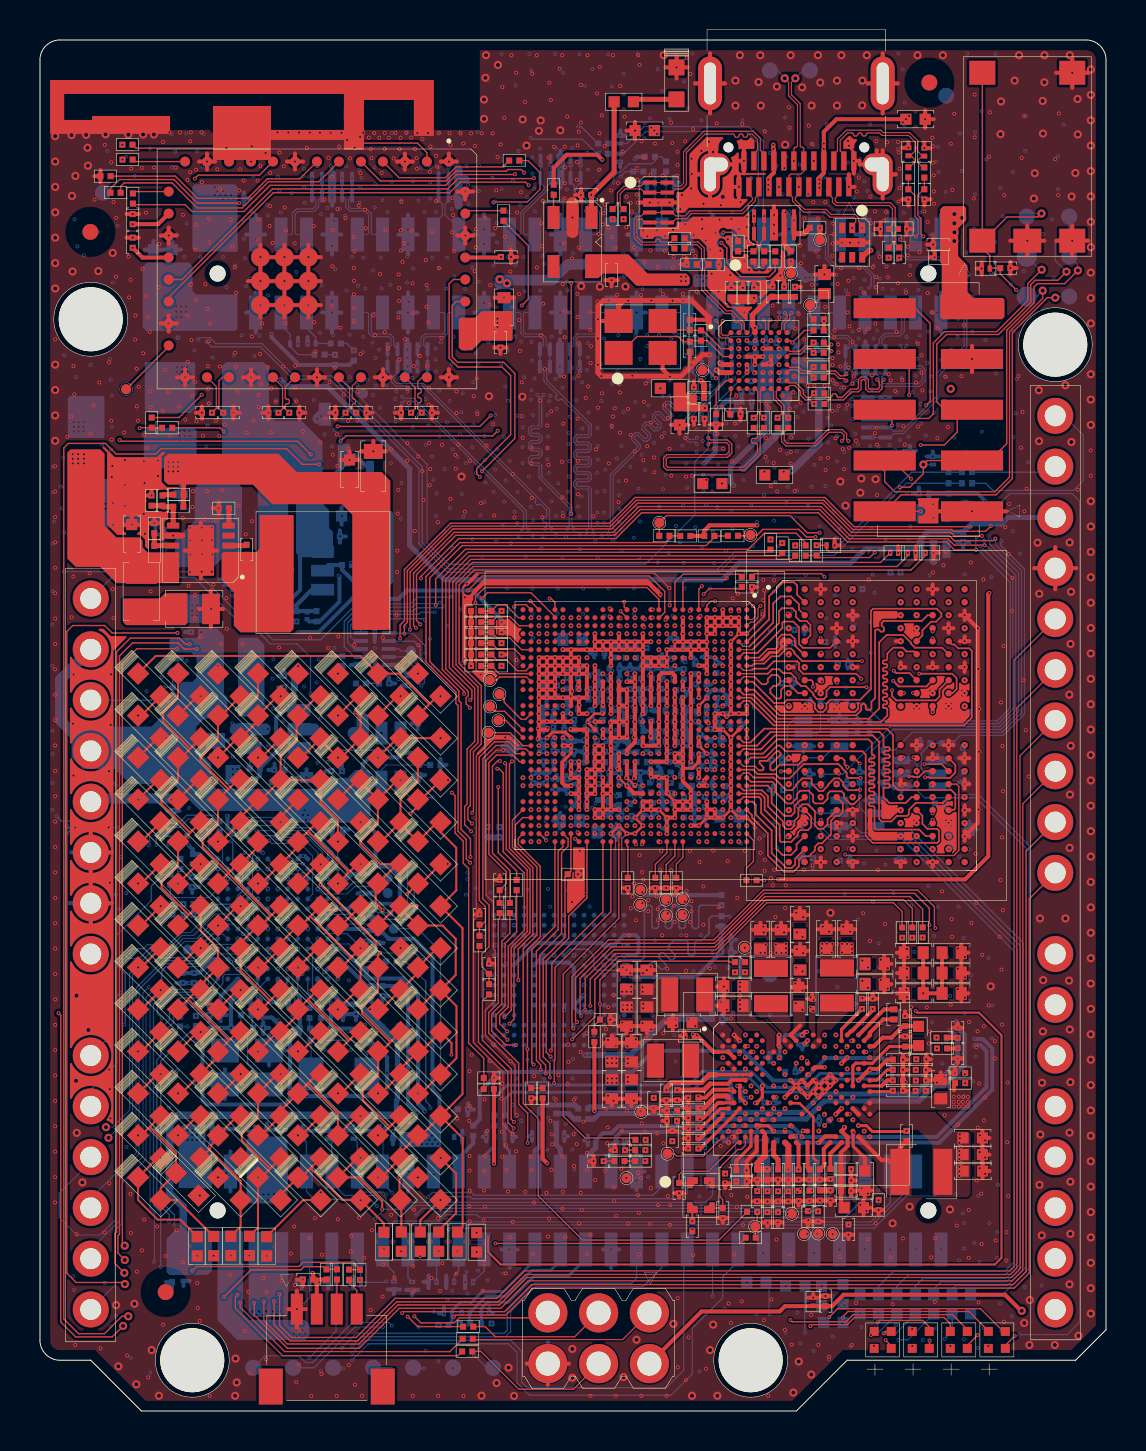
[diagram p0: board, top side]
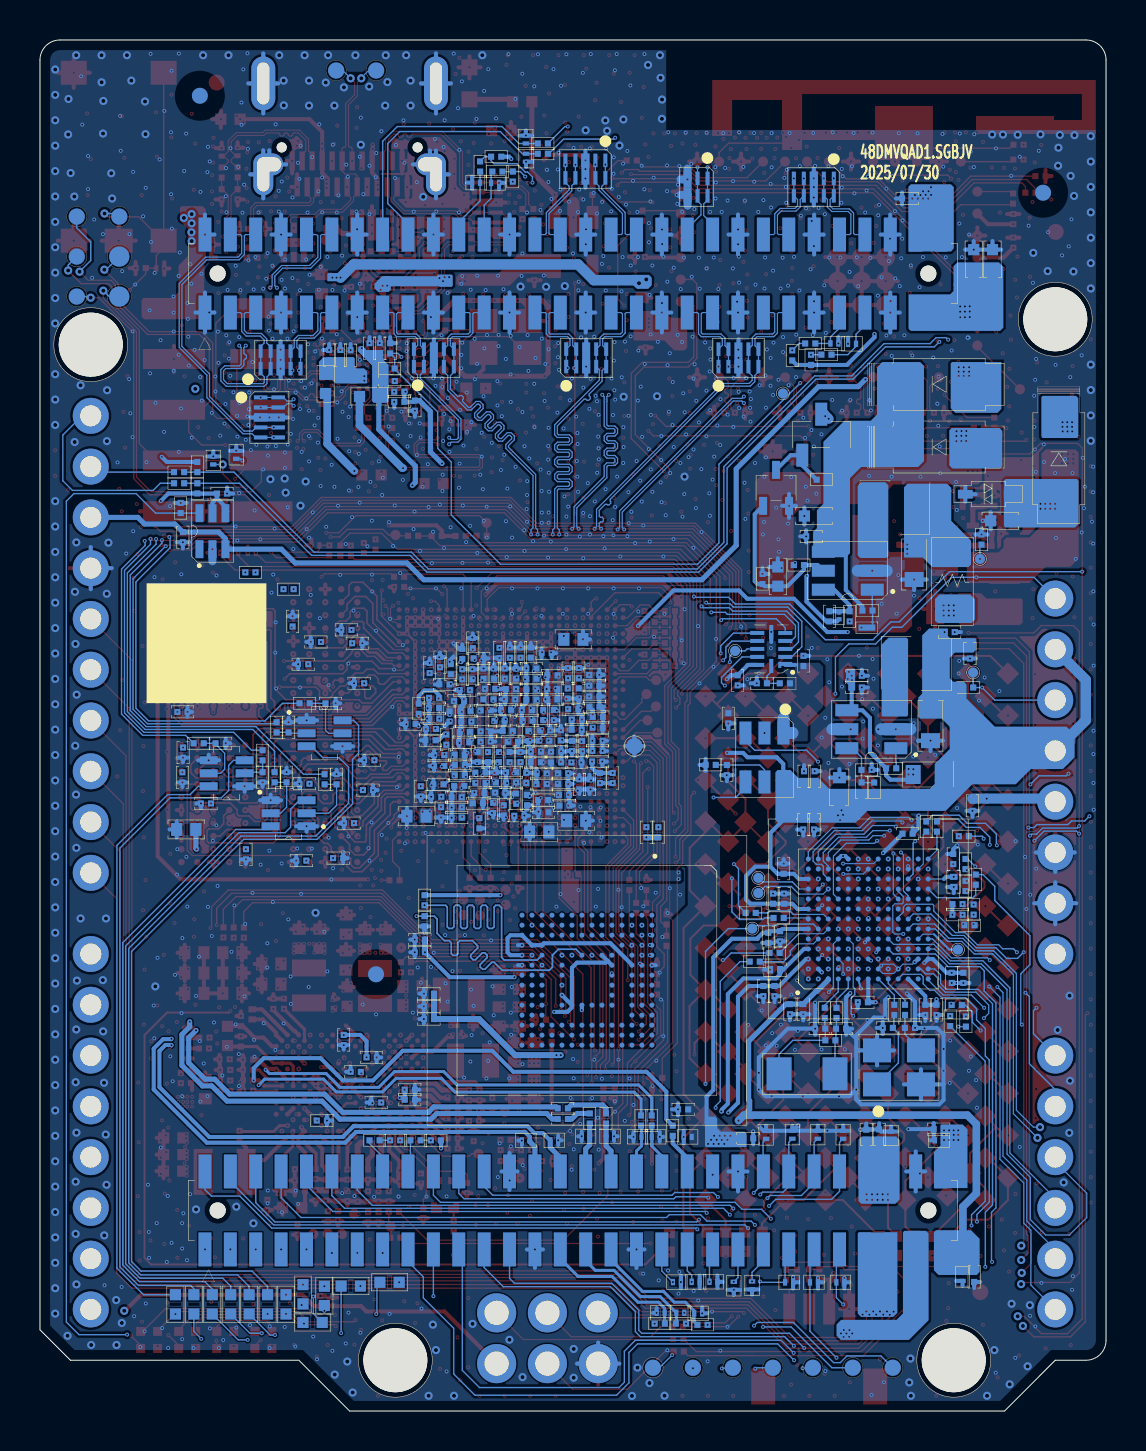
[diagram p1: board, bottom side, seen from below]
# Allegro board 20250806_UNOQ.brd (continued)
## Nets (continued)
AUX_CTRL_2: R3002.1 R3004.1 U3001.H1
BAT_ID: PMIC1.N17 R605.1 TP601.1(TP)
BAT_THERM: PMIC1.U19 R606.1 TP602.1(TP)
BOOT_CAP: C609.1 PMIC1.U25
BOOT_CONFIG0: R1303.2 R1304.1 SOC1.AH9
BOOT_CONFIG1: R1305.2 R1306.1 SOC1.AJ7
BOOT_CONFIG2: R1307.2 R1308.1 SOC1.AH8
BOOT_CONFIG3: R1309.2 R1310.1 SOC1.AH6
CBLPWR_N: PMIC1.T10 R705.1
CC_OUT: PMIC1.C7 R902.1
CCI_I2C_SCL0: R2606.1 R2607.1 SOC1.AD5
CCI_I2C_SCL0_CONN: D26051.2 JMEDIA1.51 R2607.2
CCI_I2C_SCL1: R2610.1 R2611.1 SOC1.AB2
CCI_I2C_SCL1_CONN: D26049.2 JMEDIA1.24 R2611.2
CCI_I2C_SDA0: R2605.1 R2608.1 SOC1.AD4
CCI_I2C_SDA0_CONN: D26050.2 JMEDIA1.53 R2608.2
CCI_I2C_SDA1: R2609.1 R2612.1 SOC1.AC4
CCI_I2C_SDA1_CONN: D26048.2 JMEDIA1.22 R2612.2
CDC_CP_FLY_N: C501.2 PMIC1.A27 PMIC1.B26
CDC_CP_FLY_P: C501.1 PMIC1.A25
CDC_CP_VNEG: C502.1 F501.1 PMIC1.C27
CDC_PA_VNEG: C503.1 F501.2 PMIC1.F26 PMIC1.K24
CSI0_A0_CLK_M: JMEDIA1.33 SOC1.N2 U2610.4 U2610.7
CSI0_A1_LN1_P: JMEDIA1.29 SOC1.P2 U2610.2 U2610.9(OUT#9)
CSI0_A2_LN2_M: JMEDIA1.39 SOC1.R2 U2609.1 U2609.10
CSI0_B0_LN0_P: JMEDIA1.23 SOC1.N3 U2606.5 U2606.6
CSI0_B1_LN1_M: JMEDIA1.27 SOC1.P3 U2610.1 U2610.10
CSI0_B2_LN3_P: JMEDIA1.47 SOC1.R3 U2609.5 U2609.6
CSI0_C0_LN0_M: JMEDIA1.21 SOC1.N4 U2606.4 U2606.7
CSI0_C1_LN2_P: JMEDIA1.41 SOC1.R1 U2609.2 U2609.9(OUT#9)
CSI0_C2_LN3_M: JMEDIA1.45 SOC1.R4 U2609.4 U2609.7
CSI0_NC_CLK_P: JMEDIA1.35 SOC1.N1 U2610.5 U2610.6
CSI1_A0_CLK_M: JMEDIA1.42 SOC1.T2 U2607.1 U2607.6(OUT#6)
CSI1_A1_LN1_P: JMEDIA1.46 SOC1.U2 U2605.5 U2605.6
CSI1_A2_LN2_M: JMEDIA1.36 SOC1.V2 U2608.1 U2608.10
CSI1_B0_LN0_P: JMEDIA1.52 SOC1.T3 U2605.2 U2605.9(OUT#9)
CSI1_B1_LN1_M: JMEDIA1.48 SOC1.U3 U2605.4 U2605.7
CSI1_B2_LN3_P: JMEDIA1.28 SOC1.V3 U2608.5 U2608.6
CSI1_C0_LN0_M: JMEDIA1.54 SOC1.T4 U2605.1 U2605.10
CSI1_C1_LN2_P: JMEDIA1.34 SOC1.V1 U2608.2 U2608.9(OUT#9)
CSI1_C2_LN3_M: JMEDIA1.30 SOC1.V4 U2608.4 U2608.7
CSI1_NC_CLK_P: JMEDIA1.40 SOC1.T1 U2607.2 U2607.5
DC_IN: C2618.1 C2619.1 C2631.1 D2802.1 D26201.2 JANALOG1.8 JMEDIA1.57 JMEDIA1.59
DDR_RESET_N: DRAM1.T11 SOC1.D26
DRAM_ZQ0: DRAM1.A5 R2201.2
DRAM_ZQ1: DRAM1.A8 R2202.2
DSI0_REXT_PLL: R1522.1 SOC1.L30
DSI1_CLK_M_TP: SOC1.M27 TP1501.1(TP)
DSI1_CLK_P_TP: SOC1.M28 TP1502.1(TP)
EAR_M: PMIC1.E27 R2671.1
EAR_M_R: C2632.1 D26064.2 JMISC1.30 R2671.2
EAR_P: PMIC1.D26 R2670.1
EAR_P_R: C2633.1 D26063.2 JMISC1.28 R2670.2
EBI0_CA_0: DRAM1.H2 SOC1.D9
EBI0_CA_1: DRAM1.J2 SOC1.B10
EBI0_CA_2: DRAM1.H9 SOC1.A8
EBI0_CA_3: DRAM1.H10 SOC1.B8
EBI0_CA_4: DRAM1.H11 SOC1.B9
EBI0_CA_5: DRAM1.J11 SOC1.E7
EBI0_CAL: R1401.2 SOC1.F14
EBI0_CKE_0: DRAM1.J4 SOC1.E8
EBI0_CKE_1: DRAM1.J5 SOC1.E9
EBI0_CLK_M: DRAM1.J9 SOC1.E10
EBI0_CLK_P: DRAM1.J8 SOC1.D10
EBI0_CS_0: DRAM1.H4 SOC1.D7
EBI0_CS_1: DRAM1.H3 SOC1.D8
EBI0_DMI_0: DRAM1.C3 SOC1.D5
EBI0_DMI_1: DRAM1.C10 SOC1.A11
EBI0_DQ0: DRAM1.B2 SOC1.A5
EBI0_DQ1: DRAM1.C2 SOC1.B5
EBI0_DQ2: DRAM1.E2 SOC1.B6
EBI0_DQ3: DRAM1.F2 SOC1.A7
EBI0_DQ4: DRAM1.F4 SOC1.D4
EBI0_DQ5: DRAM1.E4 SOC1.B7
EBI0_DQ6: DRAM1.C4 SOC1.E5
EBI0_DQ7: DRAM1.B4 SOC1.C4
EBI0_DQ8: DRAM1.B11 SOC1.E13
EBI0_DQ9: DRAM1.C11 SOC1.D13
EBI0_DQ10: DRAM1.E11 SOC1.B13
EBI0_DQ11: DRAM1.F11 SOC1.B11
EBI0_DQ12: DRAM1.F9 SOC1.B12
EBI0_DQ13: DRAM1.E9 SOC1.A10
EBI0_DQ14: DRAM1.C9 SOC1.E11
EBI0_DQ15: DRAM1.B9 SOC1.D11
EBI0_DQS_0_M: DRAM1.E3 SOC1.D6
EBI0_DQS_0_P: DRAM1.D3 SOC1.E6
EBI0_DQS_1_M: DRAM1.E10 SOC1.E12
EBI0_DQS_1_P: DRAM1.D10 SOC1.D12
EBI1_CA_0: DRAM1.R2 SOC1.E21
EBI1_CA_1: DRAM1.P2 SOC1.B20
EBI1_CA_2: DRAM1.R9 SOC1.A22
EBI1_CA_3: DRAM1.R10 SOC1.B22
EBI1_CA_4: DRAM1.R11 SOC1.B21
EBI1_CA_5: DRAM1.P11 SOC1.D23
EBI1_CKE_0: DRAM1.P4 SOC1.D22
EBI1_CKE_1: DRAM1.P5 SOC1.D21
EBI1_CLK_M: DRAM1.P9 SOC1.D20
EBI1_CLK_P: DRAM1.P8 SOC1.E20
EBI1_CS_0: DRAM1.R4 SOC1.E23
EBI1_CS_1: DRAM1.R3 SOC1.E22
EBI1_DMI_0: DRAM1.Y3 SOC1.E25
EBI1_DMI_1: DRAM1.Y10 SOC1.A19
EBI1_DQ0: DRAM1.AA2 SOC1.A25
EBI1_DQ1: DRAM1.Y2 SOC1.B25
EBI1_DQ2: DRAM1.V2 SOC1.B24
EBI1_DQ3: DRAM1.U2 SOC1.A23
EBI1_DQ4: DRAM1.U4 SOC1.A26
EBI1_DQ5: DRAM1.V4 SOC1.B23
EBI1_DQ6: DRAM1.Y4 SOC1.D25
EBI1_DQ7: DRAM1.AA4 SOC1.B26
EBI1_DQ8: DRAM1.AA11 SOC1.D17
EBI1_DQ9: DRAM1.Y11 SOC1.E17
EBI1_DQ10: DRAM1.V11 SOC1.B17
EBI1_DQ11: DRAM1.U11 SOC1.B19
EBI1_DQ12: DRAM1.U9 SOC1.B18
EBI1_DQ13: DRAM1.V9 SOC1.A20
EBI1_DQ14: DRAM1.Y9 SOC1.D19
EBI1_DQ15: DRAM1.AA9 SOC1.E19
EBI1_DQS_0_M: DRAM1.V3 SOC1.E24
EBI1_DQS_0_P: DRAM1.W3 SOC1.D24
EBI1_DQS_1_M: DRAM1.V10 SOC1.D18
EBI1_DQS_1_P: DRAM1.W10 SOC1.E18
EMMC1_VDDI: C2101.1 C2102.1 EMMC1.C2
FAULT_N_TP: PMIC1.R11 TP704.1(TP)
FM_ANT: R2909.2 U2901.7
FORCED_USB_BOOT_N: D26005.2 JCTL1.2 R901.2 R1311.2 R1312.1 SOC1.AD27 TP2611.1(TP)
FORCED_USB_BOOT_POL_SEL: R1313.2 R1314.1 SOC1.AC27
HPH_L: C509.1 PMIC1.L27 R2634.2
HPH_L_CONN: D26089.2 JMISC1.36 R2634.1
HPH_R: C507.1 PMIC1.J27 R2635.2
HPH_R_CONN: D26090.2 JMISC1.38 R2635.1
HPH_REF: C508.1 PMIC1.K26 R2633.2
HPH_REF_CONN: JMISC1.40 R2633.1
HS_DET: JMISC1.42 PMIC1.C23
JTAG_PS_HOLD: R709.2 TP1213.1(TP)
LDO1_EN: R2801.2 SB2801.2 U2801.1
LDO1_FB: C2803.2 R2802.2 R2803.1 U2801.6
LDO1_LX: L2801.1 U2801.3
LDO1_PG: C2808.1 Q2802.1 R2808.2 R2810.1 U2801.5
LDO2_EN: R2804.2 U2802.1
LDO2_FB: C2807.2 R2805.2 R2806.1 U2802.6
LDO2_LX: L2802.1 U2802.3
LED_MATRIX_0: MCU1.E2 R2711.1
LED_MATRIX_0_R: D27001.1 D27002.2(CATHODE) D27003.1 D27004.2(CATHODE) D27007.1 D27008.2(CATHODE) D27013.1 D27014.2(CATHODE) D27021.1 D27022.2(CATHODE) D27031.1 D27032.2(CATHODE) D27043.1 D27044.2(CATHODE) D27057.1 D27058.2(CATHODE) D27073.1 D27074.2(CATHODE) D27091.1 D27092.2(CATHODE) R2711.2
LED_MATRIX_1: MCU1.F3 R2701.1
LED_MATRIX_1_R: D27001.2(CATHODE) D27002.1 D27005.1 D27006.2(CATHODE) D27009.1 D27010.2(CATHODE) D27015.1 D27016.2(CATHODE) D27023.1 D27024.2(CATHODE) D27033.1 D27034.2(CATHODE) D27045.1 D27046.2(CATHODE) D27059.1 D27060.2(CATHODE) D27075.1 D27076.2(CATHODE) D27093.1 D27094.2(CATHODE) R2701.2
LED_MATRIX_2: MCU1.F4 R2702.1
LED_MATRIX_2_R: D27003.2(CATHODE) D27004.1 D27005.2(CATHODE) D27006.1 D27011.1 D27012.2(CATHODE) D27017.1 D27018.2(CATHODE) D27025.1 D27026.2(CATHODE) D27035.1 D27036.2(CATHODE) D27047.1 D27048.2(CATHODE) D27061.1 D27062.2(CATHODE) D27077.1 D27078.2(CATHODE) D27095.1 D27096.2(CATHODE) R2702.2
LED_MATRIX_3: MCU1.G5 R2703.1
LED_MATRIX_3_R: D27007.2(CATHODE) D27008.1 D27009.2(CATHODE) D27010.1 D27011.2(CATHODE) D27012.1 D27019.1 D27020.2(CATHODE) D27027.1 D27028.2(CATHODE) D27037.1 D27038.2(CATHODE) D27049.1 D27050.2(CATHODE) D27063.1 D27064.2(CATHODE) D27079.1 D27080.2(CATHODE) D27097.1 D27098.2(CATHODE) R2703.2
LED_MATRIX_4: MCU1.G6 R2704.1
LED_MATRIX_4_R: D27013.2(CATHODE) D27014.1 D27015.2(CATHODE) D27016.1 D27017.2(CATHODE) D27018.1 D27019.2(CATHODE) D27020.1 D27029.1 D27030.2(CATHODE) D27039.1 D27040.2(CATHODE) D27051.1 D27052.2(CATHODE) D27065.1 D27066.2(CATHODE) D27081.1 D27082.2(CATHODE) D27099.1 D27100.2(CATHODE) R2704.2
LED_MATRIX_5: MCU1.G4 R2705.1
LED_MATRIX_5_R: D27021.2(CATHODE) D27022.1 D27023.2(CATHODE) D27024.1 D27025.2(CATHODE) D27026.1 D27027.2(CATHODE) D27028.1 D27029.2(CATHODE) D27030.1 D27041.1 D27042.2(CATHODE) D27053.1 D27054.2(CATHODE) D27067.1 D27068.2(CATHODE) D27083.1 D27084.2(CATHODE) D27101.1 D27102.2(CATHODE) R2705.2
LED_MATRIX_6: MCU1.H6 R2706.1
LED_MATRIX_6_R: D27031.2(CATHODE) D27032.1 D27033.2(CATHODE) D27034.1 D27035.2(CATHODE) D27036.1 D27037.2(CATHODE) D27038.1 D27039.2(CATHODE) D27040.1 D27041.2(CATHODE) D27042.1 D27055.1 D27056.2(CATHODE) D27069.1 D27070.2(CATHODE) D27085.1 D27086.2(CATHODE) D27103.1 D27104.2(CATHODE) R2706.2
LED_MATRIX_7: MCU1.G2 R2707.1
LED_MATRIX_7_R: D27043.2(CATHODE) D27044.1 D27045.2(CATHODE) D27046.1 D27047.2(CATHODE) D27048.1 D27049.2(CATHODE) D27050.1 D27051.2(CATHODE) D27052.1 D27053.2(CATHODE) D27054.1 D27055.2(CATHODE) D27056.1 D27071.1 D27072.2(CATHODE) D27087.1 D27088.2(CATHODE) R2707.2
LED_MATRIX_8: MCU1.F1 R2708.1
LED_MATRIX_8_R: D27057.2(CATHODE) D27058.1 D27059.2(CATHODE) D27060.1 D27061.2(CATHODE) D27062.1 D27063.2(CATHODE) D27064.1 D27065.2(CATHODE) D27066.1 D27067.2(CATHODE) D27068.1 D27069.2(CATHODE) D27070.1 D27071.2(CATHODE) D27072.1 D27089.1 D27090.2(CATHODE) R2708.2
LED_MATRIX_9: MCU1.G3 R2709.1
LED_MATRIX_9_R: D27073.2(CATHODE) D27074.1 D27075.2(CATHODE) D27076.1 D27077.2(CATHODE) D27078.1 D27079.2(CATHODE) D27080.1 D27081.2(CATHODE) D27082.1 D27083.2(CATHODE) D27084.1 D27085.2(CATHODE) D27086.1 D27087.2(CATHODE) D27088.1 D27089.2(CATHODE) D27090.1 R2709.2
LED_MATRIX_10: MCU1.H4 R2710.1
LED_MATRIX_10_R: D27091.2(CATHODE) D27092.1 D27093.2(CATHODE) D27094.1 D27095.2(CATHODE) D27096.1 D27097.2(CATHODE) D27098.1 D27099.2(CATHODE) D27100.1 D27101.2(CATHODE) D27102.1 D27103.2(CATHODE) D27104.1 R2710.2
LED_MATRIX_11: MCU1.M5 TP2506.1(TP)
LED_PWR: D27201.1 R2735.2
LINEOUT_M: C514.1 R2632.2
LINEOUT_M_C: C514.2 PMIC1.D24
LINEOUT_M_CONN: D26088.2 JMISC1.34 R2632.1
LINEOUT_P: C513.1 R2631.2
LINEOUT_P_C: C513.2 PMIC1.C25
LINEOUT_P_CONN: D26087.2 JMISC1.32 R2631.1
LNBBCLK1: PMIC1.R5 R702.2
LNBBCLK2: PMIC1.U3 R703.2
LNBBCLK2_R: C720.1 R703.1
MCU_BOOT0: JANALOG1.1 MCU1.C5 R2621.1 TP2603.1(TP) U1101.10
MCU_BOOT0_1P8V: SOC1.AH1 U1101.2
MCU_BT_UART_CTS_R: R2906.2 U2901.14
MCU_BT_UART_RTS_R: R2904.2 U2901.11
MCU_BT_UART_RX_R: R2901.2 U2901.4
MCU_BT_UART_TX_R: R2908.2 U2901.41
MCU_CRS_SYNC_PA10: JMISC1.25 MCU1.F11
MCU_I2C2_SCL: MCU1.K9 R2643.2 R2644.1
MCU_I2C2_SCL_CONN: JDIGITAL1.18 R2644.2
MCU_I2C2_SDA: MCU1.L9 R2642.2 R2645.1
MCU_I2C2_SDA_CONN: JDIGITAL1.17 R2645.2
MCU_I2C4_SCL_PD12: MCU1.K10 R2614.2 R2615.1
MCU_I2C4_SCL_PD12_CONN: QWIIC1.4 R2615.2
MCU_I2C4_SCL_PF14: MCU1.L6 R2667.2 R2668.1
MCU_I2C4_SCL_PF14_CONN: JMISC1.16 R2668.2
MCU_I2C4_SDA_PD13: MCU1.K12 R2613.2 R2616.1
MCU_I2C4_SDA_PD13_CONN: QWIIC1.3 R2616.2
MCU_I2C4_SDA_PF15: MCU1.N6 R2666.2 R2669.1
MCU_I2C4_SDA_PF15_CONN: JMISC1.18 R2669.2
MCU_JTAG_NJTRST_PB4: JDIGITAL1.9 MCU1.B6 TP2504.1(TP)
MCU_JTAG_SWCLK: MCU1.C10 TP2503.1(TP) U1101.8
MCU_JTAG_SWCLK_1P8V: SOC1.AC3 U1101.4
MCU_JTAG_SWDIO: MCU1.F12 TP2502.1(TP) U1101.9
MCU_JTAG_SWDIO_1P8V: SOC1.AC2 U1101.3
MCU_JTAG_SWO_PB3: JDIGITAL1.3 MCU1.D6
MCU_JTAG_TDI: MCU1.A10 TP2501.1(TP)
MCU_LED1_BLU: MCU1.B13 R2731.2
MCU_LED1_BLU_D: D27401.3(CATHODE#4) R2731.1
MCU_LED1_GRN: MCU1.D9 R2730.2
MCU_LED1_GRN_D: D27401.4 R2730.1
MCU_LED1_RED: MCU1.C13 R2729.2
MCU_LED1_RED_D: D27401.2 R2729.1
MCU_LED2_BLU: MCU1.A13 R2734.2
MCU_LED2_BLU_D: D27402.3(CATHODE#4) R2734.1
MCU_LED2_GRN: MCU1.C11 R2733.2
MCU_LED2_GRN_D: D27402.4 R2733.1
MCU_LED2_RED: MCU1.C12 R2732.2
MCU_LED2_RED_D: D27402.2 R2732.1
MCU_MCO_PA8: JMISC1.23 MCU1.G7
MCU_NRST: JANALOG1.3 JSPI1.5 MCU1.H3 R2622.2 TP2602.1(TP) U1101.7
MCU_NRST_1P8V: SOC1.AH2 U1101.5
MCU_OPAMP1_ VINM_PA1: JMISC1.24 MCU1.L3
MCU_OPAMP1_ VINP_PA0: JMISC1.22 MCU1.K3
MCU_OPAMP1_VOUT_PA3: JMISC1.20 MCU1.N2
MCU_OSC32_IN_PC14: MCU1.D1 R2514.2
MCU_OSC32_OUT_PC15: MCU1.E1 R2513.1
MCU_OSC_IN_PH0_R: MCU1.H1 R2509.1
MCU_OSC_OUT_PH1_R: MCU1.J1 R2511.1
MCU_PA4: JANALOG1.9 MCU1.N1
MCU_PA5: JANALOG1.10 MCU1.K4
MCU_PA6: JANALOG1.11 MCU1.N4
MCU_PA7: JANALOG1.12 MCU1.J5
MCU_PA11: JDIGITAL1.6 MCU1.G13
MCU_PA12: JDIGITAL1.5 MCU1.F13
MCU_PB0: JDIGITAL1.4 MCU1.K5
MCU_PB1: JDIGITAL1.7 MCU1.N5
MCU_PB2: JDIGITAL1.8 MCU1.L5
MCU_PB8: JDIGITAL1.10 MCU1.E5
MCU_PC0: JANALOG1.14 MCU1.J2
MCU_PC1: JANALOG1.13 MCU1.J3
MCU_PE7: JMISC1.12 MCU1.L7
MCU_PE8: JMISC1.14 MCU1.K7
MCU_PSSI_D0: JMISC1.1 MCU1.H13
MCU_PSSI_D1: JMISC1.3 MCU1.G12
MCU_PSSI_D2: JMISC1.5 MCU1.G10
MCU_PSSI_D3: JMISC1.7 MCU1.G9
MCU_PSSI_D4: JMISC1.9 MCU1.C2
MCU_PSSI_D5: JMISC1.11 MCU1.B10
MCU_PSSI_D6: JMISC1.13 MCU1.A2
MCU_PSSI_D7: JMISC1.15 MCU1.C3
MCU_PSSI_DE: JMISC1.21 MCU1.L12
MCU_PSSI_PDCK: JMISC1.17 MCU1.L13
MCU_PSSI_RDY: JMISC1.19 MCU1.B3
MCU_SDMMC1_CMD_PD2: JMISC1.2 MCU1.F7
MCU_SOC_LPUART1_CTS: MCU1.J9 R2501.1
MCU_SOC_LPUART1_RTS: MCU1.H10 R2502.1
MCU_SOC_LPUART1_RX: MCU1.H9 R2504.1
MCU_SOC_LPUART1_TX: MCU1.G8 R2503.1
MCU_SPI2_CLK: MCU1.N13 R2641.1
MCU_SPI2_CLK_CONN: JDIGITAL1.14 R2641.2
MCU_SPI2_CLK_PD1: MCU1.F6 R2617.1
MCU_SPI2_CLK_PD1_CONN: JSPI1.3 R2617.2
MCU_SPI2_MISO: MCU1.M12 R2640.1
MCU_SPI2_MISO_CONN: JDIGITAL1.13 R2640.2
MCU_SPI2_MISO_PC2: MCU1.J4 R2618.1
MCU_SPI2_MISO_PC2_CONN: JSPI1.1 R2618.2
MCU_SPI2_MOSI: MCU1.L11 R2626.1
MCU_SPI2_MOSI_CONN: JDIGITAL1.12 R2626.2
MCU_SPI2_MOSI_PC3: MCU1.K1 R2619.1
MCU_SPI2_MOSI_PC3_CONN: JSPI1.4 R2619.2
MCU_SPI2_NSS: MCU1.D5 R2625.1
MCU_SPI2_NSS_CONN: JDIGITAL1.11 R2625.2
MCU_SPI3_CLK: R2505.2 SOC1.AA29
MCU_SPI3_CLK_R: MCU1.A7 R2505.1
MCU_SPI3_CS_N: R2508.2 SOC1.AA30
MCU_SPI3_CS_N_R: MCU1.E6 R2508.1
MCU_SPI3_MISO: R2506.2 SOC1.W30
MCU_SPI3_MISO_R: MCU1.C7 R2506.1
MCU_SPI3_MOSI_1P8V: SOC1.Y29 U1102.3
MCU_SPI3_MOSI_3P3V: R2507.1 U1102.4
MCU_SPI3_MOSI_R: MCU1.C6 R2507.2
MCU_SPI3_RDY: R2516.2 SOC1.W29
MCU_SPI3_RDY_R: MCU1.N10 R2516.1
MCU_TRACE_CLK: JMISC1.4 MCU1.A1
MCU_TRACE_D0: JMISC1.6 MCU1.D3
MCU_TRACE_D2: JMISC1.8 MCU1.D2
MCU_TRACE_D3: JMISC1.10 MCU1.E4
MCU_USART1_RX: MCU1.F5 R2624.1
MCU_USART1_RX_CONN: JDIGITAL1.1 R2624.2
MCU_USART1_TX: MCU1.B5 R2623.1
MCU_USART1_TX_CONN: JDIGITAL1.2 R2623.2
MCU_VCAP: C2501.1 C2525.1 MCU1.A4 MCU1.N11
MCU_VREF+: C2520.1 C2521.1 C2614.1 JDIGITAL1.16 MCU1.L1 U2501.3
MCU_VREF_EN: MCU1.M2 R2515.1 U2501.6
MIC2_BIAS: C512.1 PMIC1.G23 R2646.2
MIC2_BIAS_CONN: D26067.2 JMISC1.33 R2646.1
MIC2_INN: C510.1 PMIC1.L21 R2637.2
MIC2_INN_CONN: D26066.2 JMISC1.31 R2637.1
MIC2_INP: C511.1 PMIC1.M20 R2636.2
MIC2_INP_CONN: D26065.2 JMISC1.29 R2636.1
MIPI_DSI0_CLK_M: R1501.1 SOC1.P27 U3001.H8
MIPI_DSI0_CLK_M_CONN: JMEDIA1.3 R1501.2 U2612.1 U2612.10
MIPI_DSI0_CLK_P: R1502.1 SOC1.R28 U3001.G8
MIPI_DSI0_CLK_P_CONN: JMEDIA1.5 R1502.2 U2612.2 U2612.9(OUT#9)
MIPI_DSI0_L0_M: R1503.1 SOC1.P30 U3001.F8
MIPI_DSI0_L0_M_CONN: JMEDIA1.12 R1503.2 U2611.1 U2611.10
MIPI_DSI0_L0_P: R1504.1 SOC1.R30 U3001.E8
MIPI_DSI0_L0_P_CONN: JMEDIA1.10 R1504.2 U2611.2 U2611.9(OUT#9)
MIPI_DSI0_L1_M: R1505.1 SOC1.M30 U3001.H6
MIPI_DSI0_L1_M_CONN: JMEDIA1.6 R1505.2 U2611.4 U2611.7
MIPI_DSI0_L1_P: R1506.1 SOC1.M29 U3001.H7
MIPI_DSI0_L1_P_CONN: JMEDIA1.4 R1506.2 U2611.5 U2611.6
MIPI_DSI0_L2_M: R1507.1 SOC1.N29 U3001.D8
MIPI_DSI0_L2_M_CONN: JMEDIA1.9 R1507.2 U2612.4 U2612.7
MIPI_DSI0_L2_P: R1508.1 SOC1.P29 U3001.C8
MIPI_DSI0_L2_P_CONN: JMEDIA1.11 R1508.2 U2612.5 U2612.6
MIPI_DSI0_L3_M: R1509.1 SOC1.N28 U3001.H4
MIPI_DSI0_L3_M_CONN: JMEDIA1.15 R1509.2 U2606.1 U2606.10
MIPI_DSI0_L3_P: R1510.1 SOC1.N27 U3001.H5
MIPI_DSI0_L3_P_CONN: JMEDIA1.17 R1510.2 U2606.2 U2606.9(OUT#9)
MUX_ALERT: R3025.2 SOC1.AG29 U3001.B8
MUX_CABLE_DET: SOC1.AG1 TP3007.1(TP) U3001.C3
MUX_DP_HPD: R3028.2 SOC1.K1
MUX_DP_HPD_R: R3028.1 U3001.E7
MUX_I2C_SCL_R: R3014.2 TP3002.1(TP) U3001.D7
MUX_I2C_SDA_R: R3015.2 TP3003.1(TP) U3001.C7
MUX_LDO_EN: R3024.2 U3004.3
MUX_POWER_EN: C3028.1 R3022.2 SOC1.AE1 TP3001.1(TP) U3001.D2
MUX_RESET_N: C3027.1 R3023.2 SOC1.AF5 TP3006.1(TP) U3001.B7
MUX_SBU1: C3019.2 JUSB1.A8 R3003.2 U2602.1 U2602.10
MUX_SBU2: C3020.2 JUSB1.B8 R3004.2 U2602.2 U2602.9(OUT#9)
MUX_SSRXN1: C2629.2 R2665.1 U3001.B3
MUX_SSRXN1_C: C2629.1 D26102.2 JUSB1.B10
MUX_SSRXN2: C2627.1 R2660.1 U3001.A3
MUX_SSRXN2_C: C2627.2 JUSB1.A10 U2601.5 U2601.6
MUX_SSRXP1: C2630.2 R2664.1 U3001.B4
MUX_SSRXP1_C: C2630.1 D26103.2 JUSB1.B11
MUX_SSRXP2: C2628.1 R2661.1 U3001.A2
MUX_SSRXP2_C: C2628.2 JUSB1.A11 U2601.4 U2601.7
MUX_SSTXN1: C2602.2 U3001.A5
MUX_SSTXN1_C: C2602.1 D26105.2 JUSB1.A3
MUX_SSTXN2: C2603.2 U3001.B6
MUX_SSTXN2_C: C2603.1 JUSB1.B3 U2601.1 U2601.10
MUX_SSTXP1: C2601.2 U3001.A6
MUX_SSTXP1_C: C2601.1 D26104.2 JUSB1.A2
MUX_SSTXP2: C2604.2 U3001.B5
MUX_SSTXP2_C: C2604.1 JUSB1.B2 U2601.2 U2601.9(OUT#9)
MUX_XTAL_IN: C3021.1 R3007.2 U3001.D1 Y3001.1
MUX_XTAL_OUT: C3022.1 R3007.1 U3001.C1(XTAL_OUT) Y3001.3
OSC_16M_IN: C2522.1 R2509.2 Y2501.1
OSC_16M_OUT: C2523.1 R2511.2 Y2501.3
OSC_32K_IN: C2528.1 R2512.2 R2514.1 Y2502.2
OSC_32K_OUT: C2527.1 R2512.1 R2513.2 Y2502.1
PACK_VSNS_M: PMIC1.T24 R604.1
PHONE_ON_N: C2605.1 D26009.2 JBTN1.1 JBTN1.2 PMIC1.P12 TP2614.1(TP)
PM_AVDD_BYP: C714.1 PMIC1.K6
PM_DVDD_BYP: C715.1 PMIC1.L7
PM_REF_BYP: C716.1 PMIC1.M6
PM_RESIN_N: D26008.2 JCTL1.8 PMIC1.N9 R708.2
PM_XTAL_IN: C702.1 PMIC1.W5 Y701.3(XT2)
PM_XTAL_OUT: C701.1 PMIC1.Y4 Y701.1
PMIC_FORCED_USB_BOOT: PMIC1.A5 R901.1
PMIC_PWM_TP: PMIC1.D8 TP1301.1(TP)
PON_OPTION: PMIC1.R9 R707.1
PS_HOLD: R706.2 SOC1.AH27
PS_HOLD_R: PMIC1.P10 R706.1 R709.1 TP706.1(TP)
PWR_3P3V: C1102.1 C1104.1 C2502.1 C2503.1 C2504.1 C2505.1 C2506.1 C2507.1 C2508.1 C2509.1 C2510.1 C2511.1 C2512.1 C2513.1 C2517.1 C2518.1 C2519.1 C2529.1 C2610.1 C2615.1 C2616.1 C2620.1 C2807.1 C2809.1 C3025.1 D27301.1 D27302.1 D27401.1 D27402.1 JANALOG1.2 JANALOG1.4 JMEDIA1.58 JMEDIA1.60 JMISC1.53 JMISC1.55 L2802.2 MCU1.A3 MCU1.A8 MCU1.A11 MCU1.B1 MCU1.D13 MCU1.E13 MCU1.G1 MCU1.J13 MCU1.L2 MCU1.N3 MCU1.N7 MCU1.N12 QWIIC1.2 R2613.1 R2614.1 R2622.1 R2642.1 R2643.1 R2666.1 R2667.1 R2735.1 R2805.1 R2817.2 U1101.11(VCCB) U1102.6(VCCB) U2501.4 U2501.5(VCC) U3004.1
PWR_3P8V: C2803.1 C2804.1 C2805.1 C2806.1 L2801.2 R2802.1 R2804.1 R2807.1 R2808.1 R2817.1 U2802.4(VIN)
QCA_SB_CLK: R2902.1 SOC1.AG19
QCA_SB_CLK_R: R2902.2 U2901.6
QCA_SB_DATA: SOC1.AG18 U2901.10
QREFS_CXO_REXT: R1601.1 SOC1.T30
QUIET_THERM: PMIC1.T20 RT701.1
RESOUT_N: EMMC1.K5 SOC1.AJ26
RFCLK1_TP: PMIC1.W1 TP701.1(TP)
RFCLK2: PMIC1.V2 R701.2
RFCLK3_TP: PMIC1.T4 TP702.1(TP)
RTC_SLEEP_CLK: PMIC1.F10 R1204.1 R2903.1
RTC_SLEEP_CLK_R: R2903.2 U2901.9
SBU1_AUXP: C3019.1 U3001.B2
SBU2_AUXN: C3020.1 U3001.C2
SD_CARD_DET_N_TP: SOC1.AH10 TP1315.1(TP)
SDC1_CLK: EMMC1.M6 R1207.2
SDC1_CLK_TR: R1207.1 SOC1.A29
SDC1_CMD: EMMC1.M5 R2114.2 SOC1.C27
SDC1_DATA_0: EMMC1.A3 SOC1.B28
SDC1_DATA_1: EMMC1.A4 SOC1.B29
SDC1_DATA_2: EMMC1.A5 SOC1.B30
SDC1_DATA_3: EMMC1.B2 SOC1.C28
SDC1_DATA_4: EMMC1.B3 SOC1.C29
SDC1_DATA_5: EMMC1.B4 SOC1.C30
SDC1_DATA_6: EMMC1.B5 SOC1.D28
SDC1_DATA_7: EMMC1.B6 SOC1.D29
SDC1_RCLK: EMMC1.H5 R2113.1 SOC1.A28
SLEEP_CLK: R1204.2 SOC1.AH26
SM_LNBBCLK1: R702.1 SOC1.U29
SM_RESIN_N: PMIC1.M14 R1201.1 TP705.1(TP)
SM_RESIN_N_R: C1201.1 R1201.2 SOC1.AJ20
SM_THERM: PMIC1.P18 RT1901.1
SOC_BID0: R1315.2 R1316.1 SOC1.AH3
SOC_BID1: R1317.2 R1318.1 SOC1.AJ2
SOC_BT_UART_CTS: R2906.1 SOC1.E1
SOC_BT_UART_RTS: R2904.1 SOC1.F1
SOC_BT_UART_RX: R2901.1 SOC1.H1
SOC_BT_UART_TX: R2908.1 SOC1.G1
SOC_CAM_MCLK0: R2638.1 SOC1.L2
SOC_CAM_MCLK0_R: D26046.2 JMEDIA1.16 R2638.2
SOC_CAM_MCLK1: R2639.1 SOC1.M2
SOC_CAM_MCLK1_R: D26047.2 JMEDIA1.18 R2639.2
SOC_GPIO18: D26075.2 JMISC1.49 SOC1.M1
SOC_GPIO28: D26076.2 JMISC1.51 SOC1.M4
SOC_GPIO_0_SE0: D26069.2 JMISC1.37 SOC1.T27
SOC_GPIO_1_SE0: D26070.2 JMISC1.39 SOC1.T28
SOC_GPIO_2_SE0: D26071.2 JMISC1.41 SOC1.U27
SOC_GPIO_3_SE0: D26072.2 JMISC1.43 SOC1.V27
SOC_GPIO_82_SE0: D26074.2 JMISC1.47 SOC1.V28
SOC_GPIO_86_SE0: D26073.2 JMISC1.45 SOC1.V30
SOC_GPIO_98: D26091.2 JMISC1.46 SOC1.AG23
SOC_GPIO_99: D26092.2 JMISC1.48 SOC1.AH23
SOC_GPIO_100: D26093.2 JMISC1.50 SOC1.AJ23
SOC_GPIO_101: D26094.2 JMISC1.52 SOC1.AE22
SOC_I2S_D0: R3018.1 SOC1.AJ22
SOC_I2S_D0_R: R3018.2 U3001.F6
SOC_I2S_SCK: R3016.1 SOC1.AF22
SOC_I2S_SCK_R: R3016.2 U3001.F7
SOC_I2S_WS: R3017.1 SOC1.AH22
SOC_I2S_WS_R: R3017.2 U3001.G7
SOC_LED1_BLU: R2714.1 SOC1.AE2
SOC_LED1_BLU_B: C2703.1 Q2708.2 R2714.2
SOC_LED1_BLU_C: Q2708.6 R2725.2
SOC_LED1_BLU_D: D27301.3(CATHODE#4) R2725.1
SOC_LED1_GRN: R2713.1 SOC1.AF3
SOC_LED1_GRN_B: C2702.1 Q2707.5 R2713.2
SOC_LED1_GRN_C: Q2707.3 R2724.2
SOC_LED1_GRN_D: D27301.4 R2724.1
SOC_LED1_RED: R2712.1 SOC1.AG2
SOC_LED1_RED_B: C2701.1 Q2707.2 R2712.2
SOC_LED1_RED_C: Q2707.6 R2723.2
SOC_LED1_RED_D: D27301.2 R2723.1
SOC_LED2_BLU: R2717.1 SOC1.AH4
SOC_LED2_BLU_B: C2706.1 Q2709.5 R2717.2
SOC_LED2_BLU_C: Q2709.3 R2728.2
SOC_LED2_BLU_D: D27302.3(CATHODE#4) R2728.1
SOC_LED2_GRN: R2716.1 SOC1.AG4
SOC_LED2_GRN_B: C2705.1 Q2709.2 R2716.2
SOC_LED2_GRN_C: Q2709.6 R2727.2
SOC_LED2_GRN_D: D27302.4 R2727.1
SOC_LED2_RED: R2715.1 SOC1.AF4
SOC_LED2_RED_B: C2704.1 Q2708.5 R2715.2
SOC_LED2_RED_C: Q2708.3 R2726.2
SOC_LED2_RED_D: D27302.2 R2726.1
SOC_MCU_LPUART1_CTS: R2502.2 SOC1.Y28
SOC_MCU_LPUART1_RTS: R2501.2 SOC1.AA28
SOC_MCU_LPUART1_RX: R2503.2 SOC1.AB28
SOC_MCU_LPUART1_TX: R2504.2 SOC1.AA27
SOC_UART_RX_SE4: D26007.2 JCTL1.6 SOC1.AG30 TP2616.1(TP)
SOC_UART_TX_SE4: D26006.2 JCTL1.4 SOC1.AF29 TP2615.1(TP)
SPMI_CLK: PMIC1.K10 R1205.1
SPMI_CLK_R: C1202.1 R1205.2 SOC1.AH19
SPMI_DATA: PMIC1.K12 R1206.1
SPMI_DATA_R: C1203.1 R1206.2 SOC1.AJ19
SWR_RX_CLK: R502.2 SOC1.AF19
SWR_RX_CLK_R: PMIC1.A21 R502.1
SWR_RX_DATA0: R503.2 SOC1.AE19
SWR_RX_DATA0_R: PMIC1.C21 R503.1
SWR_RX_DATA1: R501.2 SOC1.AF18
SWR_RX_DATA1_R: PMIC1.E19 R501.1
SWR_TX_CLK: PMIC1.D22 R1301.2
SWR_TX_CLK_R: R1301.1 SOC1.AF20
SWR_TX_DATA0: PMIC1.E21 R1302.2
SWR_TX_DATA0_R: R1302.1 SOC1.AE20
TP_GPIO_72: SOC1.AH18 TP1311.1(TP)
TP_GPIO_74: SOC1.AJ17 TP1313.1(TP)
TP_GPIO_75: SOC1.AJ16 TP1314.1(TP)
TP_GPIO_79: SOC1.AH14 TP1310.1(TP)
TP_JTAG_SRST_N: SOC1.AD28 TP1207.1(TP)
TP_JTAG_TCK: SOC1.AD30 TP1208.1(TP)
TP_JTAG_TDI: SOC1.AE30 TP1209.1(TP)
TP_JTAG_TDO: SOC1.AD29 TP1210.1(TP)
TP_JTAG_TMS: SOC1.AE29 TP1211.1(TP)
TP_JTAG_TRST_N: R1208.1 SOC1.AC29 TP1212.1(TP)
TP_USB0_SS_RX1_M: SOC1.G29 TP1203.1(TP)
TP_USB0_SS_RX1_P: SOC1.H29 TP1204.1(TP)
TP_USB0_SS_TX1_M: SOC1.J28 TP1205.1(TP)
TP_USB0_SS_TX1_P: SOC1.J27 TP1206.1(TP)
USB0_HS_DM: JUSB1.A7 JUSB1.B7 SOC1.K29 TP2613.1(TP) U2604.2
USB0_HS_DP: JUSB1.A6 JUSB1.B6 SOC1.K28 TP2612.1(TP) U2604.1
USB0_HS_REXT: R1203.1 SOC1.K30
USB0_SS_REXT: R1202.1 SOC1.J30
USB0_SS_RX0_M: SOC1.F30 U3001.B1
USB0_SS_RX0_P: SOC1.G30 U3001.A1
USB0_SS_TX0_M: SOC1.H27 U3001.A7
USB0_SS_TX0_P: SOC1.G27 U3001.A8
USB_CC1: JUSB1.A5 R3005.2 U2602.4 U2602.7
USB_CC1_R_MUX: R3005.1 TP3004.1(TP) U3001.E1
USB_CC2: JUSB1.B5 R3006.2 U2602.5 U2602.6
USB_CC2_R_MUX: R3006.1 TP3005.1(TP) U3001.F1
USB_I2C_SCL: R3014.1 R3027.2 SOC1.AB29
USB_I2C_SDA: R3015.1 R3026.2 SOC1.AB30
USB_IN_MID: C608.1 C902.1 PMIC1.H12 PMIC1.V24
USB_PHY_PS: R902.2 R1319.2 R1320.1 SOC1.AJ29
USB_VBUS_IN: C601.1 C602.1 C603.1 PMIC1.V22 PMIC1.W23 Q2801.3 R601.1 R607.1 R3013.1
VCOIN: C708.1 C709.1 C710.1 C711.1 C712.1 C713.1 C2524.1 C2526.1 C2625.1 D26100.2 JMISC1.59 MCU1.C1 PMIC1.H16
VCONN_IN: C3016.1 C3017.1 C3018.1 R3013.2 R3019.1 U3001.F2
VFB_NEG_S3: PMIC1.D6
VFB_NEG_S4: PMIC1.E5
VFB_S3: PMIC1.C5
VFB_S4: PMIC1.D4
VOLUME_DOWN_N: D26001.2 JCTL1.3 R708.1 R1321.2 TP2618.1(TP)
VOLUME_DOWN_R: R1321.1 SOC1.AD2
VOLUME_UP_N: D26002.2 JCTL1.5 SOC1.AH30 TP2617.1(TP)
VPH_PWR: C604.1 C605.1 C606.1 C901.1 C1001.1 C1002.1 C1003.1 C1004.1 L601.2 PMIC1.A13 PMIC1.A17 PMIC1.B14 PMIC1.C1 PMIC1.C3 PMIC1.D2 PMIC1.E3 PMIC1.G17 PMIC1.K8 PMIC1.N7 PMIC1.P24 PMIC1.R25 PMIC1.W15 PMIC1.W21 PMIC1.Y18
VREF_LPDDR3: C717.1 PMIC1.M10
VREF_MSM_1P25V: C718.1 C1702.1 C1703.1 C1843.1 PMIC1.N13 SOC1.AD17 SOC1.AD19
VREF_TXDAC_1P25V: C719.1 C1704.1 PMIC1.T8 SOC1.AC14
VREG_L1A_0P848V: C806.1 C807.1 C1727.1 C1728.1 C1729.1 C1730.1 C1731.1 C1732.1 C1733.1 C1734.1 C1735.1 C1736.1 C1737.1 C1738.1 C1739.1 C1740.1 C1741.1 C1742.1 C1743.1 C1849.1 C1850.1 C1901.1 C1902.1 C1903.1 C1910.1 C1914.1 PMIC1.D10 SOC1.AB20 SOC1.AB21 SOC1.H9 SOC1.H11 SOC1.H13 SOC1.H15 SOC1.H18 SOC1.H20 SOC1.H22 SOC1.L10 SOC1.L11 SOC1.L12 SOC1.L13 SOC1.L14 SOC1.L15 SOC1.L16 SOC1.L17 SOC1.L18 SOC1.L19 SOC1.L20 SOC1.N20 SOC1.P24 SOC1.R19 SOC1.T23 SOC1.U22 SOC1.V9 SOC1.V10 SOC1.V11 SOC1.V12 SOC1.V13 SOC1.V14 SOC1.Y15
VREG_L2A_1P128V: C808.1 C809.1 C1830.1 C1831.1 C2209.1 C2210.1 C2211.1 C2212.1 C2213.1 C2214.1 C2216.1 DRAM1.A4 DRAM1.A9 DRAM1.AB4 DRAM1.AB9 DRAM1.F5 DRAM1.F8 DRAM1.G2 DRAM1.H1 DRAM1.H5 DRAM1.H8 DRAM1.H12 DRAM1.K1 DRAM1.K3 DRAM1.K10 DRAM1.K12 DRAM1.N1 DRAM1.N3 DRAM1.N10 DRAM1.N12 DRAM1.R1 DRAM1.R5 DRAM1.R8 DRAM1.R12 DRAM1.T2 DRAM1.U5 DRAM1.U8 PMIC1.B16 SOC1.F10 SOC1.F13 SOC1.F18 SOC1.F21 SOC1.F24
VREG_L3A_0P6V: C810.1 C811.1 C1925.1 C1936.1 C1937.1 C1938.1 C2201.1 C2202.1 C2203.1 C2204.1 C2205.1 C2206.1 C2207.1 C2208.1 C2215.1 DRAM1.AA3 DRAM1.AA5 DRAM1.AA8 DRAM1.AA10 DRAM1.B3 DRAM1.B5 DRAM1.B8 DRAM1.B10 DRAM1.D1 DRAM1.D5 DRAM1.D8 DRAM1.D12 DRAM1.F3 DRAM1.F10 DRAM1.U3 DRAM1.U10 DRAM1.W1 DRAM1.W5 DRAM1.W8 DRAM1.W12 PMIC1.D12 R1401.1 R2201.1 R2202.1 SOC1.F12 SOC1.F19 SOC1.G9 SOC1.G10 SOC1.G13 SOC1.G14 SOC1.G17 SOC1.G18 SOC1.G21 SOC1.G22
VREG_L4A_2P96V: C812.1 C1851.1 PMIC1.Y14 SOC1.AE17
VREG_L5A_1P232V: C813.1 C1905.1 C1906.1 C1907.1 C1908.1 C1909.1 C1922.1 C1923.1 C1924.1 C1934.1 PMIC1.P2 SOC1.AB10 SOC1.AB11 SOC1.F15 SOC1.N24 SOC1.P23 SOC1.R7 SOC1.T7
VREG_L6A_0P9V: C814.1 C1904.1 C1915.1 C1916.1 PMIC1.R1 SOC1.G15 SOC1.R25
VREG_L7A_0P664V: C815.1 C1845.1 C1846.1 C1847.1 C1848.1 PMIC1.N3 SOC1.J9 SOC1.J10 SOC1.J11
VREG_L8A_1P0V: C816.1 C1824.1 C1825.1 PMIC1.J5 SOC1.W16 SOC1.W17
VREG_L9A_1P0V: C817.1 C1826.1 C1827.1 C1828.1 PMIC1.L3(VREG_L9) SOC1.Y17
VREG_L10A_1P3V: C818.1 C1935.1 C2901.1 PMIC1.H6 SOC1.J7 SOC1.K7 U2901.15
VREG_L11A_1P0V: C819.1 PMIC1.M2 R3009.1 R3011.1
VREG_L12A_0P9V: C820.1 C1926.1 C1927.1 C1928.1 C1929.1 C1931.1 PMIC1.P4 SOC1.K24 SOC1.M25
VREG_L13A_1P8V: C821.1 C1701.1 C1844.1 C1911.1 C1912.1 C1913.1 C1917.1 C1918.1 C1919.1 C1920.1 C1921.1 C1930.1 C1932.1 C1939.1 C1940.1 C2907.1 PMIC1.W13 SOC1.AD10 SOC1.AD11 SOC1.AD13 SOC1.K8 SOC1.L25 SOC1.M24 SOC1.P15 SOC1.P19 SOC1.T25 SOC1.W14 SOC1.Y16 U2901.39
VREG_L14A_1P8V: C822.1 C2106.1 C2107.1 EMMC1.C6 EMMC1.M4 EMMC1.N4 EMMC1.P3 EMMC1.P5 PMIC1.Y12
VREG_L15A_1P8V: C504.1 C823.1 C824.1 C1101.1 C1103.1 C1829.1 C1833.1 C1834.1 C1835.1 C1836.1 C1837.1 C1838.1 C1839.1 C1840.1 C1841.1 C1842.1 C2217.1 C2218.1 C2219.1 C2220.1 C2514.1 C2515.1 C2516.1 C2609.1 C2623.1 C2624.1 C2909.1 D26003.2 D26099.2 DRAM1.F1 DRAM1.F12 DRAM1.G4 DRAM1.G9 DRAM1.T4 DRAM1.T9 DRAM1.U1 DRAM1.U12 JCTL1.9 JMISC1.57 MCU1.A6 MCU1.H12 PMIC1.B22 PMIC1.V8 R1101.1 R1102.1 R1303.1 R1305.1 R1307.1 R1309.1 R1311.1 R1313.1 R1315.1 R1317.1 R1319.1 R2114.1 R2605.2 R2606.2 R2609.2 R2610.2 R3010.1 R3012.1 SOC1.AA7 SOC1.AC17 SOC1.AC18 SOC1.AC23 SOC1.AD18 SOC1.AF17 SOC1.F11 SOC1.F20 SOC1.G24 SOC1.G26 SOC1.M6 SOC1.N19 SOC1.T26 TP2610.1(TP) U1101.1 U1102.1 U2901.17
VREG_L16A_1P8V: C825.1 PMIC1.Y10
VREG_L17A_3P0V: C826.1 PMIC1.Y16
VREG_L18A_1P8V: C827.1 PMIC1.Y22
VREG_L19A_1P8V: C828.1 PMIC1.Y20
VREG_L20A_2P96V: C829.1 C2103.1 C2104.1 C2105.1 EMMC1.E6 EMMC1.F5 EMMC1.J10 EMMC1.K9 PMIC1.V16
VREG_L21A_2P96V: C830.1 C1933.1 PMIC1.U13 SOC1.M23
VREG_L22A_3P3V: C831.1 C832.1 C2911.1 C2912.1 PMIC1.V18 U2901.35 U2901.36
VREG_RFCLK: C706.1 PMIC1.V6
VREG_RFCLK2: C705.1 PMIC1.T6
VREG_S1A_0P8V: C1705.1 C1706.1 C1707.1 C1708.1 C1709.1 C1710.1 C1711.1 C1712.1 C1713.1 C1714.1 C1715.1 C1716.1 C1717.1 C1718.1 C1719.1 C1720.1 C1721.1 C1722.1 C1723.1 C1724.1 C1725.1 L1001.2 SOC1.AA21 SOC1.AA22 SOC1.AA23 SOC1.AA24 SOC1.AA25 SOC1.AA26 SOC1.R20 SOC1.R22 SOC1.U19 SOC1.U20 SOC1.U21 SOC1.U23 SOC1.W18 SOC1.W19 SOC1.W20 SOC1.W21 SOC1.Y18 SOC1.Y19 SOC1.Y20 SOC1.Y21 SOC1.Y22 SOC1.Y23 SOC1.Y24
VREG_S2A_0P8V: C1801.1 C1802.1 C1803.1 C1804.1 C1805.1 C1806.1 C1807.1 C1808.1 C1809.1 C1810.1 C1811.1 C1812.1 C1813.1 C1814.1 C1815.1 C1816.1 C1817.1 C1818.1 C1819.1 C1820.1 C1821.1 C1822.1 C1823.1 L1002.2 SOC1.K11 SOC1.K12 SOC1.K13 SOC1.K14 SOC1.K15 SOC1.K16 SOC1.K17 SOC1.K18 SOC1.K22 SOC1.M19 SOC1.N9 SOC1.N11 SOC1.N13 SOC1.N15 SOC1.N17 SOC1.R9 SOC1.R10 SOC1.R11 SOC1.R12 SOC1.R13 SOC1.R15 SOC1.R16 SOC1.R17 SOC1.T10 SOC1.T19 SOC1.Y8 SOC1.Y9 SOC1.Y10 SOC1.Y11 SOC1.Y12 SOC1.Y13
VREG_S3A_1P352V: C801.1 C802.1 C803.1 C804.1 C1005.1 C1006.1 C1007.1 C1008.1 L1003.2 PMIC1.A15 PMIC1.E11 PMIC1.G5 PMIC1.K4 PMIC1.N5
VREG_S4A_2P04V: C505.1 C506.1 C805.1 C1009.1 C1010.1 C1011.1 C1012.1 L1004.2 PMIC1.A23 PMIC1.G27 PMIC1.J25 PMIC1.U7 PMIC1.V10 PMIC1.V12
VREG_XO: C704.1 PMIC1.U5
VRG_CHG: C610.1 PMIC1.T22
VSNS_S1A_APC_M: PMIC1.E15
VSNS_S1A_APC_P: PMIC1.F16
VSNS_S2A_CX_M: PMIC1.G15
VSNS_S2A_CX_P: PMIC1.F14
VSW_CHG: C609.2 L601.1 PMIC1.W25 PMIC1.Y26
VSW_S1: L1001.1 PMIC1.B18 PMIC1.C17
VSW_S2: L1002.1 PMIC1.B12 PMIC1.C13
VSW_S3: L1003.1 PMIC1.A1 PMIC1.B2
VSW_S4: L1004.1 PMIC1.F2 PMIC1.G3
WCN_RFCLK2: C707.1 R701.1 R2905.1
WCN_RFCLK2_R: R2905.2 U2901.13
WCN_SW_CTRL: SOC1.J1 U2901.5
WL_CLK_OUT: TP2901.1(TP) U2901.21(WL_CLK_OUT)
WL_CMD_CLK: SOC1.K4 U2901.37
WL_CMD_DATA: SOC1.L4 U2901.38
WLAN0_DAC_RSET: R1602.2 SOC1.G2
WLAN_BT_COEX_CLK: SOC1.L5 U2901.18
WLAN_BT_COEX_DATA: SOC1.M5 U2901.19
WLAN_RX_I_M: C1602.1 SOC1.A3 U2901.32
WLAN_RX_I_P: C1601.1 SOC1.A2 U2901.33
WLAN_RX_Q_M: C1604.1 SOC1.B1 U2901.23
WLAN_RX_Q_P: C1603.1 SOC1.C1 U2901.24
WLAN_TX_I_M: C2921.1 SOC1.H4 U2901.29
WLAN_TX_I_P: C2922.1 SOC1.G4 U2901.30
WLAN_TX_Q_M: C2924.1 SOC1.G3 U2901.26
WLAN_TX_Q_P: C2923.1 SOC1.H3 U2901.27
WLAN_XO_CLK: C720.2 C721.1 SOC1.K3(WLAN_XO_CLK)
XO_THERM: C703.1 PMIC1.R7 Y701.4
XOADC_GND: C703.2 PMIC1.P8 Y701.2
N20480751: PMIC1.M24 R607.2
N20518421: C1106.1 R1102.2 U1102.5
N20519216: C1105.1 R1101.2 U1101.12

Pads without a net: DRAM1 A1 A2 A11 A12 AA1 AA12 AB1 AB2 AB11 AB12 B1 B12 G11 K5 K8 N5 N8; EMMC1 A1 A2 A7 A8 A9 A10 A11 A12 A13 A14 B1 B7 B8 B9 B10 B11 B12 B13 B14 C1 C3 C5 C7 C8 C9 C10 C11 C12 C13 C14 D1 D2 D3 D4 D12 D13 D14 E1 E2 E3 E5 E8 E9 E10 E12 E13 E14 F1 F2 F3 F10 F12 F13 F14 G1 G2 G3 G10 G12 G13 G14 H1 H2 H3 H12 H13 H14 J1 J2 J3 J12 J13 J14 K1 K2 K3 K6 K7 K10 K12 K13 K14 L1 L2 L3 L12 L13 L14 M1 M2 M3 M7 M8 M9 M10 M11 M12 M13 M14 N1 N3 N6 N7 N8 N9 N10 N11 N12 N13 N14 P1 P2 P7 P8 P9 P10 P11 P12 P13 P14; MCU1 A5 A9 A12 B7 B9 B12 C4 C8 C9 D4 D7 D8 D10 D11 D12 E3 E7 E8 E9 E10 E11 F8 F9 F10 G11 H5 H7 H8 H11 J6 J7 J8 J10 J11 K6 K8 K11 K13 L4 L8 L10 M1 M4 M6 M8 M9 M10 M13 N8 N9; PMIC1 A7 B6 B8 E7 E9 F4 F6 F8 G7 G11 G25 H8 H22 J23 K22 M22 N21 N23 R15; QWIIC1 5 6; SOC1 A1 A15 A30 AA1 AA2 AA3 AA4 AA5 AB1 AB4 AB5 AB27 AC5 AC25 AC26 AD1 AE3 AE4 AE5 AE6 AE13 AE14 AE21 AE23 AE24 AE25 AE26 AE27 AE28 AF2 AF6 AF13 AF14 AF21 AF23 AF24 AF25 AF26 AF27 AF28 AG6 AG21 AG25 AG27 AH5 AH7 AH11 AH12 AH13 AH15 AH16 AH17 AH20 AH21 AH24 AH25 AH28 AH29 AJ1 AJ4 AJ5 AJ8 AJ10 AJ11 AJ13 AJ14 AJ25 AJ28 AJ30 B15 C15 C16 D15 D30 E29 F16 F17 F28 G16 G25 J24 K2 L26 M3 U7 W1 W2 W3 W4 W28 Y2 Y3; U2501 1; U2604 3 4 5; U2803 5; U3001 G2 G3 G4 G5 G6 H2 H3; U3004 4

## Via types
v1: diameter 0.2, hole 0.1, TOP to G2, 2859 vias
v2: diameter 0.2, hole 0.1, G2 to S3, 2360 vias
v3: diameter 0.35, hole 0.2, S3 to S6, 849 vias
v4: diameter 0.2, hole 0.1, S6 to G7, 1423 vias
v5: diameter 0.2, hole 0.1, G7 to BOTTOM, 2091 vias
v6: diameter 0.406, hole 0.203, TOP to BOTTOM, 224 vias

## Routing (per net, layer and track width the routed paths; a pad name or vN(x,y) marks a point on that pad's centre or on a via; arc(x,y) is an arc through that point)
5V_BUCK_BOOT: length 0.9
  TOP w0.254: U2803.4 10.3,43.29 C2813.2
5V_BUCK_EN: length 1.6
  TOP w0.254: R2812.1 5.72,43.27 R2811.2 5.74,43.29 U2803.9
5V_BUCK_FB: length 2.1
  TOP w0.254: U2803.7 6.67,44.3 R2814.2 6.19,45.23 C2814.2 R2815.1
5V_BUCK_FB_C: length 0.6
  TOP w0.254: R2816.2 6.18,45.84 C2814.1
5V_BUCK_OUT: length 1.5
  TOP w0.254: R2814.1 7.18,45.24 R2816.1 7.18,46.74
  vias: v1(6.43,47.46) v1(6.43,47.23) v1(6.43,47) v1(6.67,47.46) v1(6.67,47.23) v1(6.67,47) v1(6.91,47.46) v1(6.91,47.23) v1(6.91,47) v2(6.43,47.46) v2(6.43,47.23) v2(6.43,47) v2(6.67,47.46) v2(6.67,47.23) v2(6.67,47) v2(6.91,47.46) v2(6.91,47.23) v2(6.91,47) v3(7.04,48.15) v3(7.04,47.77) v3(7.42,48.15) v3(7.42,47.77) v4(6.99,49.02) v4(7,48.78) v4(7,48.52) v4(7.23,49.02) v4(7.24,48.78) v4(7.24,48.52) v4(7.48,49.01) v4(7.49,48.77) v4(7.49,48.51) v5(6.99,49.02) v5(7,48.78) v5(7,48.52) v5(7.23,49.02) v5(7.24,48.78) v5(7.24,48.52) v5(7.48,49.01) v5(7.49,48.77) v5(7.49,48.51)
5V_BUCK_RT: length 0.9
  TOP w0.254: R2813.1 9.45,44.3 U2803.6
5V_BUCK_VIN:
  vias: v1(1.64,47.86) v1(1.64,47.63) v1(1.64,47.4) v1(1.91,47.86) v1(1.91,47.63) v1(1.91,47.4) v1(2.2,47.86) v1(2.2,47.63) v1(2.2,47.4) v2(1.64,47.86) v2(1.64,47.63) v2(1.64,47.4) v2(1.91,47.86) v2(1.91,47.63) v2(1.91,47.4) v2(2.2,47.86) v2(2.2,47.63) v2(2.2,47.4) v3(1.71,48.65) v3(1.71,48.25) v3(2.11,48.65) v3(2.11,48.25) v4(1.7,49.46) v4(1.7,49.23) v4(1.69,49) v4(1.94,49.46) v4(1.94,49.23) v4(1.93,49) v4(2.18,49.46) v4(2.18,49.23) v4(2.17,49) v5(1.7,49.46) v5(1.7,49.23) v5(1.69,49) v5(1.94,49.46) v5(1.94,49.23) v5(1.93,49) v5(2.18,49.46) v5(2.18,49.23) v5(2.17,49)
5V_SYS: length 3.6
  BOTTOM w0.2: 12.19,40.04 12.19,40.24 13.02,41.07 13.02,43.01 13.19,43.18
5V_USB_VBUS: length 107.5
  TOP w0.203: D26017.2 38.67,5.25 ; 38.67,5.25 C2611.1 39.64,5.25 40.21,5.82 48.29,5.82 49.09,5.01 v6(49.12,5.01) ; 38.67,5.25 37.28,5.25 37.01,4.98 33.1,4.98 JSPI1.2 ; v2(36.7,63.34) v2(36.7,63.13) 36.72,63.1 JUSB1.B4 36.72,61.94 36.47,61.69 JUSB1.A9 ; v2(43.33,64.62) 39.85,64.62 39.22,63.99 v2(39.22,63.4) v2(39.22,63.14) ; JUSB1.A4 38.97,61.57 v2(39,61.6) 38.97,61.63 38.97,61.68 39.22,61.93 v2(39.22,63.14) ; v2(39.22,63.13) JUSB1.B9
  TOP w0.254: U2604.6 41.48,58.06 v2(41.58,58.06)
  S3 w0.304: v2(43.33,64.62) 43.54,64.62 43.56,64.59
  S3 w0.5: v2(41.58,58.06) 41.58,58.15 43.56,60.13 43.56,64.59
  V4 w0.203: 3.59,30.48 JANALOG1.5 2.54,31.53
  S6 w0.254: v6(49.12,5.01) 48.44,5.7 48.44,14.05
  S6 w1: 48.44,14.05 48.44,39.77 48.94,40.27 48.94,51.03 48.44,51.53 48.44,61.03 44.85,64.62 v3(44.22,64.62)
  BOTTOM w0.203: 6.69,30.63 6.68,30.62 C2617.1
  BOTTOM w0.5: JANALOG1.5 2.69,30.63 v5(5.97,30.63) 6.69,30.63
  vias: v1(30.59,64.2) v1(30.74,64.05) v1(30.88,63.88) v1(36.44,61.59) v1(36.44,61.34) v1(36.44,61.09) v1(39,61.4) v1(39,61.19) v1(43.17,64.46) v1(43.49,64.78) v2(30.59,64.2) v2(30.74,64.05) v2(30.88,63.88) v2(36.44,61.59) v2(36.44,61.34) v2(36.44,61.09) v2(39,61.4) v2(39,61.19) v2(43.17,64.46) v2(43.49,64.78) v3(5.71,9.83) v3(5.72,9.3) v3(5.72,8.94) v3(5.77,46.26) v3(5.77,45.84) v3(5.96,9.57) v3(15.24,43.87) v3(15.24,43.43) v3(15.24,43.03) v3(31.08,66.15) v3(31.23,66.52) v3(31.48,66.16) v3(44.01,64.32) v3(44.37,64.3) v4(5.63,8.67) v4(5.84,8.67) v4(5.77,8.47) v4(6,8.47) v4(6.06,8.67) v4(6.23,8.47) v4(6.31,8.67) v4(6.55,8.67) v4(6.47,8.47) v4(6.72,8.47) v4(6.85,52.21) v4(6.85,51.99) v4(6.85,51.78) v4(7.12,52.21) v4(7.12,51.99) v4(7.12,51.78) v4(7.37,52.21) v4(7.37,51.99) v4(7.37,51.78) v5(6.85,52.21) v5(6.85,51.99) v5(6.85,51.78) v5(7.12,52.21) v5(7.12,51.99) v5(7.12,51.78) v5(7.37,52.21) v5(7.37,51.99) v5(7.37,51.78) v5(10.92,10.84) v5(10.91,10.56) v5(11.18,10.84) v5(11.17,10.56) v5(11.44,10.84) v5(11.43,10.56) v5(11.71,10.84) v5(11.7,10.56) v5(11.98,10.84) v5(11.97,10.56)
5V_USB_VBUS_ON_N: length 3.1
  BOTTOM w0.203: R2809.2 15.2,47.3 Q2801.1 15.77,47.81 Q2802.3
AVDD1P0V: length 16.1
  TOP w0.203: U3001.C6 36.57,53.14 v2(36.17,53.14)
  TOP w0.254: U3001.A4 v2(35.77,54.18) 35.66,54.29 35.66,54.84 36.56,55.73 C3012.1 36.65,55.73 C3011.1 37.24,55.73 C3010.1
  S3 w0.203: v3(35.99,53.93) 35.99,53.96 v2(35.77,54.18) ; v2(36.2,51.97) 36.2,52.02 35.84,52.37 v3(35.84,52.4) ; v2(36.25,46.99) 36,47.24 v3(35.93,47.24) ; v2(36.17,53.14) v3(36.47,53.14)
  V4 w0.203: 36.88,51.92 36.32,51.92 v3(35.84,52.4) ; v3(36.47,53.14) 36.75,53.14 36.88,53.01
  V4 w0.524: v3(35.93,47.24) 36.9,47.24 38.38,48.72 38.38,49.78 36.88,51.28 36.88,53.01
  V5 w0.524: v3(36.47,53.14) 35.99,53.62 v3(35.99,53.93)
AVDD1P8V: length 30.5
  TOP w0.203: v2(28.13,62.59) 27.88,62.84 26.36,62.84 25.7,62.18 R3024.1 ; U3001.E3 v2(35.37,52.17) v2(35.37,51.94)
  S3 w0.203: v3(35.37,51.64) v2(35.37,51.94) v2(35.37,52.17) ; v3(33.48,47.12) 33.48,46.72 v2(33.34,46.58) ; v3(28.33,62.36) 28.33,62.39 v2(28.13,62.59)
  V4 w0.524: v3(28.33,62.36) 30.2,62.36 31.02,61.54 31.02,56.67 32.7,54.99 32.7,53.27 33.91,52.06 33.91,47.55 v3(33.48,47.12)
  S6 w0.203: v3(35.37,51.64) 35.37,51.18 35.18,50.99 v5(35.05,50.99)
  S6 w0.254: v5(33.22,47.4) 33.48,47.14 v3(33.48,47.12)
  BOTTOM w0.203: v5(35.05,50.99) C3009.1 C3008.1 34.64,50.48 C3007.1
  BOTTOM w0.254: v5(33.22,47.4) 33.81,47.98 33.81,50 34.35,50.54 C3007.1
AVDD3P0V: length 8.5
  TOP w0.203: C3001.1 35.16,55.68 C3002.1 35.72,55.68 v2(35.73,55.68)
  S3 w0.203: v3(35.64,54.99) 35.73,55.08 v2(35.73,55.68) 35.99,55.95 35.99,55.99 v3(36.01,56.01) ; v2(35.74,53.19) 35.74,53.04 35.84,52.93 v3(35.84,52.91)
  S6 w0.203: v3(36.01,56.01) 36.2,56.2 v5(36.2,56.29) ; v3(35.84,52.91) 35.36,53.39 35.36,54.71 v3(35.64,54.99)
  BOTTOM w0.5: v5(33.17,56.52) 35.97,56.52 v5(36.2,56.29)
  vias: v1(32.08,56.74) v1(32.08,56.52) v1(32.31,56.74) v1(32.31,56.52) v2(32.08,56.74) v2(32.08,56.52) v2(32.31,56.74) v2(32.31,56.52) v3(32.59,56.67) v3(32.87,56.44) v4(32.87,56.72) v4(33.1,56.72) v4(33.35,56.67) v4(35.97,56.29) v4(36.3,56.08) v5(32.87,56.72) v5(33.1,56.72) v5(33.35,56.67) v5(35.97,56.29) v5(36.3,56.08)
DVDD1P0V: length 1.5
  TOP w0.203: U3001.E5 36.37,52.34 36.45,52.43 v2(36.47,52.43) 36.56,52.34 U3001.E6 36.58,52.34 36.58,52.74 v2(36.57,52.74)
  S3 w0.203: v2(36.57,52.74) 36.46,52.63 v3(36.27,52.63) v2(36.47,52.43)
  vias: v4(37.11,51.77) v4(37.11,51.54) v5(37.11,51.77) v5(37.11,51.54)
DVDD1P8V: length 17.8
  TOP w0.203: v2(35.89,44.3) 33.5,44.3 33.24,44.04 R3027.1 R3026.1 ; v2(39.23,54.52) 39.22,54.51 R3025.1
  S3 w0.203: v2(35.74,51.92) 35.92,51.74 v3(35.92,51.61) ; v3(35.45,45.91) 35.89,45.46 v2(35.89,44.3) ; v2(39.23,54.52) 39.23,54.31 39.21,54.29 v3(39.21,54.24)
  S6 w0.203: v3(35.45,45.91) 35.1,45.91 v5(34.71,46.3)
  S6 w0.254: v3(39.21,54.24) 38.77,54.24 37.72,53.19 37.26,53.19 v5(37.24,53.16)
  BOTTOM w0.203: v5(36.14,51.21) 36.14,52.07 36.85,52.78 ; 36.85,52.78 C3015.1 ; 36.85,52.78 v5(37.24,53.16)
  BOTTOM w0.254: v5(34.71,46.3) 34.56,46.45 34.56,47.27 36.39,49.1 R3012.2
  vias: v4(36.42,51.21) v5(36.42,51.21)
GND: length 1201.3
  TOP w0.051: v1(23.17,33.05) 22.82,33.05 22.32,32.55 22.32,25.81 22.69,25.44 22.69,23.13 22.78,23.04 22.78,20.55 22.28,20.05 22.28,18.78 23.77,17.29 23.77,14.89 v2(23.86,14.8) ; 28.8,28.07 28.8,28.65 v1(28.57,28.88) ; v2(23.66,13.82) 23.16,14.32 23.16,16.95 21.69,18.42 21.69,24.54 v1(21.99,24.84) 21.83,25 21.83,32.76 22.77,33.7 v1(23.28,33.7) ; v1(29.37,28.88) 29.11,28.62 29.11,28.04 ; v1(31.49,41.17) 30.75,41.91 21.88,41.91 v1(21.35,41.38) ; v1(21.26,40.7) 21.42,40.7 22.3,41.58 30.32,41.58 v1(31.05,40.85)
  TOP w0.064: v2(36.4,11.34) 36.42,11.34 36.42,11.37 36.45,11.37 36.45,11.35 36.46,11.37 36.46,11.52 C823.2 ; PMIC1.J17 38.69,16.55 v2(38.83,16.55) ; v1(35.37,38.88) SOC1.A4 36.26,39.78 36.26,41.05
  TOP w0.084: v2(43.16,31.29) 43.13,31.29 DRAM1.T8
  TOP w0.1: 40.46,63.25 40.72,62.99 v2(40.72,62.53) ; SOC1.T22 SOC1.R23
  TOP w0.125: v1(34.17,34.08) v1(34.57,33.68) 34.97,34.08 ; v2(32.57,38.08) v1(32.57,38.48) ; v1(28.57,28.88) v2(28.97,29.28) 29.37,28.88 v1(29.37,28.88) v1(29.77,28.88) v2(30.17,29.28) v2(29.77,29.68) v2(30.17,30.08) ; v1(35.37,29.68) 35.37,29.68 35.7,29.35 ; v1(34.17,29.68) v1(34.57,30.08) v1(34.97,29.68) ; v2(31.37,37.68) v2(31.37,38.08) ; v2(31.77,38.08) v1(31.77,38.48) ; v1(35.37,33.68) v1(35.37,34.08) ; v1(33.37,38.08) v1(33.37,38.48) v1(33.37,38.88) ; v1(32.97,29.28) v2(33.37,29.68) ; v1(32.17,38.48) v2(32.17,38.08) ; 31.37,29.68 SOC1.M26 v2(30.97,30.08) ; v2(31.77,30.48) 31.37,30.88 ; v1(34.57,38.48) v1(34.97,38.88)
  TOP w0.15: v1(32.97,35.68) 32.97,36.08 SOC1.G11 ; 32.17,32.15 32.64,32.15 32.97,32.47 32.97,32.48 ; v1(34.57,34.88) 34.52,34.88 v2(34.36,34.72) 34.36,34.72 34.33,34.72 v1(34.17,34.88) ; v2(35.1,34.2) 34.98,34.08 SOC1.B16 34.97,34.08
  TOP w0.2: v1(33.77,29.68) v1(34.17,29.68) ; v1(33.77,29.68) v1(33.77,30.08) v2(33.37,30.08) ; v1(33.77,29.68) v2(33.37,29.68) v2(33.37,30.08) ; v2(26.57,36.88) v2(26.17,36.88) ; v2(26.57,36.88) v2(26.97,36.88) ; v2(26.57,36.88) v2(26.57,37.28) ; v2(26.57,36.88) SOC1.AC10 SOC1.AC12 ; v2(26.17,36.88) v2(25.77,36.88) ; v2(26.17,36.88) v2(26.17,37.28) ; v2(28.97,36.48) 28.97,36.08 ; 28.97,36.08 v2(29.37,36.08) v2(29.37,35.28) ; 28.97,36.08 SOC1.U11 ; 28.97,36.08 v2(28.97,35.28) ; v1(34.97,39.28) 34.97,39.68 v2(34.57,39.68) ; v1(34.97,39.28) v1(34.97,38.88) v1(35.37,38.88) ; v1(34.97,39.28) v1(34.57,39.28) ; v2(33.37,37.28) SOC1.G8 v1(32.97,37.28) ; v2(33.37,37.28) v2(33.37,37.68) v1(33.37,38.08) v2(32.97,38.08) ; v2(33.37,37.28) v1(33.37,36.88) ; v2(25.77,36.08) v2(25.77,35.68) ; v2(25.77,36.08) v2(25.77,36.48) ; v2(25.77,36.08) v2(25.37,36.08) ; v2(25.77,35.68) v2(26.17,35.68) SOC1.AC12 ; v2(25.77,35.68) v2(25.37,35.68) ; v2(30.57,38.48) v2(30.17,38.48) ; v2(30.17,38.48) v2(30.17,38.08) ; v2(30.17,38.48) v1(30.17,38.88) ; v2(30.17,38.48) v2(29.77,38.48) ; v2(26.17,37.28) v2(25.77,37.28) ; v2(26.17,37.28) v2(26.57,37.28) ; v2(26.17,37.28) v2(26.17,37.68) ; v2(25.77,37.28) v2(25.77,37.68) ; v2(25.77,37.28) v2(25.37,37.28) ; v2(25.77,37.28) v2(25.77,36.88) ; v2(28.17,30.08) v2(27.77,30.08) v1(27.77,29.68) v2(28.17,29.68) v2(28.17,30.08) ; v2(28.17,30.08) v2(28.17,30.88) ; v2(28.17,30.08) v2(28.57,30.08) ; 24.97,33.68 24.97,34.08 ; 24.97,34.08 v2(24.97,34.48) ; 24.97,34.08 25.37,34.08 ; v2(28.17,30.88) v2(28.57,30.88) ; v2(28.17,30.88) v1(28.17,31.28) ; PMIC1.W7 35.86,13 35.35,12.49 v1(35.35,12.04) ; v2(37.84,16.26) v2(38.12,15.98) v2(38.41,15.7) v1(38.69,15.98) ; v2(37.84,16.26) PMIC1.J15 PMIC1.K16 PMIC1.J17 v1(38.97,16.26) ; v2(37.84,16.26) v2(37.56,15.98) v1(37.28,15.7) ; v2(37.84,16.26) v2(37.56,16.55) ; PMIC1.R21 v2(40.11,15.13) ; v1(33.77,39.28) v2(34.17,39.28) ; v1(33.77,39.28) SOC1.F3 v1(33.37,39.28) ; v1(33.77,39.28) v1(33.77,39.68) ; v1(33.77,39.28) v1(33.77,38.88) v1(33.37,38.88) v1(33.37,39.28) ; v2(34.17,39.28) v2(34.17,39.68) ; v2(34.17,39.28) v1(34.57,39.28) ; SOC1.AA20 v2(27.37,32.88) v2(27.37,33.28) v1(27.37,33.68) v2(27.37,34.08) SOC1.AC16 ; v2(25.77,36.88) v2(25.37,36.88) ; v2(25.77,36.88) v2(25.77,36.48) ; v2(25.37,36.88) v2(24.97,36.88) ; v2(25.37,36.88) v2(25.37,37.28) ; v2(25.37,36.88) v2(25.37,36.48) ; 28.97,34.48 SOC1.V15 v1(28.57,34.08) SOC1.V17 ; 28.97,34.48 28.97,33.68 ; 28.97,34.48 v2(28.97,35.28) ; 28.97,34.48 v2(29.37,34.48) ; v2(26.97,36.88) 26.97,37.28 ; v2(26.97,36.88) v1(27.37,36.88) ; v2(28.97,38.48) v1(28.97,38.88) ; v2(28.97,38.48) v2(29.37,38.48) ; v2(28.97,38.48) v2(28.57,38.48) ; v2(28.97,38.48) v2(28.97,38.08) ; v1(31.77,30.08) v2(32.17,30.08) ; v1(31.77,30.08) v2(31.77,30.48) v2(32.17,30.48) ; v1(31.77,30.08) v2(31.77,29.68) 31.37,29.68 v1(31.37,29.28) v1(31.37,28.88) ; v2(32.17,30.08) v2(32.17,30.48) ; v2(32.17,30.08) v1(32.57,30.08) SOC1.H25 ; v1(30.97,37.68) v2(30.57,37.68) ; v1(30.97,37.68) SOC1.M7 v2(31.37,37.68) 31.37,37.28 SOC1.M8 v2(30.97,37.28) ; v1(30.97,37.68) v2(30.97,37.28) ; v2(30.57,37.68) v2(30.17,37.68) ; v2(30.57,37.68) v1(30.57,37.28) ; SOC1.T22 v2(29.37,32.48) ; v2(30.97,37.28) v1(30.57,37.28) ; v1(30.57,37.28) v2(30.17,37.28) ; SOC1.V17 v1(28.57,33.28) v2(28.57,32.88) v2(28.57,32.08) v2(28.57,31.28) ; SOC1.V17 28.97,33.68 ; SOC1.H25 v1(32.57,30.88) 32.57,31.1 32.17,31.5 v2(32.17,31.68) v2(32.17,32.48) ; SOC1.H25 v2(32.17,30.48) ; v2(25.37,37.28) v1(25.37,37.68) ; v2(25.37,37.28) SOC1.AG8 v2(24.97,37.28) ; v1(25.37,37.68) v1(24.97,37.68) 24.97,37.68 v2(24.97,37.28) ; v1(25.37,37.68) v2(25.77,37.68) ; v1(32.17,38.48) v1(31.77,38.48) ; v1(32.17,38.48) v1(32.17,38.88) v1(32.17,39.28) v1(32.17,39.68) ; v1(32.17,38.48) v1(32.57,38.48) v1(32.97,38.48) ; v2(24.97,34.48) v2(25.37,34.48) v2(25.77,34.48) v2(26.17,34.48) ; v2(24.97,34.48) v2(24.97,34.88) v2(24.97,35.28) v2(24.97,35.68) ; v1(28.17,31.28) v2(28.57,31.28) ; v1(28.17,31.28) v2(28.17,31.68) ; v2(28.57,31.28) v2(28.57,30.88) ; v2(29.77,38.08) v2(29.37,38.08) ; v2(29.77,38.08) v2(30.17,38.08) ; v2(29.77,38.08) v2(29.77,38.48) ; v2(29.37,38.08) v2(28.97,38.08) ; v2(29.37,38.08) v2(29.37,38.48) ; v2(24.97,37.28) v2(24.97,36.88) ; v2(25.37,35.68) SOC1.AG12 v2(24.97,35.68) ; v2(25.37,35.68) v2(25.37,36.08) ; v2(26.57,34.48) v2(26.17,34.48) ; v2(26.17,34.48) v2(26.17,34.88) ; v2(25.77,36.48) v2(25.37,36.48) ; v1(33.77,39.68) v2(34.17,39.68) ; v1(33.77,39.68) SOC1.F2 v1(33.37,39.68) v1(33.37,39.28) ; v2(34.17,39.68) v1(34.17,40.08) ; v2(34.17,39.68) v2(34.57,39.68) ; v2(28.57,38.08) v2(28.57,37.68) v2(28.57,37.28) ; v2(28.57,38.08) v2(28.97,38.08) ; v2(28.57,38.08) v2(28.17,38.08) ; v2(28.57,38.08) v2(28.57,38.48) ; 26.97,37.28 SOC1.AB8 v2(27.37,37.28) v1(27.37,36.88) ; 26.97,37.28 v2(26.97,37.68) v2(26.57,37.68) ; 26.97,37.28 v2(26.57,37.28) ; v2(27.37,34.88) v1(26.97,34.88) v2(26.97,35.68) ; SOC1.K10 31.77,36.78 31.64,36.91 31.11,36.91 30.97,36.77 v2(30.97,36.48) v2(30.97,36.08) v2(30.97,35.28) v2(30.97,34.48) v1(30.97,33.68) v2(30.97,33.28) ; v2(27.77,38.48) v1(27.77,38.88) ; v2(27.77,38.48) v2(28.17,38.48) ; v2(27.77,38.48) v2(27.77,38.08) ; v2(30.17,38.08) v2(30.17,37.68) ; v2(30.17,37.28) v2(30.17,36.48) v1(30.17,36.08) v2(30.17,35.68) v1(30.17,35.28) v2(30.17,34.88) ; v2(30.17,37.28) v2(30.17,37.68) ; v2(28.17,38.48) v2(28.17,38.08) ; v2(28.17,38.48) v2(28.57,38.48) ; SOC1.N25 30.17,30.48 v2(30.17,30.08) v1(30.57,30.08) ; v2(29.37,38.48) v2(29.77,38.48) ; 31.37,30.88 31.36,30.89 v2(31.36,31.7) 31.35,31.68 v2(30.97,31.68) 30.92,31.73 v2(30.57,31.73) 30.57,32.08 v2(30.57,32.08) ; v2(24.97,35.68) v2(24.97,36.08) ; v2(28.57,30.88) v2(28.57,30.08) ; v1(34.57,38.48) v1(34.57,38.08) v1(34.57,37.68) v1(34.57,37.28) v1(34.57,36.88) v1(34.57,36.48) v1(34.57,36.08) v1(34.57,35.68) v1(34.57,35.28) v1(34.57,34.88) v1(34.97,34.88) v1(35.37,34.88) v1(35.37,35.28) ; v1(32.97,38.48) v1(33.37,38.48) ; v1(32.97,38.48) v2(32.97,38.08) ; v1(34.57,33.68) v1(34.57,33.28) v1(34.57,32.88) v1(34.57,32.48) v1(34.57,32.08) v1(34.57,31.68) v1(34.57,31.28) v1(34.57,30.88) v1(34.57,30.48) v1(34.57,30.08) ; v2(40.11,17.39) v2(40.39,17.68) ; v2(26.57,37.28) v2(26.57,37.68) ; v2(26.97,35.68) SOC1.AC12 ; v2(26.97,35.68) SOC1.AB12 v2(27.37,35.68) SOC1.AA11 v1(27.37,36.88) ; SOC1.AC12 SOC1.AC13 ; v1(32.57,37.68) v2(32.57,38.08) ; v2(32.57,38.08) v2(32.17,38.08) v2(31.77,38.08) v2(31.37,38.08) ; v2(32.57,38.08) v2(32.97,38.08) ; v1(38.69,15.98) v1(38.97,16.26) ; v1(38.69,15.98) PMIC1.M18 v2(39.26,15.98) ; v1(38.97,16.26) v2(39.26,15.98) ; v1(38.97,16.26) v2(39.26,16.55) ; v2(39.26,15.98) v2(39.54,16.26) ; v2(34.57,39.68) v1(34.57,39.28) ; v2(25.77,37.68) v2(26.17,37.68) ; v1(32.57,29.28) v1(32.97,29.28) ; v2(30.57,30.4) v1(30.57,30.08) ; v1(30.57,30.08) v2(30.97,30.08) ; 28.97,33.68 SOC1.T17 v2(29.37,34.48) ; v2(26.57,37.68) v2(26.17,37.68) ; v2(26.57,37.68) v2(26.57,38.08) ; v2(24.97,36.48) v2(24.97,36.88) ; v2(24.97,36.48) v2(25.37,36.48) ; v2(24.97,36.48) v2(24.97,36.08) ; v2(26.97,30.08) v2(26.97,30.48) v2(26.97,30.88) ; v2(26.97,30.88) v2(26.57,30.88) ; v2(26.97,30.88) v2(26.97,31.28) v2(26.97,31.68) v2(26.57,31.68) v2(26.57,32.08) v2(26.57,32.48) ; 35.41,11.98 35.41,11.54 v1(35.35,11.48) ; 35.41,11.98 v1(35.35,12.04) ; 35.41,11.98 v1(35.35,12.04) ; v2(28.97,35.28) SOC1.U13 v2(29.37,35.28) ; v2(29.37,35.28) v2(29.37,34.48) ; v2(25.37,36.08) v2(25.37,36.48) ; v2(25.37,36.08) v2(24.97,36.08) ; v1(32.17,32.88) v2(31.77,32.88) v2(31.77,32.48) v2(32.17,32.48) ; v1(32.17,32.88) v2(32.17,32.48) ; v1(32.17,32.88) v2(32.17,33.28) v1(32.17,33.68) v2(32.17,34.08) v1(32.17,34.48) v2(32.17,34.88) v1(32.17,35.28) v2(32.17,35.68) ; v1(35.01,18.53) v1(34.73,18.81) ; v2(33.37,30.08) v2(33.37,30.48) ; v1(34.17,34.88) v1(33.77,34.88) v1(33.77,34.08) v1(34.17,34.08) ; v2(28.57,30.08) v1(28.97,30.08) ; v2(27.77,38.08) v2(27.37,38.08) v2(26.57,38.08) ; v2(27.77,38.08) v2(28.17,38.08) ; 28.17,36.48 v2(28.17,36.08) 28.17,35.28 ; v1(33.37,31.28) SOC1.G23 v1(32.97,31.28) ; v2(39.54,16.26) v2(39.26,16.55) ; v2(39.54,16.26) v2(39.82,16.55) v2(39.54,16.83) v2(39.26,16.55) ; 30.17,33.28 30.17,33.68 ; 26.17,38.08 v2(26.57,38.08) ; v1(34.97,29.68) v1(35.37,29.68) ; v2(36.99,18.24) 36.96,18.28 36.96,18.77 v2(36.99,18.81)
  TOP w0.203: 44.51,57.71 v1(44.77,57.71) 44.77,58.02 ; v2(46.26,35.91) 46.26,36.14 ; v2(46.26,35.91) 46.26,35.67 ; v2(46.26,35.91) 46.03,35.91 ; 31.75,10.9 v2(31.98,10.9) ; v2(31.98,10.9) 32.21,10.9 ; v2(31.98,10.9) 31.98,10.67 ; v2(44.66,37.21) 44.66,37.44 ; v2(44.66,37.21) 44.43,37.21 ; v2(44.66,37.21) 44.9,37.21 ; v2(12.85,5.1) 12.85,6.02 ; v2(12.85,5.1) 13.3,5.1 ; v2(12.85,5.1) 12.85,4.17 ; v2(12.85,5.1) 12.4,5.1 ; 45.46,35.02 DRAM1.K11 ; DRAM1.K11 45.23,35.26 ; DRAM1.K11 45.7,35.26 ; DRAM1.K11 45.46,35.49 ; 39.16,9.48 v2(38.93,9.48) 38.71,9.48 ; 41.27,10.68 C608.2 ; C608.2 40.91,11.04 ; C608.2 41.62,11.04 ; C823.2 36.63,11.57 ; C823.2 36.18,11.57 ; C823.2 36.4,11.35 ; PMIC1.V4 34.97,14 34.9,13.93 ; v2(45.46,39.16) 45.46,39.39 ; v2(45.46,39.16) 45.23,39.16 ; v2(45.46,39.16) 45.46,38.92 ; v2(45.46,39.16) 45.7,39.16 ; v1(23.57,57.73) 23.57,58.03 ; v1(23.57,57.73) 23.57,57.42 ; v1(23.57,57.73) 23.88,57.73 ; 8.64,45.16 v2(8.95,45.16) ; v2(8.95,45.16) 8.95,45.46 ; v2(8.95,45.16) 8.95,44.86 ; v2(28.53,19.58) 28.76,19.58 ; v2(28.53,19.58) 28.53,19.81 ; v2(28.53,19.58) 28.53,19.35 ; 41.2,9.82 C601.2 ; C601.2 41.2,10.52 ; C601.2 41.56,10.17 ; 32.44,14.43 v1(32.44,14.66) ; v1(32.44,14.66) 32.44,14.88 ; v1(32.44,14.66) 32.21,14.66 ; v2(44.71,42.93) 44.71,43.24 ; v2(44.71,42.93) 44.97,42.93 ; v2(44.71,42.93) 44.71,42.62 ; 21.99,25.07 v1(21.99,24.84) 21.76,24.84 ; 38.41,20.62 C1001.2 38.63,20.85 ; 44.33,16.84 v1(44.33,17.06) ; v1(44.33,17.06) 44.56,17.06 ; v1(44.33,17.06) 44.33,17.29 ; 31.85,66.66 v2(31.85,67.21) ; v2(31.85,67.21) 32.4,67.21 ; v2(31.85,67.21) 31.85,67.76 ; v2(31.85,67.21) 31.3,67.21 ; 32.44,14.94 C819.2 32.21,15.16 ; v2(12.76,62.5) 13.16,62.5 ; v2(12.76,62.5) 12.36,62.5 ; v2(12.76,62.5) 12.76,62.1 ; v2(12.76,62.5) 12.76,62.9 ; v1(18.06,49.94) 18.06,50.24 ; v1(18.06,49.94) 17.76,49.94 ; v1(18.06,49.94) 18.06,49.63 ; v1(26.91,26.85) 26.91,27.08 ; v1(26.91,26.85) 27.14,26.85 ; v1(26.91,26.85) 26.91,26.62 ; v2(40.66,27.46) 40.9,27.46 ; v2(40.66,27.46) 40.43,27.46 ; v2(40.66,27.46) 40.66,27.22 ; 32.21,13.64 v1(32.44,13.64) ; v1(32.44,13.64) 32.44,13.87 ; v1(32.44,13.64) 32.44,13.41 ; 42.24,20.95 C808.2 ; C808.2 42.24,21.75 ; C808.2 42.6,21.35 ; 36.12,10.49 v2(35.89,10.49) 35.66,10.49 ; 38.03,29.41 v2(38.26,29.41) 38.26,29.64 ; 12.85,6.58 v1(13.16,6.58) 13.16,6.27 ; 34.68,61.23 v2(34.97,61.23) ; v2(34.97,61.23) 34.97,60.61 ; v2(34.97,61.23) 34.97,61.86 ; JDIGITAL1.15 50.8,43.21 ; JDIGITAL1.15 50.8,41.11 ; JDIGITAL1.15 49.75,42.16 ; JDIGITAL1.15 51.85,42.16 ; 40.72,61.91 v2(40.72,62.53) 41.01,62.53 ; 43.63,29.41 v2(43.86,29.41) 43.86,29.64 ; 44.93,45 JCTL1.1 48.34,45 ; v1(4.59,44.34) 4.59,44.77 ; v1(4.59,44.34) 5.02,44.34 ; v1(4.59,44.34) 4.16,44.34 ; U3001.D3 35.37,52.74 v1(35.77,52.74) ; C604.2 47.16,12.35 ; C604.2 47.51,12 ; C604.2 47.16,11.65 ; 40.66,29.82 v1(40.66,30.06) ; v1(40.66,30.06) 40.43,30.06 ; v1(40.66,30.06) 40.9,30.06 ; 15.06,47.57 C2816.2 ; C2816.2 15.49,48 ; C2816.2 15.92,47.57 ; JANALOG1.7 2.54,26.45 ; JANALOG1.7 2.54,24.35 ; JANALOG1.7 3.59,25.4 ; v2(48.55,57.17) 48.55,57.47 ; v2(48.55,57.17) 48.55,56.87 ; v2(48.55,57.17) 48.86,57.17 ; 50.85,58.54 v2(51.65,58.54) ; v2(51.65,58.54) 51.65,59.29 ; v2(51.65,58.54) 51.65,57.79 ; v2(51.65,58.54) 52.45,58.54 ; 43.86,38.92 v2(43.86,39.16) 43.63,39.16 ; JUSB1.S1 42.17,63.06 ; JUSB1.S1 42.82,61.86 ; JUSB1.S1 42.17,60.66 ; 33.83,63.06 JUSB1.S4 34.68,62.36 ; 30.71,14.93 v2(30.71,15.16) ; v2(30.71,15.16) 30.48,15.16 ; v2(30.71,15.16) 30.94,15.16 ; 43.06,37.44 v2(43.06,37.21) 43.3,37.21 ; v2(31.37,14.51) 31.37,14.74 ; v2(31.37,14.51) 31.14,14.51 ; v2(31.37,14.51) 31.37,14.29 ; JANALOG1.6 2.54,28.99 ; JANALOG1.6 2.54,26.89 ; JANALOG1.6 3.59,27.94 ; v2(29.77,64.05) 29.77,64.48 ; v2(29.77,64.05) 29.77,63.62 ; v2(29.77,64.05) 29.34,64.05 ; 13.46,51.71 v1(13.86,51.71) ; v1(13.86,51.71) 13.86,51.31 ; v1(13.86,51.71) 14.26,51.71 ; v1(13.86,51.71) 13.86,52.11 ; 33.87,20.28 C806.2 ; C806.2 34.22,19.88 ; C806.2 34.22,20.68 ; v1(14.78,49.94) 14.78,50.24 ; v1(14.78,49.94) 14.48,49.94 ; v1(14.78,49.94) 14.78,49.63 ; 20.88,61 v1(21.28,61) ; v1(21.28,61) 21.68,61 ; v1(21.28,61) 21.28,60.6 ; 40.59,11.3 v2(40.59,11.53) ; v2(40.59,11.53) 40.59,11.76 ; v2(40.59,11.53) 40.82,11.53 ; DRAM1.AB3 39.06,27.69 ; DRAM1.AB3 38.83,27.46 ; DRAM1.AB3 39.06,27.22 ; DRAM1.AB3 39.3,27.46 ; v1(35.35,11.48) 35.35,11.71 ; v1(35.35,11.48) 35.58,11.48 ; v1(35.35,11.48) 35.35,11.26 ; v2(46.26,37.21) 46.26,37.44 ; v2(46.26,37.21) 46.03,37.21 ; v2(46.26,37.21) 46.26,36.97 ; 43.86,33.31 43.86,33.54 ; 43.86,33.31 43.86,33.07 ; 43.86,33.31 43.63,33.31 ; 43.86,33.31 44.1,33.31 ; 22.47,22.6 v1(22.47,22.37) 22.7,22.37 ; 23.09,39.18 v1(23.09,38.95) 23.32,38.95 ; 36.65,56.55 v1(36.65,56.24) 36.34,56.24 ; 17.16,51.31 v1(17.16,51.71) ; v1(17.16,51.71) 16.76,51.71 ; v1(17.16,51.71) 17.56,51.71 ; v1(17.16,51.71) 17.16,52.11 ; 44.33,16.76 v1(44.33,16.53) 44.56,16.53 ; C811.2 38.03,23.37 ; C811.2 37.63,23.02 ; C811.2 38.43,23.02 ; 29.19,26.16 v1(29.41,26.16) 29.41,25.94 ; 28.21,15.62 C1010.2 ; C1010.2 28.61,15.27 ; C1010.2 29.01,15.62 ; C1804.2 37.48,24.07 ; C1804.2 36.68,24.07 ; C1804.2 37.08,24.42 ; 44.43,35.91 v1(44.66,35.91) 44.66,36.14 ; v1(43.36,59.13) 43.64,59.13 ; v1(43.36,59.13) 43.36,59.43 ; v1(43.36,59.13) 43.36,58.83 ; JUSB1.S2 33.53,63.06 ; JUSB1.S2 33.53,60.66 ; JUSB1.S2 32.87,61.86 ; 39.84,58.45 U2604.7 41.44,58.45 ; v2(28.6,56.57) 28.9,56.57 ; v2(28.6,56.57) 28.3,56.57 ; v2(28.6,56.57) 28.6,56.26 ; 38.46,5.67 v1(38.69,5.67) ; v1(38.69,5.67) 38.92,5.67 ; v1(38.69,5.67) 38.69,5.85 ; C1009.2 30,18.42 ; C1009.2 29.6,18.78 ; C1009.2 29.2,18.42 ; v1(32.59,52.32) 32.51,52.4 C3021.2 ; v2(11.03,57.72) v2(11.03,56.52) ; v2(11.03,57.72) 11.03,58.34 ; v2(11.03,57.72) v2(12.23,57.72) ; v2(11.03,56.52) v2(12.23,56.52) ; v2(11.03,56.52) v2(11.03,55.32) ; v2(11.03,56.52) 10.41,56.52 ; 45.23,33.31 45.46,33.31 ; 45.46,33.31 45.46,33.54 ; 45.46,33.31 45.46,33.07 ; 45.46,33.31 45.7,33.31 ; 43.06,18.74 v1(43.29,18.74) 43.52,18.74 ; 11.43,49.63 v2(11.43,49.94) ; v2(11.43,49.94) 11.43,50.24 ; v2(11.43,49.94) 11.13,49.94 ; 40.23,8.82 C610.2 ; C610.2 40.68,8.82 ; C610.2 40.46,8.59 ; 39.86,38.92 v2(39.86,39.16) ; v2(39.86,39.16) 39.86,39.39 ; v2(39.86,39.16) 39.63,39.16 ; v2(39.86,39.16) 40.1,39.16 ; v1(13.43,56.52) 14.05,56.52 ; v1(13.43,56.52) v2(13.43,55.32) ; v1(13.43,56.52) v2(12.23,56.52) ; v1(13.43,56.52) v2(13.43,57.72) ; 46.26,29.82 v2(46.26,30.06) ; v2(46.26,30.06) 46.26,30.29 ; v2(46.26,30.06) 46.5,30.06 ; 23.7,55.69 v2(23.22,55.69) 22.74,55.69 ; 31.87,14 C716.2 31.41,14 ; DRAM1.E1 37.33,38.51 v2(37.19,38.37) ; v2(44.35,17.59) 44.58,17.59 ; v2(44.35,17.59) 44.35,17.82 ; v2(44.35,17.59) 44.35,17.37 ; 37.73,10.51 v1(37.96,10.51) ; v1(37.96,10.51) 38.18,10.51 ; v1(37.96,10.51) 37.96,10.28 ; v1(33.83,49.35) 34.14,49.35 ; v1(33.83,49.35) 33.53,49.35 ; v1(33.83,49.35) 33.83,49.05 ; 41.73,10.05 v2(41.96,10.05) ; v2(41.96,10.05) 41.96,9.83 ; v2(41.96,10.05) 42.19,10.05 ; v1(39.25,56.85) 39.25,57.28 ; v1(39.25,56.85) 39.73,56.85 ; v1(39.25,56.85) 38.77,56.85 ; 38.94,24.1 C1706.2 ; C1706.2 39.34,24.46 ; C1706.2 39.74,24.1 ; 43.82,42.62 v2(43.82,42.93) 43.82,43.24 ; 25.41,1.32 JSPI1.6 ; JSPI1.6 24.36,2.37 ; JSPI1.6 26.47,2.37 ; 48.55,58.54 v2(49.4,58.54) ; v2(49.4,58.54) 50.25,58.54 ; v2(49.4,58.54) 49.4,57.79 ; v2(49.4,58.54) 49.4,59.29 ; 35.64,24.07 C1803.2 ; C1803.2 36.44,24.07 ; C1803.2 36.04,24.42 ; 30.56,26.16 v1(30.79,26.16) ; v1(30.79,26.16) 31.02,26.16 ; v1(30.79,26.16) 30.79,25.94 ; 22.71,16.43 v1(22.71,16.66) ; v1(22.71,16.66) 22.71,16.89 ; v1(22.71,16.66) 22.94,16.66 ; 31.1,26.16 v1(31.33,26.16) 31.56,26.16 ; v1(34.22,21.23) 34.22,21.63 ; v1(34.22,21.23) 33.87,21.23 ; v1(34.22,21.23) 34.22,20.83 ; 38.73,11.57 v1(38.51,11.57) v1(37.96,11.57) 37.73,11.57 ; 31.37,14.79 v2(31.37,15.02) ; v2(31.37,15.02) 31.14,15.02 ; v2(31.37,15.02) 31.37,15.25 ; 35.85,41.22 v1(35.62,41.22) 35.62,40.99 ; 7.26,51.31 v2(7.26,51.71) ; v2(7.26,51.71) 7.66,51.71 ; v2(7.26,51.71) 6.86,51.71 ; v2(7.26,51.71) 7.26,52.11 ; 42.88,20.89 C713.2 ; C713.2 43.23,21.29 ; C713.2 43.23,20.49 ; 10.16,51.71 v1(10.56,51.71) ; v1(10.56,51.71) 10.56,52.11 ; v1(10.56,51.71) 10.96,51.71 ; v1(10.56,51.71) 10.56,51.31 ; DRAM1.K2 38.5,35.26 ; DRAM1.K2 38.26,35.02 ; DRAM1.K2 38.03,35.26 ; v2(39.55,10.53) 39.78,10.53 ; v2(39.55,10.53) 39.33,10.53 ; v2(39.55,10.53) 39.55,10.31 ; v1(12.98,49.94) 13.28,49.94 ; v1(12.98,49.94) 12.98,49.63 ; v1(12.98,49.94) 12.98,50.24 ; v2(13.43,57.72) 13.43,58.34 ; v2(13.43,57.72) 14.05,57.72 ; v2(13.43,57.72) v2(12.23,57.72) ; v1(6.44,58.8) 6.44,59.2 ; v1(6.44,58.8) 6.84,58.8 ; v1(6.44,58.8) 6.44,58.4 ; v1(6.44,58.8) 6.04,58.8 ; v2(33.25,31.5) 33.25,31.57 33.37,31.68 SOC1.F22 ; v2(8.55,40.12) 9.15,40.12 ; v2(8.55,40.12) 7.95,40.12 ; v2(8.55,40.12) 8.55,39.21 ; v2(8.55,40.12) 8.55,41.03 ; C3022.2 33.38,54.58 33.48,54.69 ; 45.79,17.14 R604.2 45.56,16.91 ; 43.23,22.52 C708.2 ; C708.2 43.23,23.32 ; C708.2 42.88,22.92 ; v2(40.59,11.01) 40.59,11.23 ; v2(40.59,11.01) 40.82,11.01 ; v2(40.59,11.01) 40.59,10.78 ; C710.2 46.1,22.31 ; C710.2 46.1,21.51 ; C710.2 46.45,21.91 ; v2(9.68,49.94) 9.68,50.24 ; v2(9.68,49.94) 9.98,49.94 ; v2(9.68,49.94) 9.68,49.63 ; 20.88,58.8 v1(21.28,58.8) ; v1(21.28,58.8) 21.28,58.4 ; v1(21.28,58.8) 21.28,59.2 ; v1(21.28,58.8) 21.68,58.8 ; C1003.2 31.66,19.78 ; C1003.2 31.66,19.07 ; C1003.2 31.31,19.43 ; 37.62,24.81 C810.2 ; C810.2 38.02,25.17 ; C810.2 38.42,24.81 ; v2(42.94,42.93) 42.94,43.24 ; 34.28,56.19 v1(34.59,56.19) ; v1(34.59,56.19) 34.59,56.5 ; v1(34.59,56.19) 35.16,56.19 v1(35.17,56.19) 35.17,56.49 ; v1(23.09,37.84) 23.32,37.84 ; 40.66,39.57 v2(40.66,39.81) ; v2(40.66,39.81) 40.43,39.81 ; v2(40.66,39.81) 40.9,39.81 ; v2(40.66,39.81) 40.66,40.04 ; JUSB1.S5 42.17,67.91 ; JUSB1.S5 41.41,66.41 ; JUSB1.S5 42.17,64.91 ; JUSB1.S5 42.92,66.41 ; v1(44.29,64.62) 44.29,65.05 ; v1(44.29,64.62) 44.29,64.19 ; v1(44.29,64.62) 44.72,64.62 ; 28.21,18.42 C1011.2 ; C1011.2 28.61,18.78 ; C1011.2 29.01,18.42 ; 8.36,62.1 v2(8.36,62.5) ; v2(8.36,62.5) 8.76,62.5 ; v2(8.36,62.5) 7.96,62.5 ; v2(8.36,62.5) 8.36,62.9 ; v2(12.23,56.52) v2(12.23,55.32) ; v2(12.23,56.52) v2(12.23,57.72) ; v2(12.23,55.32) 12.23,54.7 ; v2(12.23,55.32) v2(11.03,55.32) ; v2(12.23,55.32) v2(13.43,55.32) ; 42.88,21.91 C711.2 ; C711.2 43.23,22.31 ; C711.2 43.23,21.51 ; v1(35.77,52.74) v1(35.77,52.34) ; v1(35.77,52.74) v1(36.17,52.74) ; v2(43.18,17.58) 43.18,17.8 ; v2(43.18,17.58) 43.18,17.35 ; v2(43.18,17.58) 43.41,17.58 ; v2(39.06,35.91) 39.06,36.14 ; 40.02,43.3 v2(39.76,43.3) 39.76,43.61 ; v2(44.66,41.11) 44.9,41.11 ; v2(44.66,41.11) 44.66,41.34 ; v2(44.66,41.11) 44.66,40.87 ; v2(44.66,41.11) 44.43,41.11 ; 42.83,28.76 v2(43.06,28.76) 43.3,28.76 ; 29.75,22.05 v1(29.35,22.05) 28.95,22.05 ; 38.27,10.51 v2(38.5,10.51) 38.73,10.51 ; v1(27.7,12.5) 27.7,12.73 ; v1(27.7,12.5) 27.7,12.27 ; v1(27.7,12.5) 27.47,12.5 ; v1(39.06,41.11) 39.06,41.34 ; v1(39.06,41.11) 38.83,41.11 ; v1(39.06,41.11) 39.06,40.87 ; v1(39.06,41.11) 39.3,41.11 ; 42.83,39.81 v2(43.06,39.81) ; 39.25,10.53 v2(39.03,10.53) 38.8,10.53 ; C1012.2 30,15.62 ; C1012.2 29.2,15.62 ; C1012.2 29.6,15.27 ; v1(19.61,49.94) 19.91,49.94 ; v1(19.61,49.94) 19.61,50.24 ; v1(19.61,49.94) 19.61,49.63 ; U2803.13 8.05,44.44 ; U2803.13 8.85,43.04 ; U2803.13 8.05,41.64 ; U2803.13 7.25,43.04 ; 42.24,21.97 C809.2 ; C809.2 42.24,22.76 ; C809.2 42.6,22.36 ; v2(46.26,38.51) 46.5,38.51 ; v2(46.26,38.51) 46.03,38.51 ; v2(46.26,38.51) 46.26,38.74 ; v2(45.46,29.41) 45.46,29.64 ; v2(45.46,29.41) 45.46,29.17 ; v2(45.46,29.41) 45.23,29.41 ; v2(45.46,29.41) 45.7,29.41 ; 44.55,63.17 v2(44.25,63.17) 44.25,63.45 ; v1(20.46,62.5) 20.46,62.9 ; v1(20.46,62.5) 20.06,62.5 ; v1(20.46,62.5) 20.86,62.5 ; C605.2 47.51,12.83 ; C605.2 47.15,13.18 ; C605.2 47.15,12.47 ; 35.22,61.91 v2(35.22,62.53) ; v2(35.22,62.53) 35.22,63.16 ; v2(35.22,62.53) 34.93,62.53 ; 40.66,38.27 v2(40.66,38.51) ; v2(40.66,38.51) 40.66,38.74 ; v2(40.66,38.51) 40.9,38.51 ; v2(40.66,38.51) 40.43,38.51 ; 36.18,10.48 v2(36.4,10.48) 36.63,10.48 ; 40.43,28.76 v2(40.66,28.76) ; v2(40.66,28.76) 40.66,28.52 ; v2(40.66,28.76) 40.9,28.76 ; v2(40.66,28.76) 40.66,28.99 ; C709.2 46.45,22.92 ; C709.2 46.1,22.52 ; C709.2 46.1,23.32 ; 39.32,11.6 v1(39.55,11.6) ; 32.02,18.76 C1004.2 32.25,18.99 ; 43.45,60.3 v1(43.45,60.61) 43.15,60.61 ; 42.83,30.06 v2(43.06,30.06) ; 18.26,62.1 v1(18.26,62.5) ; v1(18.26,62.5) 18.26,62.9 ; v1(18.26,62.5) 17.86,62.5 ; v1(18.26,62.5) 18.66,62.5 ; 35.89,11.35 v1(35.89,11.57) ; v1(35.89,11.57) 35.66,11.57 ; v1(35.89,11.57) 36.12,11.57 ; 46.26,28.52 v2(46.26,28.76) ; v2(46.26,28.76) 46.5,28.76 ; v2(46.26,28.76) 46.26,28.99 ; v2(46.26,28.76) 46.92,29.41 v1(46.92,39.15) v2(46.26,39.81) ; 31.57,49.33 v2(32,49.33) ; v2(32,49.33) 32.44,49.33 ; v2(32,49.33) 32,48.9 ; 51.65,66.19 v2(51.65,66.94) ; v2(51.65,66.94) 50.85,66.94 ; v2(51.65,66.94) 51.65,67.69 ; v2(51.65,66.94) 52.45,66.94 ; 33.53,64.91 JUSB1.S6 ; JUSB1.S6 33.53,67.91 ; JUSB1.S6 34.28,66.41 ; JUSB1.S6 32.77,66.41 ; 44.38,58.35 v1(44.69,58.35) ; v1(44.69,58.35) 44.69,58.04 ; v1(44.69,58.35) 44.69,58.65 ; v2(13.43,55.32) 13.43,54.7 ; v2(13.43,55.32) 14.05,55.32 ; 27.08,60.53 v1(27.08,60.83) ; v1(27.08,60.83) 27.08,61.14 ; v1(27.08,60.83) 26.77,60.83 ; v1(44.66,32.66) 44.9,32.66 ; v1(44.66,32.66) 44.66,32.89 ; v1(44.66,32.66) 44.43,32.66 ; 4.94,58.69 v2(4.64,58.69) 4.34,58.69 ; 45.69,19.17 v2(45.92,19.17) ; v2(45.92,19.17) 46.15,19.17 ; v2(45.92,19.17) 45.92,19.4 ; 33.96,57.65 v1(33.96,57.35) 33.96,57.05 ; v1(20.46,51.71) 20.86,51.71 ; v1(20.46,51.71) 20.46,52.11 ; v1(20.46,51.71) 20.06,51.71 ; v1(20.46,51.71) 20.46,51.31 ; 40.47,61.86 v2(40.47,61.23) 40.76,61.23 ; 46.1,20.49 C712.2 ; C712.2 46.45,20.89 ; C712.2 46.1,21.29 ; 41.87,63.06 JUSB1.S3 41.01,62.36 ; C1708.2 40.37,24.46 ; C1708.2 40.77,24.1 ; C1708.2 39.97,24.1 ; v2(30.95,60.45) 31.88,60.45 ; DRAM1.T3 39.06,31.25 v1(39.07,31.24) ; 30.37,18.9 C1008.2 ; C1008.2 30.77,19.25 ; C1008.2 29.97,19.25 ; 43.63,35.26 DRAM1.K9 ; DRAM1.K9 43.86,35.02 ; DRAM1.K9 44.1,35.26 ; 46.63,51.97 JCTL1.7 46.63,53.28 ; 42.83,27.46 v2(43.06,27.46) ; v2(43.06,27.46) 43.06,27.22 ; v2(43.06,27.46) 43.3,27.46 ; v2(30.97,33.28) 30.97,33.28 v2(30.19,33.28) ; 44.25,60.3 v2(44.25,60.61) 44.55,60.61 ; 47.15,13.31 C606.2 ; C606.2 47.51,13.66 ; C606.2 47.15,14.01 ; 38.8,11.57 v1(39.02,11.57) 39.25,11.57 ; v1(42.06,59.13) 42.06,59.43 ; v1(42.06,59.13) 41.78,59.13 ; v1(42.06,59.13) 42.06,58.83 ; 46.86,57.15 v2(47.12,57.15) ; v2(47.12,57.15) 47.12,56.84 ; v2(47.12,57.15) 47.12,57.46 ; 46.03,39.81 v2(46.26,39.81) ; v2(46.26,39.81) 46.26,39.57 ; v2(46.26,39.81) 46.5,39.81 ; v2(46.26,39.81) 46.26,40.04 ; 37.45,11.35 v1(37.45,11.57) ; v1(37.45,11.57) v1(36.93,11.57) ; v1(37.45,11.57) 37.67,11.57 ; v2(11.03,55.32) 11.03,54.7 ; 5.58,46.1 v1(5.58,45.79) 5.28,45.79 ; v1(37.23,56.24) 37.23,56.54 ; 43.18,16.84 v2(43.18,17.07) ; v2(43.18,17.07) 43.41,17.07 ; v2(43.18,17.07) 43.18,17.29 ; 23.32,39.46 v1(23.09,39.46) 23.09,39.23 ; R2909.1 3.03,62.07 ; R2909.1 3.03,61.47 ; R2909.1 2.72,61.77 ; 32.44,13.92 v1(32.44,14.15) ; v1(32.44,14.15) 32.21,14.15 ; v1(32.44,14.15) 32.44,14.37 ; 31.65,15.54 v2(31.88,15.54) 32.1,15.54 ; 32.44,15.44 v2(32.44,15.67) 32.21,15.67 ; R606.2 38.65,9.49 ; R606.2 38.42,9.26 ; R606.2 38.2,9.49 ; 6.44,54 v1(6.44,54.4) ; v1(6.44,54.4) 6.44,54.8 ; v1(6.44,54.4) 6.84,54.4 ; v1(6.44,54.4) 6.04,54.4 ; C1005.2 29.75,19.25 ; C1005.2 29.35,18.9 ; C1005.2 28.95,19.25 ; 43.15,63.19 v1(43.45,63.19) 43.45,63.47 ; 45.07,16.93 C607.2 44.67,16.58 ; v2(34.16,9.65) 34.39,9.65 ; v2(34.16,9.65) 34.16,9.42 ; v2(34.16,9.65) 33.94,9.65 ; 37.97,21.21 37.97,21.56 ; 37.97,21.21 38.33,21.21 ; 37.97,21.21 37.62,21.21 ; 45.92,17.41 v1(45.92,17.64) ; v1(45.92,17.64) 45.69,17.64 ; v1(45.92,17.64) 46.15,17.64 ; v2(8.1,49.94) 8.1,50.24 ; v2(8.1,49.94) 7.8,49.94 ; v2(8.1,49.94) 8.1,49.63 ; 31.12,15.54 v2(31.34,15.54) ; v2(31.34,15.54) 31.34,15.32 ; v2(31.34,15.54) 31.57,15.54 ; v2(5.72,44.41) 6.02,44.41 ; v2(5.72,44.41) 5.42,44.41 ; v2(5.72,44.41) 5.72,44.72 ; v1(16.68,48) 16.68,48.53 ; v1(16.68,48) 16.05,48 ; v1(16.68,48) 17.31,48 ; C717.2 36.63,9.44 ; C717.2 36.4,9.21 ; C717.2 36.17,9.44 ; 4.94,59.87 v2(4.64,59.87) 4.34,59.87 ; v2(46.26,32.66) 46.5,32.66 ; v2(46.26,32.66) 46.26,32.42 ; v2(46.26,32.66) 46.26,32.89 ; v2(46.26,32.66) 46.03,32.66 ; 37.67,10.48 v1(37.45,10.48) 37.22,10.48 ; 46.26,31.12 v2(46.26,31.36) ; v2(46.26,31.36) 46.26,31.59 ; v2(46.26,31.36) 46.5,31.36 ; 32.72,49.33 v1(32.72,49.63) ; 40.1,29.41 v2(39.86,29.41) 39.86,29.17 ; 32.21,13.13 v2(32.44,13.13) 32.44,13.36 ; 24.81,15.65 v1(24.58,15.65) 24.58,15.42 ; 35.35,12.27 C706.2 35.35,11.81 ; 43.29,19.99 v1(43.29,19.76) 43.51,19.76 ; 30.77,22.05 v1(30.37,22.05) 29.97,22.05 ; v1(31.52,51.74) 31.15,52.11 Y3001.2 ; 23.04,52.89 v1(23.04,53.2) ; v1(23.04,53.2) 23.34,53.2 ; v1(23.04,53.2) 22.74,53.2 ; v2(44.66,27.46) 44.9,27.46 ; v2(44.66,27.46) 44.66,27.22 ; v2(44.66,27.46) 44.43,27.46 ; 41.44,20.62 v2(41.66,20.62) ; v2(41.66,20.62) 41.66,20.85 ; v2(41.66,20.62) 41.89,20.62 ; C504.2 41.36,20.62 ; 39.63,35.26 DRAM1.K4 ; DRAM1.K4 40.1,35.26 ; DRAM1.K4 39.86,35.02 ; 32.05,57.35 v2(32.36,57.35) 32.36,57.65 ; v2(36.73,59.33) 36.73,60.26 ; v2(36.92,9.44) 37.15,9.44 ; v2(36.92,9.44) 36.69,9.44 ; v2(36.92,9.44) 36.92,9.21 ; 32.97,32.88 32.97,32.48 SOC1.G20 ; 30.02,60.45 v2(30.51,60.45) ; v2(12.23,57.72) 12.23,58.34 ; v1(32.72,51.21) 32.72,51.51 ; 35.73,56.5 v1(35.73,56.19) 36.03,56.19 ; 16.33,49.63 v1(16.33,49.94) ; v1(16.33,49.94) 16.33,50.24 ; v1(16.33,49.94) 16.64,49.94 ; 40.59,11.87 v2(40.59,12.1) ; v1(37.46,32.66) 37.7,32.66 ; 43.41,16.02 v2(43.18,16.02) 43.18,16.25 ; 33.25,49.33 v1(33.25,49.63) ; 31.61,26.16 v1(31.84,26.16) ; v1(31.84,26.16) 32.07,26.16 ; v1(31.84,26.16) 31.84,25.94 ; 34.51,11.38 C704.2 34.28,11.15 ; 22.77,26.56 v1(23,26.56) 23,26.79 ; 43.18,16.31 C508.2 43.18,16.77 ; 42.83,38.51 v2(43.06,38.51) ; 39.07,5.75 v1(39.3,5.75) 39.53,5.75 ; 28.54,13.05 v1(28.77,13.05) 28.77,13.28 ; 35.05,50.16 v1(35.05,49.86) 35.05,49.56 ; v1(36.93,11.57) 36.7,11.57 ; v1(36.93,11.57) 36.93,11.35 ; 43.3,31.36 DRAM1.T8 43.06,31.59 ; v1(37.77,56.24) 38.07,56.24 ; 36.7,10.48 v2(36.93,10.48) 37.16,10.48 ; v1(37.46,37.21) 37.7,37.21 ; v2(40.66,37.21) 40.9,37.21 ; 28.1,54.53 Y3001.4
  TOP w0.254: v1(33.5,54.15) 33.48,54.18 33.48,54.69 32.61,55.55 29.21,55.55 ; v1(33.5,52.83) 33.15,52.83 32.08,51.76 v1(28.09,51.76) 27.91,51.94 v2(27.91,52.34) v2(27.91,53.65) v2(27.91,54.61) 27.91,55.27 28.19,55.55 29.21,55.55 ; 29.21,55.55 28.95,55.29 Y3001.4
  TOP w0.3: 6.2,43.79 v2(6.66,43.79) 7.12,43.79
  TOP w0.6: 26.65,60.43 v1(26.65,59.7) 26.65,58.97
  G2 w0.051: v1(35.77,52.34) 35.97,52.15 35.97,51.64 ; 36.7,52.17 36.78,52.1 36.78,51.77 36.78,51.77 ; 36.78,52.53 36.86,52.53 36.89,52.55 37.08,52.55 37.1,52.53 37.36,52.53 37.41,52.58 ; 37.26,53.34 36.8,53.34 36.73,53.26
  G2 w0.2: 28.17,36.48 v2(28.17,36.88) ; v1(30.57,30.08) v2(30.17,30.08)
  G2 w0.203: 41.01,62.36 JUSB1.S3 41.87,63.06 ; 50.8,41.11 JDIGITAL1.15 ; JDIGITAL1.15 51.85,42.16 ; JDIGITAL1.15 49.75,42.16 ; JDIGITAL1.15 50.8,43.21 ; 24.36,2.37 JSPI1.6 ; JSPI1.6 26.47,2.37 ; JSPI1.6 25.41,3.43 ; JSPI1.6 25.41,1.32 ; JANALOG1.7 2.54,26.45 ; JANALOG1.7 2.54,24.35 ; JANALOG1.7 1.49,25.4 ; JANALOG1.7 3.59,25.4 ; 41.41,66.41 JUSB1.S5 ; JUSB1.S5 42.17,67.91 ; JUSB1.S5 42.17,64.91 ; JUSB1.S5 42.92,66.41 ; JUSB1.S1 42.17,63.06 ; JUSB1.S1 42.17,60.66 ; JUSB1.S1 42.82,61.86 ; 33.53,60.66 JUSB1.S2 ; JUSB1.S2 33.53,63.06 ; JUSB1.S2 32.87,61.86 ; v1(39.02,11.57) v1(38.51,11.57) ; 36.19,15.93 36.19,15.58 35.96,15.58 ; 34.68,62.36 JUSB1.S4 33.83,63.06 ; 32.77,66.41 JUSB1.S6 ; JUSB1.S6 34.28,66.41 ; JUSB1.S6 33.53,67.91 ; JUSB1.S6 33.53,64.91 ; 1.49,27.94 JANALOG1.6 ; JANALOG1.6 3.59,27.94 ; JANALOG1.6 2.54,28.99 ; JANALOG1.6 2.54,26.89
  S3 w0.05: 34.37,40.09 34.63,40.35 ; 35.26,40.23 35.26,39.96 v2(34.97,39.68)
  S3 w0.051: v2(33.17,39.5) 33.15,39.52 33.1,39.52 32.93,39.69 32.93,41.69 27.32,47.3 ; 22.48,30.69 22.66,30.51 23.82,30.51 23.96,30.65 ; v2(41.15,20.65) 41.28,20.65 41.39,20.76 ; 34.39,39.72 34.35,39.68 v2(34.17,39.68) 34.37,39.88 34.37,40.09
  S3 w0.058: 29.79,49.96 29.56,50.19 29.46,50.19
  S3 w0.06: 15.62,47.68 15.62,45.39 18.44,42.57 20.28,42.57 21.74,41.11 v2(21.74,41.03) 21.56,40.85 21.33,40.85 19.91,42.27 18.42,42.27 15.36,45.33 15.36,47.14 v2(15.25,47.25) ; v2(35.29,15.98) 35.04,15.72 34.89,15.72 34.52,15.35 34.52,15.18 33.42,14.08 33.42,13.74 33.18,13.5 32.19,13.5 31.68,14.01 v2(31.64,14.01)
  S3 w0.064: 31.34,47.35 31.34,46.82 31.83,46.33 35.56,42.6 35.56,40.72 35.26,40.42 35.26,40.23 ; 29.62,48.5 29.84,48.28 30.42,48.28 30.84,47.86 30.84,46.76 35.16,42.44 35.16,40.89 34.63,40.35 ; 35.26,39.96 35.31,40.02 36.16,40.02 36.31,40.17 36.31,40.38 36.15,40.55 36.15,40.74 36.19,40.78 ; v2(29.95,11.91) 30.65,11.91 30.74,11.82 33.99,11.82 34.82,12.65 ; v2(30.28,13.98) 30.45,13.98 31.6,12.83 33.53,12.83 33.71,13.01 33.71,14.02 34.7,15.01 35.1,15.01 35.2,15.11 35.41,15.11 35.46,15.06 v2(35.53,15.06) ; 1.03,42.7 1.34,42.7
  S3 w0.066: v2(34.07,13.26) 34.04,13.26 34,13.22 34,13.11 33.97,13.09 33.97,12.94 33.58,12.55 32.67,12.55 32.67,12.55 31.39,12.55 30.61,13.34 30.12,13.34 ; 34.46,12.68 33.87,12.09 30.97,12.09 30.78,12.27 30.11,12.27 30.05,12.33 30.05,12.65 30.15,12.75 ; v2(30.28,13.98) 30.05,13.75 30.05,13.41 30.12,13.34 ; 30.15,12.75 30.78,12.75 30.87,12.67 30.87,12.67 31.22,12.32 32.58,12.32 32.58,12.32 33.77,12.32 34.36,12.91 34.36,13.13 34.36,13.14 34.36,13.45 ; 30.15,12.75 30.05,12.85 30.05,13.26 30.12,13.34
  S3 w0.079: 9.07,12.09 7.43,12.09 7.39,12.13
  S3 w0.1: v2(29.39,18.24) 29.49,18.13 29.72,18.13 ; 30.51,19.52 30.27,19.52 v2(30.15,19.41)
  S3 w0.127: v2(32.17,32.48) 32.17,32.76 32.21,32.8 v3(32.21,32.8) ; v2(43.86,29.41) 43.92,29.47 v3(43.92,29.69) ; v3(27.37,35.41) v2(27.37,35.68) ; v3(45.29,33.06) 45.46,33.24 v2(45.46,33.31) ; v2(32.17,31.68) 32.17,31.61 31.98,31.42 31.98,31.39 32,31.39 32,31.43 v3(31.99,31.43) ; v3(33.3,38.08) v2(32.97,38.08) ; v3(28.17,30.36) v2(28.17,30.08) ; v2(32.53,30.49) 32.56,30.49 32.56,30.56 32.57,30.55 32.57,30.13 32.51,30.07 32.51,30.04 32.58,30.04 v3(32.58,30.06) ; v2(40.66,37.21) v3(40.46,37.01) 40.46,37.01 40.46,37.02 ; v3(39.53,35.4) 39.61,35.32 v2(39.86,35.32) ; v2(44.66,37.21) 44.72,37.15 44.72,36.7 44.44,36.41 44.35,36.41 v3(44.18,36.24) ; v3(28.97,33.32) 29,33.32 29,33.33 29.06,33.33 29.03,33.35 29.03,33.43 29.01,33.45 29.01,33.69 28.98,33.66 28.98,33.68 v2(28.97,33.68) ; v3(30.97,31.96) v2(30.97,31.68) ; v2(28.57,30.88) 28.57,30.53 v3(28.52,30.53) ; v2(43.06,30.06) 43.05,30.05 v3(42.79,30.05) ; v3(45.07,29.28) 45.2,29.41 v2(45.46,29.41) ; v3(37.13,28.78) 37.11,28.77 37.09,28.77 ; v2(30.57,30.4) 30.57,30.09 30.47,29.99 ; v2(27.37,33.28) 27.16,33.28 27.1,33.22 v3(27.1,33.22) ; v3(30.21,32.16) 30.21,32.08 v2(30.57,32.08) ; v3(27.9,29.6) 27.99,29.68 v2(28.17,29.68) ; v3(38.81,35.74) 38.98,35.91 v2(39.06,35.91) ; v3(26.83,34.16) 26.64,34.16 26.6,34.11 26.54,34.11 26.54,34.13 26.58,34.13 26.58,34.13 v2(26.56,34.13) ; v3(42.86,37.4) 42.87,37.4 v2(43.06,37.21) ; v3(30.1,31.65) 30.1,31.61 SOC1.R23 29.77,31.33 v2(29.78,31.33) ; v2(28.97,36.48) 28.97,36.28 v3(29.07,36.18) ; v2(28.57,30.08) 28.81,30.08 28.91,30.18 28.91,30.08 v3(28.85,30.08) ; v3(26.29,32.08) v2(26.57,32.08) ; v2(28.17,31.68) 28.17,31.31 28.28,31.2 28.28,31.19 v3(28.28,31.19) ; v3(30.44,37.28) v2(30.17,37.28) ; v3(33.09,37.68) v2(33.37,37.68) ; v3(26.03,31.68) v2(26.57,31.68) ; v3(29.21,34.77) 29.22,34.77 29.37,34.62 v2(29.37,34.48) ; v3(45.39,38.88) 45.39,39.04 45.46,39.12 v2(45.46,39.16) ; v3(26.69,30.08) v2(26.97,30.08) ; v3(31.89,33.25) 31.9,33.25 31.93,33.28 v2(32.17,33.28) ; v3(31.83,30.14) 31.71,30.14 31.77,30.19 v2(31.77,30.48) ; v3(28.28,37.68) v2(28.57,37.68) ; v2(43.06,28.76) 43.06,28.74 v3(43.26,28.55)
  S3 w0.15: v2(34.36,34.72) 34.36,34.71 34.62,34.46 v3(34.75,34.46) 34.84,34.46 v2(35.1,34.2)
  S3 w0.2: v3(28.59,33.22) 28.57,33.19 v2(28.57,32.88) ; v2(32.17,34.08) 32.17,33.8 32.21,33.76 v3(32.21,33.76) ; v3(37.63,40.09) 37.43,39.9 v2(37.42,39.9) ; v2(46.26,37.21) 46.54,37.21 v3(46.55,37.22) ; v2(37.4,28.71) 37.2,28.71 v3(37.13,28.78) ; v3(29.1,35.61) 29.1,35.51 28.97,35.38 v2(28.97,35.28) ; v2(46.26,28.76) v3(46.55,28.76) ; v3(32.17,35.33) v2(32.17,35.68) ; 30.88,33.76 30.97,33.85 30.97,34.08 30.97,34.08 30.97,34.08 30.98,34.08 30.98,34.08 31,34.08 v2(31,34.08) ; v3(30.99,36.86) 31.06,36.86 31.06,36.75 30.97,36.66 v2(30.97,36.48) ; v3(30.23,33.56) 30.27,33.56 30.27,33.58 30.22,33.58 30.22,33.58 30.17,33.53 30.17,33.32 30.16,33.31 30.16,33.29 30.17,33.28 v2(30.19,33.28) ; v3(46.55,32.68) 46.52,32.66 v2(46.26,32.66) ; v2(46.26,38.51) v3(46.56,38.51) ; v2(43.06,39.81) 42.83,39.81 42.82,39.8 v3(42.79,39.8) ; v2(43.06,38.51) 42.88,38.32 42.88,38.31 v3(42.87,38.31) ; v2(30.97,35.28) 30.97,35.53 31.01,35.58 31.01,35.58 31.03,35.58 v3(31.03,35.58) ; v2(39.86,39.16) 39.68,38.98 v3(39.64,38.98) ; v3(29.25,31.93) 29.21,31.93 29.21,31.93 29.31,31.83 29.31,31.67 v2(29.33,31.67) ; v2(43.06,27.46) v3(43.06,27.17) ; v2(39.86,29.41) 39.58,29.41 v3(39.58,29.41) ; v2(38.26,29.41) v3(38.26,29.69) ; v2(29.01,34.46) 28.8,34.25 28.75,34.25 28.75,34.29 28.74,34.29 v3(28.74,34.3) ; v2(28.57,32.08) 28.57,32.29 28.5,32.36 28.5,32.37 v3(28.52,32.37) ; v2(46.26,39.81) v3(46.56,39.81) ; v2(44.66,41.11) v3(44.97,41.11) ; v3(30.17,36.07) v2(30.17,35.68) ; v3(29.18,33.99) 29.2,33.99 29.2,33.91 v2(29.36,33.76) ; v3(28.2,36.36) 28.17,36.36 v2(28.17,36.08) ; v3(40.38,28.73) 40.4,28.76 v2(40.66,28.76) ; v2(46.26,30.06) v3(46.58,30.06) ; v3(29.07,36.88) v2(29.37,36.88) ; v2(45.46,35.26) 45.48,35.24 v3(45.48,34.97) ; v3(31.01,37.68) v2(31.37,37.68) ; v3(28.31,37.2) 28.39,37.28 v2(28.57,37.28) ; v2(30.97,34.48) 30.97,34.84 31.01,34.84 31.01,34.84 30.99,34.84 30.99,34.83 v3(31.02,34.83) ; v3(32.17,34.55) v2(32.17,34.88) ; v3(30.17,35.28) v2(30.17,34.88) ; v2(46.26,35.91) v3(45.99,35.91) ; v2(38.32,39.12) v3(38.52,39.32) ; v2(46.26,31.36) v3(46.55,31.36) ; v2(44.66,27.46) v3(44.46,27.66) ; v2(40.66,39.81) v3(41,39.81) ; v2(39.08,27.43) v3(39.08,27.15) ; v2(43.86,39.16) v3(43.86,38.87)
  S3 w0.203: JDIGITAL1.15 50.8,43.21 ; JDIGITAL1.15 50.8,41.11 ; JDIGITAL1.15 51.85,42.16 ; JDIGITAL1.15 49.75,42.16 ; JSPI1.6 25.41,3.43 ; JSPI1.6 26.47,2.37 ; JSPI1.6 25.41,1.32 ; JSPI1.6 24.36,2.37 ; 2.54,26.89 JANALOG1.6 ; JANALOG1.6 3.59,27.94 ; JANALOG1.6 1.49,27.94 ; JANALOG1.6 2.54,28.99 ; v3(33.6,29.54) 33.6,29.65 33.57,29.68 v2(33.37,29.68) ; JUSB1.S5 42.92,66.41 ; JUSB1.S5 42.17,67.91 ; JUSB1.S5 41.41,66.41 ; 2.54,24.35 JANALOG1.7 ; JANALOG1.7 2.54,26.45 ; JANALOG1.7 3.59,25.4 ; JANALOG1.7 1.49,25.4 ; 41.87,63.06 JUSB1.S3 41.01,62.36 ; v2(39.26,18.24) 39.26,18.1 39.19,18.03 ; 34.68,62.36 JUSB1.S4 33.83,63.06 ; v3(37.18,38.06) 37.18,38.36 v2(37.19,38.37) ; v2(42.06,21.56) 42.06,21.56 42.23,21.39 ; JUSB1.S6 34.28,66.41 ; JUSB1.S6 32.77,66.41 ; JUSB1.S6 33.53,67.91 ; 32.87,61.86 JUSB1.S2 ; JUSB1.S2 33.53,63.06 ; JUSB1.S2 33.53,60.66 ; JUSB1.S1 42.17,63.06 ; JUSB1.S1 42.82,61.86 ; JUSB1.S1 42.17,60.66
  V4 w0.203: 41.01,62.36 JUSB1.S3 41.87,63.06 ; 41.41,66.41 JUSB1.S5 ; JUSB1.S5 42.17,64.91 ; JUSB1.S5 42.17,67.91 ; JUSB1.S5 42.92,66.41 ; JANALOG1.6 2.54,28.99 ; JANALOG1.6 3.59,27.94 ; JANALOG1.6 2.54,26.89 ; JANALOG1.6 1.49,27.94 ; 1.49,25.4 JANALOG1.7 ; JANALOG1.7 2.54,24.35 ; JANALOG1.7 2.54,26.45 ; JANALOG1.7 3.59,25.4 ; JDIGITAL1.15 51.85,42.16 ; JDIGITAL1.15 50.8,41.11 ; JDIGITAL1.15 50.8,43.21 ; JDIGITAL1.15 49.75,42.16 ; 42.17,60.66 JUSB1.S1 ; JUSB1.S1 42.17,63.06 ; JUSB1.S1 42.82,61.86 ; 25.41,1.32 JSPI1.6 ; JSPI1.6 24.36,2.37 ; JSPI1.6 25.41,3.43 ; JSPI1.6 26.47,2.37 ; 34.68,62.36 JUSB1.S4 33.83,63.06 ; JUSB1.S6 33.53,67.91 ; JUSB1.S6 34.28,66.41 ; JUSB1.S6 33.53,64.91 ; JUSB1.S6 32.77,66.41 ; JUSB1.S2 33.53,63.06 ; JUSB1.S2 32.87,61.86 ; JUSB1.S2 33.53,60.66
  V5 w0.203: JSPI1.6 25.41,3.43 ; JSPI1.6 25.41,1.32 ; JSPI1.6 26.47,2.37 ; JSPI1.6 24.36,2.37 ; 42.17,60.66 JUSB1.S1 ; JUSB1.S1 42.82,61.86 ; JUSB1.S1 42.17,63.06 ; JUSB1.S2 33.53,63.06 ; JUSB1.S2 32.87,61.86 ; JUSB1.S2 33.53,60.66 ; JUSB1.S6 33.53,67.91 ; JUSB1.S6 34.28,66.41 ; JUSB1.S6 32.77,66.41 ; JDIGITAL1.15 50.8,43.21 ; JDIGITAL1.15 49.75,42.16 ; JDIGITAL1.15 51.85,42.16 ; JDIGITAL1.15 50.8,41.11 ; 41.87,63.06 JUSB1.S3 41.01,62.36 ; JUSB1.S5 42.17,67.91 ; JUSB1.S5 41.41,66.41 ; JUSB1.S5 42.92,66.41 ; 12.75,17.11 13.34,17.7 v3(13.36,17.7) ; 34.68,62.36 JUSB1.S4 33.83,63.06
  S6 w0.051: 32.71,33.27 32.71,33.27 32.83,33.15 32.95,33.15
  S6 w0.127: v3(26.71,30.63) v5(26.91,30.82)
  S6 w0.15: 30.1,33.8 30.23,33.67 v3(30.23,33.56)
  S6 w0.2: v5(26.91,30.28) 26.89,30.28 v3(26.69,30.08) 26.93,29.85 26.93,29.75 ; v5(33.84,37.42) 33.65,37.42 v5(33.36,37.71) 33.11,37.71 v3(33.09,37.68) 32.87,37.46 32.87,37.48 v5(32.84,37.48) ; v5(29.3,33.74) 29.3,33.67 29.2,33.76 29.2,33.99 v3(29.18,33.99) ; 27.93,29.88 27.93,29.62 v3(27.9,29.6) ; v3(40.66,27.17) 40.52,27.32 v5(40.52,27.53) ; v3(29.21,34.77) 29.18,34.75 29.18,34.51 v5(29.14,34.46) ; v5(46.47,28.1) 46.47,28.39 46.55,28.47 v3(46.55,28.76) ; v5(40.42,37.36) 40.42,37.04 v3(40.46,37.01) ; v5(27.99,36.12) 27.99,36.21 28.15,36.36 v3(28.2,36.36) ; v3(27.1,33.22) 27.26,33.06 27.26,33 v5(27.27,33) ; v5(38.26,39.07) 38.27,39.07 v3(38.52,39.32) ; 46.15,29.41 46.15,29.63 v3(46.58,30.06) ; v5(38.68,27.15) 39.08,27.15 v3(39.08,27.15) ; v5(46.18,32.68) 46.53,32.68 46.53,32.68 v3(46.55,32.68) ; v5(36.67,31.06) v3(36.67,30.77) 36.64,30.74 v5(34.29,30.74) 34.27,30.73 v5(33.77,30.73) ; v5(29.1,29.79) 29.1,29.9 28.91,30.1 28.91,30.08 v3(28.85,30.08) ; v5(46.21,31.44) 46.41,31.44 46.5,31.36 v3(46.55,31.36) ; v5(40.36,31.38) 40.66,31.38 v3(40.66,31.37) ; v5(33.97,34.63) 34.09,34.52 34.68,34.52 v3(34.75,34.46) 34.86,34.35 v5(35,34.35) ; v5(29.07,36.59) 29.07,36.88 v3(29.07,36.88) 29,36.94 v5(29,37.15) ; v3(28.28,31.19) 28.28,31.19 28.28,31.2 28.42,31.34 28.55,31.34 28.55,31.33 28.54,31.33 28.54,31.32 v5(28.54,31.32) ; v5(43.03,27.59) 43.03,27.2 v3(43.06,27.17) ; v3(37.18,38.06) 37.18,38.37 v5(37.21,38.41) ; v3(28.59,33.22) 28.59,33.29 28.32,33.56 28.32,33.53 v5(28.3,33.53) ; v5(26.35,35.7) 26.35,35.65 26.5,35.5 ; v3(28.52,30.53) 28.57,30.53 28.57,30.4 28.45,30.28 28.45,30.25 28.4,30.3 28.23,30.3 v3(28.17,30.36) ; v5(31.71,38.69) 32.35,38.69 v5(32.64,38.4) ; v3(38.26,29.69) 38.13,29.56 v5(38.13,29.41) ; v5(28.82,33.57) 28.96,33.43 29.03,33.43 29.03,33.35 29.06,33.33 29,33.33 29,33.32 v3(28.97,33.32) ; v5(26.91,31.36) v5(26.91,30.82) ; v3(26.83,34.16) 26.94,34.05 v5(27.27,34.05) ; v5(25.76,31.54) 25.89,31.54 v3(26.03,31.68) 26.12,31.6 C1834.2 26.35,31.6 v5(26.35,31.6) ; v5(39.79,38.47) 39.79,38.83 v3(39.64,38.98) ; v5(45.96,34.97) v3(45.48,34.97)
  S6 w0.203: JANALOG1.7 3.59,25.4 ; JANALOG1.7 1.49,25.4 ; JANALOG1.7 2.54,26.45 ; JANALOG1.7 2.54,24.35 ; 34.68,62.36 JUSB1.S4 33.83,63.06 ; 32.18,36.02 32.28,36.12 v5(32.36,36.12) ; JSPI1.6 26.47,2.37 ; JSPI1.6 24.36,2.37 ; JSPI1.6 25.41,3.43 ; JSPI1.6 25.41,1.32 ; 32.16,33.35 32.22,33.41 v5(32.35,33.41) ; JUSB1.S6 34.28,66.41 ; JUSB1.S6 33.53,67.91 ; JUSB1.S6 32.77,66.41 ; 49.75,42.16 JDIGITAL1.15 ; JDIGITAL1.15 50.8,41.11 ; JDIGITAL1.15 51.85,42.16 ; JDIGITAL1.15 50.8,43.21 ; 42.82,61.86 JUSB1.S1 42.17,63.06 ; JANALOG1.6 2.54,28.99 ; JANALOG1.6 1.49,27.94 ; JANALOG1.6 3.59,27.94 ; JANALOG1.6 2.54,26.89 ; JUSB1.S5 42.92,66.41 ; JUSB1.S5 41.41,66.41 ; JUSB1.S5 42.17,67.91 ; v3(8.81,20.8) 8.74,20.88 v4(8.74,21.08) ; v3(43.92,29.69) 43.92,29.35 44,29.27 ; 30.99,35.15 30.96,35.13 v5(30.88,35.13) ; 33.53,60.66 JUSB1.S2 ; JUSB1.S2 33.53,63.06 ; JUSB1.S2 32.87,61.86 ; 26.3,38.36 26.3,38.71 26.28,38.71 v5(26.17,38.6) ; 41.87,63.06 JUSB1.S3 41.01,62.36 ; v5(6.17,44.53) 6.05,44.53 ; v5(40.7,39.75) 40.94,39.75 v3(41,39.81) ; 30.15,34.67 30.08,34.6 v5(30.04,34.6) ; v3(38.81,35.74) 39.19,35.74 v3(39.53,35.4)
  G7 w0.051: 33.8,34.35 33.4,34.35 33.35,34.3 33.35,33.65 ; 32.5,31.45 32.65,31.45 32.75,31.35 33.05,31.35 33.2,31.5 ; 28.55,37.25 28.7,37.25 28.83,37.12
  G7 w0.2: v5(30.66,37.1) 31.11,37.1 v5(31.14,37.14) 31.39,37.14 31.43,37.1 v5(31.71,37.1) 32.21,37.1 v5(32.21,37.11) 32.46,37.11 32.58,37.23 32.63,37.23 32.69,37.28 32.82,37.41 32.87,37.41 32.87,37.48 v5(32.84,37.48) ; 32.98,29.95 32.74,30.19 v5(32.74,30.19) ; v5(34.03,34.11) 34.03,34.46 33.91,34.58 33.92,34.58 33.92,34.66 33.95,34.66 33.95,34.63 v5(33.97,34.63)
  G7 w0.203: 32.87,61.86 JUSB1.S2 ; JUSB1.S2 33.53,60.66 ; JUSB1.S2 33.53,63.06 ; v4(9.75,24.68) 9.47,24.68 v5(9.4,24.61) ; 50.8,41.11 JDIGITAL1.15 ; JDIGITAL1.15 51.85,42.16 ; JDIGITAL1.15 50.8,43.21 ; JDIGITAL1.15 49.75,42.16 ; JANALOG1.7 3.59,25.4 ; JANALOG1.7 2.54,24.35 ; JANALOG1.7 1.49,25.4 ; 32.77,66.41 JUSB1.S6 ; JUSB1.S6 33.53,64.91 ; JUSB1.S6 34.28,66.41 ; JUSB1.S6 33.53,67.91 ; 42.17,64.91 JUSB1.S5 ; JUSB1.S5 41.41,66.41 ; JUSB1.S5 42.17,67.91 ; JUSB1.S5 42.92,66.41 ; 34.12,19.76 34.13,19.75 v5(34.13,19.61) ; 42.17,60.66 JUSB1.S1 ; JUSB1.S1 42.17,63.06 ; JUSB1.S1 42.82,61.86 ; 25.41,1.32 JSPI1.6 ; JSPI1.6 25.41,3.43 ; JSPI1.6 24.36,2.37 ; JSPI1.6 26.47,2.37 ; v5(33.75,31.3) 33.71,31.3 33.71,32.27 v5(33.69,32.29) ; JANALOG1.6 3.59,27.94 ; JANALOG1.6 1.49,27.94 ; JANALOG1.6 2.54,28.99 ; v5(33.01,33.33) 33.54,32.8 v5(33.56,32.8) ; 34.68,62.36 JUSB1.S4 33.83,63.06 ; 41.87,63.06 JUSB1.S3 41.01,62.36 ; v5(26.23,34.08) 26.23,33.92 26.25,33.9
  BOTTOM w0.051: v5(27.8,34.04) 27.81,34.04 28.09,33.76 28.22,33.76 28.3,33.68 v5(28.3,33.53) ; 30.78,35.86 30.89,35.86 31.15,35.6 C1812.2 31.15,35.56 30.91,35.32 ; MCU1.B8 v5(14.2,25.3) ; v5(9.58,22.45) 9.68,22.35 10.16,22.35 v5(10.4,22.11) ; MCU1.H2 11.17,21.89 10.62,21.89 v5(10.4,22.11) ; v5(10.4,22.11) 10.64,22.35 11.18,22.35 v5(11.25,22.28)
  BOTTOM w0.064: 31,34.1 31,34.1 30.98,34.1 30.96,34.1 30.96,34.11 30.9,34.11 30.9,34.08 30.88,34.08 30.88,34.08 30.78,34 ; C1823.2 29.43,33.54 29.34,33.63 29.31,33.63 29.31,33.66 29.3,33.66 v5(29.3,33.74)
  BOTTOM w0.1: v5(11.25,22.28) 11.4,22.13 MCU1.H2
  BOTTOM w0.2: 16.75,38.47 v5(16.75,38.97) ; C1743.2 v5(26.26,32.44)
  BOTTOM w0.203: 36.99,54.95 JMEDIA1.13 ; JMEDIA1.13 37.47,53.94 ; JMEDIA1.13 37.94,54.95 ; JMEDIA1.13 37.47,55.95 ; v5(23.64,13.72) 23.64,13.95 ; v5(23.64,13.72) 23.64,13.48 ; v5(23.64,13.72) 23.82,13.72 ; 21.75,54.95 v5(22.23,54.95) ; v5(22.23,54.95) 22.23,55.95 ; v5(22.23,54.95) 22.23,53.94 ; v5(22.23,54.95) 22.7,54.95 ; 43.03,27.37 v5(43.03,27.59) ; v5(43.03,27.59) 43.26,27.59 ; v5(43.03,27.59) 42.8,27.59 ; v5(18.41,11.98) 18.89,11.98 ; v5(18.41,11.98) 18.41,10.98 ; v5(18.41,11.98) 17.94,11.98 ; 36.67,30.83 v5(36.67,31.06) ; v5(36.67,31.06) 36.67,31.29 ; v5(36.67,31.06) 36.45,31.06 ; v5(34.13,19.61) 34.36,19.61 ; v5(34.13,19.61) 34.13,19.38 ; v5(34.13,19.61) 34.13,19.83 ; 41.3,51.65 v5(41.3,52.14) ; 34.03,34.34 v5(34.03,34.11) 34.03,33.89 ; JUSB1.S6 33.53,67.91 ; JUSB1.S6 34.28,66.41 ; JUSB1.S6 32.77,66.41 ; JUSB1.S6 33.53,64.91 ; 10.79,53.94 v5(10.79,54.95) ; v5(10.79,54.95) 11.27,54.95 ; v5(10.79,54.95) 10.79,55.95 ; v5(10.79,54.95) 10.32,54.95 ; 31.48,37.11 C1846.2 31.93,37.11 ; 13,18.82 C2527.2 ; C2527.2 13,20.7 v5(12.8,20.9) ; C2527.2 12.7,19.13 ; C2527.2 12.5,18.62 ; C1825.2 29.12,33.51 ; C1825.2 28.66,33.51 ; C1825.2 28.89,33.28 ; 26.24,32.67 C1743.2 26.24,32.21 ; 30.66,29.69 C1909.2 30.89,29.92 ; v5(29.84,58.85) 30.32,58.85 ; v5(29.84,58.85) 29.84,57.84 ; v5(29.84,58.85) 29.37,58.85 ; v5(29.84,58.85) 29.84,59.85 ; 18.6,34.4 v5(18.9,34.4) 18.9,34.09 ; 30.56,34 30.78,34 30.78,33.77 ; 8.13,16.35 v5(8.13,17.02) 8.13,18.82 8.47,19.16 v5(9.55,19.16) 9.55,20.48 v5(9.96,20.88) ; 8.13,16.35 8.13,15.56 8.35,15.34 12.25,15.34 12.5,15.59 v5(12.5,16.07) ; 8.13,16.35 8.14,16.34 Y2501.2 ; 17.4,6.08 D26073.1 ; D26073.1 17.71,5.83 ; D26073.1 18.02,6.08 ; MCU1.M3 v5(9.58,22.45) ; 41.01,62.36 JUSB1.S3 41.87,63.06 ; 43.98,46.19 v5(43.98,45.89) 43.67,45.89 ; 46,45.42 v5(46.3,45.42) 46.6,45.42 ; 37.8,17.19 v5(37.8,16.97) 38.02,16.97 ; 10.32,58.85 JMEDIA1.56 ; JMEDIA1.56 10.79,57.84 ; JMEDIA1.56 11.27,58.85 ; JMEDIA1.56 10.79,59.85 ; 41.28,30.55 v5(41.8,30.55) ; v5(41.8,30.55) 41.8,30.82 ; v5(41.8,30.55) 42.32,30.55 ; 29.84,53.94 v5(29.84,54.95) ; v5(29.84,54.95) 29.37,54.95 ; v5(29.84,54.95) 29.84,55.95 ; v5(29.84,54.95) 30.32,54.95 ; v5(34.13,20.88) 34.13,21.1 ; v5(34.13,20.88) 34.13,20.65 ; v5(34.13,20.88) 34.36,20.88 ; 27.27,34.28 v5(27.27,34.05) 27.5,34.05 ; C803.2 34.58,15.8 ; C803.2 34.36,15.57 ; C803.2 34.58,15.34 ; C1722.2 28.59,33.53 ; v5(29.29,38.19) 29.52,38.19 ; v5(29.29,38.19) 29.06,38.19 ; v5(29.29,38.19) 29.29,38.41 ; 30.92,37.14 v5(31.14,37.14) ; v5(31.14,37.14) 31.37,37.14 ; v5(31.14,37.14) 31.14,37.37 ; 31.67,32.47 C1742.2 31.21,32.47 ; 32.37,33.23 C1815.2 32.37,33.93 C1811.2 ; C1908.2 30.76,31.95 ; C1908.2 30.31,31.95 ; C1908.2 30.53,32.18 ; v5(41.27,54.95) 41.27,55.95 ; v5(41.27,54.95) 41.75,54.95 ; v5(41.27,54.95) 40.8,54.95 ; v5(41.27,54.95) 41.27,53.94 ; 26.23,33.85 v5(26.23,34.08) 26.23,34.31 ; U2611.3 42.79,49.7 ; 26.17,39 v5(26.17,38.6) 25.82,38.6 ; v5(16.13,27.38) 16.36,27.38 ; v5(16.13,27.38) 15.9,27.38 ; v5(16.13,27.38) 16.13,27.61 ; 17.94,58.85 JMEDIA1.44 ; JMEDIA1.44 18.41,59.85 ; JMEDIA1.44 18.89,58.85 ; JMEDIA1.44 18.41,57.84 ; C1935.2 31.68,38.89 ; C1935.2 31.46,38.67 ; C1935.2 31.91,38.67 ; 31.05,31.2 C1933.2 ; 49.75,42.16 JDIGITAL1.15 ; JDIGITAL1.15 50.8,43.21 ; JDIGITAL1.15 50.8,41.11 ; 40.8,58.85 v5(41.27,58.85) ; v5(41.27,58.85) 41.27,59.85 ; v5(41.27,58.85) 41.75,58.85 ; v5(41.27,58.85) 41.27,57.84 ; 27.23,13.54 v5(27.41,13.54) ; v5(27.41,13.54) 27.41,13.31 ; v5(27.41,13.54) 27.41,13.77 ; 6.3,6.46 C2625.2 6.6,6.15 ; 46.18,32.45 v5(46.18,32.68) ; v5(46.18,32.68) 45.95,32.68 ; v5(46.18,32.68) 46.41,32.68 ; 30.27,34.85 C1814.2 30.27,35.3 ; v5(29.03,63.8) 29.34,63.8 ; v5(29.03,63.8) 29.03,64.06 ; v5(29.03,63.8) 28.72,63.8 ; D26093.1 v5(13.94,14.02) D26094.1 ; D26093.1 14.42,14.28 ; D26093.1 15.66,14.02 ; 29.23,13.3 v5(29.23,13.53) 29.41,13.53 ; 29.2,33.48 C1823.2 29.43,33.25 ; 15.15,19.54 v5(15.15,19.85) ; v5(15.15,19.85) 15.45,19.85 ; v5(15.15,19.85) 14.85,19.85 ; 30.78,33.72 30.78,33.49 30.56,33.49 ; 45.73,34.97 v5(45.96,34.97) ; v5(45.96,34.97) 45.96,35.2 ; v5(45.96,34.97) 45.96,34.74 ; 30.42,34.01 C1809.2 30.19,34.23 ; 24.44,13.74 v5(24.62,13.74) ; v5(24.62,13.74) 24.62,13.51 ; v5(24.62,13.74) 24.62,13.98 ; v5(43.52,48.03) 43.52,48.29 ; v5(43.52,48.03) 43.21,48.03 ; v5(43.52,48.03) 43.83,48.03 ; 30.02,31.72 C1711.2 30.25,31.95 ; v5(30.08,37.14) 30.31,37.14 ; v5(30.08,37.14) 30.08,37.37 ; v5(30.08,37.14) 29.86,37.14 ; 45.89,43.46 v5(46.19,43.46) ; v5(46.19,43.46) 46.19,43.15 ; v5(46.19,43.46) 46.49,43.46 ; C2618.2 5.68,58.52 ; C2618.2 5.25,58.09 ; C2618.2 6.11,58.09 ; v5(34.98,29.76) 35.33,29.76 ; v5(34.98,29.76) 34.98,30.16 ; v5(34.98,29.76) 34.98,29.36 ; 31.72,61.13 D26048.1 ; D26048.1 31.72,61.75 ; D26048.1 31.98,61.44 ; 31.1,30.69 C1932.2 31.1,31.14 ; 33.53,60.66 JUSB1.S2 ; JUSB1.S2 32.87,61.86 ; JUSB1.S2 33.53,63.06 ; 32.12,35.75 C1733.2 32.12,35.4 32.23,35.28 v5(32.23,34.97) 32.23,34.51 C1914.2 ; C2215.2 46.85,29.09 ; C2215.2 46.5,29.49 ; C2215.2 46.5,28.69 ; 29.84,11.98 30.24,11.98 ; 29.84,11.98 29.84,12.91 ; 29.84,11.98 29.45,11.98 ; 29.84,11.98 29.84,11.06 ; v5(33.66,58.85) 34.13,58.85 ; v5(33.66,58.85) 33.66,59.85 ; v5(33.66,58.85) 33.18,58.85 ; v5(33.66,58.85) 33.66,57.84 ; 7.95,27.86 C2512.2 7.65,28.09 v5(7.44,28.3) ; 11.42,32.07 v5(11.73,32.07) 11.73,32.37 ; v5(38.55,35.4) 38.55,35.63 ; v5(38.55,35.4) 38.55,35.17 ; v5(38.55,35.4) 38.32,35.4 ; C1913.2 31.13,37.87 ; C1913.2 31.13,37.42 ; C1913.2 30.91,37.65 ; C1907.2 30.06,31.16 ; C1907.2 30.01,30.88 C1844.2 ; C1907.2 29.83,30.93 ; C1907.2 30.06,30.71 ; 25.13,35.74 C1919.2 ; C1919.2 25.35,35.52 ; C1919.2 25.35,35.97 ; 26.4,35.33 C1704.2 26.4,34.88 ; C2626.2 8.62,13.6 D26101.1 8.82,13.54 ; C2626.2 8.62,14.4 ; C2626.2 v5(9.89,14.1) ; v5(24.68,31.41) 24.91,31.41 ; 32.74,29.45 v5(32.74,29.68) ; v5(32.74,29.68) 32.74,29.91 ; v5(32.74,29.68) 32.97,29.68 ; 16.6,23.42 C2515.2 17.2,23.42 ; C1811.2 32.34,34.19 ; C1811.2 32.34,33.74 ; C1811.2 32.26,34.04 C1914.2 ; 38.17,27.43 C2204.2 ; C2204.2 38.17,27.88 ; C2204.2 37.94,27.66 ; 28.42,30.34 C1725.2 ; 7.18,6.25 D26100.1 7.49,6.51 ; 12.42,20.14 v5(12.42,20.45) ; 32.44,38.12 32.37,38.12 v5(32.64,38.4) ; 17.14,20.45 v5(17.14,20.75) 17.45,20.75 ; 30.92,32.23 C1835.2 ; C1835.2 30.69,32.46 ; C1835.2 31.14,32.46 ; D26091.1 17.01,14.27 ; D26091.1 17.14,14.01 v5(17.38,14.25) ; D26091.1 16.7,14.01 ; D26091.1 17,14.02 D26092.1 ; 22.52,22.3 v5(22.72,22.3) ; 33.84,37.65 v5(33.84,37.42) 34.07,37.42 ; v5(9.37,29.78) 9.39,29.76 9.39,29.17 C2514.2 9.68,29.18 ; 35.51,53.41 C3028.2 35.82,53.72 ; 28.57,7.16 v5(28.57,8.08) ; v5(28.57,8.08) 28.18,8.08 ; v5(28.57,8.08) 28.97,8.08 ; 28.24,38.14 C1833.2 28.24,37.68 ; 12.5,18.62 12.5,18.79 11.61,19.68 v5(11.05,19.68) 11.05,20.55 v5(10.9,20.7) ; 12.5,18.62 v5(12.5,16.07) ; 40.42,37.13 v5(40.42,37.36) ; v5(40.42,37.36) 40.42,37.58 ; v5(40.42,37.36) 40.65,37.36 ; R2113.2 v5(34.1,23.93) ; R2113.2 34.33,24.25 ; R2113.2 33.87,24.25 ; 34.05,33.32 C2203.2 ; C2203.2 34.28,33.55 ; C2203.2 34.05,33.78 ; 39.17,53.07 v5(38.87,53.07) 38.87,53.38 ; 16.89,41.87 v5(17.19,41.87) 17.19,42.18 ; 34.59,23.35 v5(34.59,23.58) ; v5(34.59,23.58) 34.81,23.58 ; v5(34.59,23.58) 34.59,23.81 ; 9.52,11.98 9.52,12.98 ; 9.52,11.98 9.52,10.98 ; 9.52,11.98 9.05,11.98 ; 9.52,11.98 10,11.98 ; 25.35,36.05 C1920.2 ; C1920.2 25.13,36.28 ; C1920.2 25.35,36.51 ; v5(42.2,31.45) 42.43,31.45 ; v5(42.2,31.45) 42.2,31.22 ; v5(42.2,31.45) 41.97,31.45 ; v5(44.05,33.4) 44.05,33.63 ; v5(44.05,33.4) 44.05,33.17 ; v5(44.05,33.4) 43.82,33.4 ; 17.47,36.7 v5(17.47,36.4) 17.78,36.4 ; v5(17.65,13.99) C2624.2 17.65,13.34 ; v5(28.78,32.98) 29.01,32.98 ; v5(28.78,32.98) 28.78,32.75 ; v5(28.78,32.98) 28.78,33.21 ; v5(34.13,20.24) 34.36,20.24 ; v5(34.13,20.24) 34.13,20.01 ; v5(34.13,20.24) 34.13,20.47 ; C2622.2 11.99,14.08 C2621.2 ; C2622.2 12,14.38 ; C2622.2 11.7,14.07 ; C2622.2 12.29,14.07 v5(12.29,14.07) ; JMEDIA1.14 37.94,58.85 ; JMEDIA1.14 36.99,58.85 ; JMEDIA1.14 37.47,59.85 ; JMEDIA1.14 37.47,57.84 ; 28.84,29.37 C1707.2 28.84,28.57 ; v5(6.62,58.09) 6.62,58.52 ; v5(6.62,58.09) 7.05,58.09 ; v5(6.62,58.09) 6.19,58.09 ; 18.62,5.81 v5(18.62,6.06) ; v5(18.62,6.06) 18.94,6.06 ; v5(18.62,6.06) 18.31,6.06 ; JSPI1.6 26.47,2.37 ; JSPI1.6 24.36,2.37 ; JSPI1.6 25.41,3.43 ; v5(40,34.55) 40,34.82 ; v5(40,34.55) 39.48,34.55 ; v5(40,34.55) 40.52,34.55 ; 21.75,58.85 JMEDIA1.38 ; JMEDIA1.38 22.23,57.84 ; JMEDIA1.38 22.7,58.85 ; JMEDIA1.38 22.23,59.85 ; 18.67,31.81 v5(18.97,31.81) ; v5(18.97,31.81) 19.27,31.81 ; v5(18.97,31.81) 18.97,31.5 ; 22.15,13.72 v5(22.33,13.72) ; v5(22.33,13.72) 22.33,13.95 ; v5(22.33,13.72) 22.33,13.48 ; v5(32.13,35.6) 32.34,35.81 C1810.2 32.57,36.06 ; 26.22,34.82 v5(26.22,34.59) 26.22,34.36 ; 25.12,35.23 C1939.2 ; C1939.2 25.17,35.06 C1918.2 25.17,34.49 ; C1939.2 25.34,35.46 ; 36.99,38.41 v5(37.21,38.41) ; v5(37.21,38.41) 37.21,38.63 ; v5(37.21,38.41) 37.21,38.18 ; C1728.2 28.78,38.42 ; C1728.2 29.01,38.19 ; C1728.2 28.55,38.19 ; 31.18,30.17 C1930.2 31.18,30.63 ; 30.39,37.14 C1818.2 ; C1818.2 30.61,37.37 ; C1818.2 30.84,37.14 ; v5(33.77,30.73) 33.99,30.73 ; v5(33.77,30.73) 33.77,30.95 ; v5(33.77,30.73) 33.77,30.5 ; C1841.2 26.07,31.6 ; C1841.2 25.84,31.82 ; C1841.2 25.61,31.6 ; 34.68,62.36 JUSB1.S4 33.83,63.06 ; 14.62,60.29 v5(14.62,61.22) ; v5(14.55,19.13) v5(14.55,20.42) ; v5(14.55,19.13) 14.55,18.82 ; v5(14.55,19.13) 15.93,19.13 17.37,17.68 v5(17.37,16.08) 17.04,15.75 12.83,15.75 v5(12.5,16.07) ; v5(40.9,34.45) 41.13,34.45 ; v5(40.9,34.45) 40.9,34.68 ; v5(40.9,34.45) 40.67,34.45 ; 33.27,29.47 v5(33.27,29.69) ; v5(33.27,29.69) 33.5,29.69 ; v5(33.27,29.69) 33.04,29.69 ; 32.74,30.42 v5(32.74,30.19) 32.74,29.96 ; JUSB1.S1 42.82,61.86 ; JUSB1.S1 42.17,60.66 ; JUSB1.S1 42.17,63.06 ; 30.35,37.44 v5(30.35,37.67) 30.58,37.67 ; 16.59,20.45 v5(16.59,20.75) 16.28,20.75 ; C2620.2 10.2,60.95 ; C2620.2 10.2,60.35 ; C2620.2 10.51,60.65 ; JMEDIA1.19 33.66,55.95 ; JMEDIA1.19 33.66,53.94 ; JMEDIA1.19 33.18,54.95 ; JMEDIA1.19 34.13,54.95 ; 1.57,27.94 JANALOG1.6 ; JANALOG1.6 2.54,26.97 ; JANALOG1.6 3.51,27.94 ; v5(21.41,15.09) 21.72,15.09 ; v5(21.41,15.09) 21.41,15.39 ; v5(21.41,15.09) 21.41,14.79 ; 14.28,32 v5(14.58,32) ; 25.56,54.95 v5(26.04,54.95) ; v5(26.04,54.95) 26.04,55.95 ; v5(26.04,54.95) 26.51,54.95 ; v5(26.04,54.95) 26.04,53.94 ; 8.16,33.53 v5(8.78,33.53) ; v5(8.78,33.53) 8.78,33 ; v5(8.78,33.53) 9.41,33.53 ; 41.41,66.41 JUSB1.S5 ; JUSB1.S5 42.17,67.91 ; JUSB1.S5 42.92,66.41 ; JUSB1.S5 42.17,64.91 ; v5(26.91,31.36) 26.91,31.59 ; v5(26.91,31.36) 26.68,31.36 ; v5(26.91,31.36) 26.91,31.13 ; Y2501.2 9.26,17.09 ; Y2501.2 10.11,16.34 ; Y2501.2 9.26,15.59 ; v5(38.14,18.31) 38.37,18.31 ; v5(38.14,18.31) 37.92,18.31 ; v5(38.14,18.31) 38.14,18.08 ; 14.13,54.95 v5(14.61,54.95) ; v5(14.61,54.95) 15.08,54.95 ; v5(14.61,54.95) 14.61,53.94 ; v5(14.61,54.95) 14.61,55.95 ; v5(40.7,39.75) 40.7,39.98 ; v5(40.7,39.75) 40.47,39.75 ; v5(40.7,39.75) 40.93,39.75 ; 38.13,29.18 v5(38.13,29.41) ; v5(38.13,29.41) 38.13,29.63 ; v5(38.13,29.41) 38.36,29.41 ; 15.86,44.68 v5(15.86,45.28) ; v5(15.86,45.28) 15.86,45.88 ; v5(15.86,45.28) 15.51,45.28 ; v5(15.86,45.28) 16.21,45.28 ; 21.13,13.4 v5(21.13,13.71) 21.13,14.02 ; 25.56,58.85 JMEDIA1.32 ; JMEDIA1.32 26.51,58.85 ; JMEDIA1.32 26.04,59.85 ; JMEDIA1.32 26.04,57.84 ; 6.87,53.7 6.91,53.7 v5(6.92,53.69) ; v5(40.36,31.38) 40.59,31.38 ; v5(40.36,31.38) 40.36,31.15 ; v5(40.36,31.38) 40.36,31.6 ; 27.89,35.38 28.06,35.55 v5(28.06,35.61) ; 33.35,36.57 C1902.2 33.58,36.35 ; v5(40.52,27.53) 40.52,27.76 ; v5(40.52,27.53) 40.75,27.53 ; v5(40.52,27.53) 40.52,27.3 ; 5.93,43.84 v5(6.23,43.84) ; v5(6.23,43.84) 6.23,44.15 ; v5(6.23,43.84) 6.53,43.84 ; C1820.2 29.75,37.14 ; C1820.2 29.52,37.36 ; C1820.2 29.3,37.14 ; 26.68,31.9 v5(26.91,31.9) 26.91,31.67 ; C1839.2 33.62,32.5 ; C1839.2 33.62,32.04 ; C1839.2 33.85,32.27 ; 33.62,32.58 C1850.2 ; C1850.2 33.62,33.04 ; C1850.2 33.85,32.81 ; 35.05,34.13 C2210.2 ; C2210.2 35.05,34.59 ; C2210.2 35.28,34.36 ; 33.1,34.24 32.85,34.49 C1738.2 ; 26.15,37.16 v5(26.38,37.16) 26.6,37.16 ; JANALOG1.7 2.54,26.45 ; JANALOG1.7 3.59,25.4 ; JANALOG1.7 2.54,24.35 ; JANALOG1.7 1.49,25.4 ; D26094.1 13.15,14.28 ; D26094.1 12.84,14.02 ; v5(41,31.95) 41.23,31.95 ; v5(41,31.95) 40.77,31.95 ; v5(41,31.95) 41,32.18 ; D26087.1 26.41,13.74 ; D26087.1 26.23,13.98 ; D26087.1 26.23,13.51 ; 12.86,31.68 v5(13.34,31.68) ; v5(13.34,31.68) 13.82,31.68 ; v5(13.34,31.68) 13.34,32.11 ; C1701.2 30.6,32.46 ; 6.5,37.64 v5(6.81,37.64) 7.11,37.64 ; 27.58,34.04 v5(27.8,34.04) 27.8,34.26 ; 25.09,31.41 v5(25.32,31.41) ; 25.93,33.02 v5(25.7,33.02) 25.7,33.25 ; C2621.2 11.35,14.39 ; C2621.2 11.25,13.98 D26097.1 ; v5(44.9,32.55) 44.9,32.82 ; v5(44.9,32.55) 44.38,32.55 ; v5(44.9,32.55) 45.42,32.55 ; 26.49,33.01 v5(26.72,33.01) ; v5(26.72,33.01) 26.95,33.01 ; v5(26.72,33.01) 26.72,32.78 ; 37.68,33.25 v5(38.2,33.25) ; v5(38.2,33.25) 38.2,32.98 ; v5(38.2,33.25) 38.72,33.25 ; v5(37.12,32.55) 37.34,32.55 ; v5(37.12,32.55) 37.12,32.78 ; v5(37.12,32.55) 37.12,32.33 ; 28.5,31.67 C1713.2 ; C1713.2 28.5,32.13 ; C1713.2 28.72,31.9 ; 16.36,25.88 v5(16.66,25.88) ; 6.83,21.41 v5(7.14,21.41) v5(7.47,21.41) v5(7.72,21.41) ; 15.66,14.02 v5(15.39,14.29) ; 15.66,14.02 D26092.1 ; 30.14,29.57 C1904.2 30.37,29.79 ; 25.2,32.26 v5(25.2,32.49) 24.98,32.49 ; 12.22,35.89 v5(12.22,36.2) 11.91,36.2 ; 7.96,26.21 v5(7.62,26.21) 7.62,25.91 ; 15.09,44.34 v5(15.09,44.77) 15.09,45.2 ; 32.74,30.47 C1926.2 32.74,30.93 ; 32.31,35.24 32.31,34.79 ; 15.4,6.44 D26074.1 ; D26074.1 v5(15.66,6.69) ; D26074.1 15.66,6.13 ; v5(11.17,19.16) 11.48,19.16 ; v5(11.17,19.16) 11.17,18.86 ; v5(11.17,19.16) 11.17,19.47 ; 45.09,53.94 JMEDIA1.1 ; JMEDIA1.1 44.61,54.95 ; JMEDIA1.1 45.56,54.95 ; JMEDIA1.1 45.09,55.95 ; 45.09,59.85 v5(45.09,58.85) 44.61,58.85 ; C2631.2 5.77,44.96 ; C2631.2 5.77,44.1 ; C2631.2 v5(6.17,44.53) ; 25.18,34.41 C1851.2 25.18,33.95 ; 14.16,6.44 D26075.1 ; D26075.1 14.41,6.66 v5(14.41,6.66) ; D26075.1 14.41,6.13 ; 26.03,29.13 v5(26.03,29.53) ; v5(26.03,29.53) 26.03,29.93 ; v5(26.03,29.53) 25.68,29.53 ; 34.59,22.72 v5(34.59,22.95) ; v5(34.59,22.95) 34.81,22.95 ; v5(34.59,22.95) 34.59,23.17 ; 28.78,32.22 C1710.2 28.78,32.68 ; C1808.2 30.29,35.6 ; C1808.2 30.06,35.83 ; C1808.2 30.06,35.37 ; 40.93,49.7 v5(41.86,49.7) ; 14.31,29.09 v5(14.61,29.09) 14.61,28.78 ; 12.84,6.44 D26076.1 ; D26076.1 13.09,6.66 v5(13.09,6.66) ; D26076.1 13.09,6.13 ; 26.6,35.64 C1940.2 26.38,35.41 ; 12.22,37.08 v5(12.22,36.78) 11.91,36.78 ; 20.21,5.2 v5(20.21,4.89) 19.95,4.89 ; v5(38.98,14.53) 38.98,14.76 ; v5(38.98,14.53) 38.98,14.3 ; v5(38.98,14.53) 38.75,14.53 ; 26.01,51.75 v5(26.01,52.24) ; v5(39.79,38.47) 39.79,38.7 ; v5(39.79,38.47) 40.02,38.47 ; v5(39.79,38.47) 39.79,38.24 ; 43.1,30.98 v5(43.1,31.25) ; v5(43.1,31.25) 42.58,31.25 ; v5(43.1,31.25) 43.62,31.25 ; 33.87,35.39 C1916.2 33.87,34.93 ; 30.11,61.43 v5(30.37,61.43) 30.37,61.12 ; v5(26.05,62.56) 26.05,63.05 ; 15.15,28.78 v5(15.15,29.09) 15.45,29.09 ; v5(18.41,54.95) 18.41,55.95 ; v5(18.41,54.95) 18.41,53.94 ; v5(18.41,54.95) 18.89,54.95 ; v5(18.41,54.95) 17.94,54.95 ; D26201.1 7.04,46.23 ; D26201.1 6.52,45.86 ; D26201.1 7.04,45.49 ; 26.61,30.28 C1721.2 26.84,30.51 ; v5(38.26,39.07) 38.49,39.07 ; v5(38.26,39.07) 38.26,38.85 ; v5(38.26,39.07) 38.26,39.3 ; 28.74,30.31 C1718.2 28.97,30.08 ; C1740.2 29.01,37.37 ; C1740.2 29.23,37.14 ; C1740.2 29.01,36.91 ; 35.61,50.18 v5(35.61,50.48) ; v5(44.67,47.75) 44.98,47.75 ; v5(44.67,47.75) 44.36,47.75 ; v5(44.67,47.75) 44.67,48.01 ; C1914.2 32.26,34.71 ; 34.58,49.73 v5(34.58,50.04) 34.88,50.04 ; 15.82,19.54 v5(15.82,19.85) 15.51,19.85 ; D26092.1 15.7,14.28 ; C1806.2 27.96,36.8 C1805.2 27.95,37.03 ; v5(18.39,52.68) 18.39,53.61 ; 16.31,23.27 v5(16.31,23.5) ; v5(16.31,23.5) 16.08,23.5 ; v5(16.31,23.5) 16.53,23.5 ; v5(29.22,23.3) 29.42,23.3 ; U2610.8 26.01,53.61 ; D26097.1 10.75,14.24 ; D26097.1 10.44,13.98 ; v5(15,43.75) 15,44.05 ; v5(15,43.75) 15,43.45 ; v5(15,43.75) 15.31,43.75 ; 27.14,37.16 v5(26.92,37.16) 26.69,37.16 ; 7.27,38.96 v5(7.57,38.96) ; 6.38,30.02 v5(6.68,30.02) ; v5(6.68,30.02) 6.98,30.02 ; v5(6.68,30.02) 6.68,29.72 ; 27.26,32.75 C1717.2 ; C1717.2 27.26,33.21 ; C1717.2 27.03,32.98 ; 36.77,15.66 C901.2 37,15.43 ; C1723.2 28.63,29.95 ; C1723.2 28.4,30.17 ; C1723.2 28.4,29.72 ; v5(13.39,53.4) 13.39,53.71 ; 18.39,51.75 v5(18.39,52.24) ; 33.86,34.4 C1915.2 33.86,34.86 ; 20.33,6.15 D26070.1 20.33,6.77 ; 33.87,35.44 v5(33.87,35.67) ; C1834.2 26.35,31.83 ; C1834.2 26.58,31.6 ; C1834.2 26.13,31.6 ; 32.08,33.05 C1731.2 32.08,32.59 ; 30.03,31.67 C1910.2 30.03,31.21 ; 21.27,6.14 v5(21.27,6.45) 21.27,6.76 ; 37.63,36.18 v5(37.63,36.4) ; v5(37.63,36.4) 37.63,36.63 ; v5(37.63,36.4) 37.85,36.4 ; 34.36,16.07 C804.2 ; C804.2 34.58,15.85 ; C804.2 34.58,16.3 ; 9.35,19.81 v5(9.04,19.81) 9.04,19.51 ; C1848.2 32.78,37.59 ; 45.29,30.16 v5(45.29,30.39) 45.52,30.39 ; 33.65,31.12 C1925.2 33.65,31.58 ; v5(40,29.25) 40.52,29.25 ; v5(40,29.25) 40,28.98 ; v5(40,29.25) 39.48,29.25 ; EMMC1.H10 v5(26.23,20.05) ; C1709.2 27.26,32.67 ; v5(27.99,36.12) 27.99,35.63 C1813.2 ; 22.49,5.15 v5(22.49,4.91) 22.67,4.91 ; 25.13,36.82 v5(25.35,36.82) ; v5(25.35,36.82) 25.35,36.59 ; v5(25.35,36.82) 25.35,37.05 ; v5(29.22,22.3) 29.42,22.3 ; 8.18,19.81 v5(8.48,19.81) 8.48,19.51 ; 26.71,35.64 C1924.2 ; 31.98,37.11 v5(32.21,37.11) ; 26.87,30.59 C1714.2 26.87,31.05 ; v5(15.11,32) 15.11,32.31 ; 34.29,30.52 v5(34.29,30.74) ; v5(34.29,30.74) 34.06,30.74 ; v5(34.29,30.74) 34.51,30.74 ; C1715.2 28.5,31.59 ; 29.2,34.31 C1735.2 29.23,34.57 v5(29.23,35.06) 29.23,35.21 29.01,35.43 C1734.2 C1732.2 C1741.2 29.01,36.86 ; 28.87,29.77 C1838.2 ; C1838.2 29.1,30 ; C1838.2 29.1,29.55 ; 25.7,33.76 v5(25.7,33.53) 25.7,33.3 ; 31.13,29.15 C1931.2 ; 29.52,32.97 C1716.2 29.07,32.97 ; 26.05,61.19 v5(26.05,62.12) ; 14.61,57.84 14.61,58.85 ; 14.61,58.85 14.61,59.85 ; 14.61,58.85 14.13,58.85 ; 14.61,58.85 15.08,58.85 ; v5(38.5,31.85) 38.73,31.85 ; v5(38.5,31.85) 38.5,32.08 ; v5(38.5,31.85) 38.27,31.85 ; v5(36.34,53.41) 36.34,53.72 ; 8.97,41.59 v5(9.6,41.59) ; v5(9.6,41.59) 9.6,41.07 ; v5(9.6,41.59) 10.23,41.59 ; 33.63,51.75 U2606.3 ; 29.6,38.19 v5(29.83,38.19) 29.83,38.41 ; v5(14.62,61.66) 14.62,62.15 ; 16.33,25.88 v5(16.1,25.88) 15.88,25.88 ; 36.27,17.69 v5(36.49,17.69) ; v5(36.49,17.69) 36.49,17.91 ; v5(36.49,17.69) 36.49,17.46 ; 30.03,35.88 C1819.2 30.04,36.12 C1739.2 ; 32.08,32.54 C1903.2 31.85,32.31 ; 27.41,34.56 v5(27.63,34.56) ; v5(36.85,53.41) 36.85,53.72 ; 19.19,6.46 D26071.1 ; D26071.1 19.44,6.77 ; D26071.1 19.44,6.15 ; C1845.2 32.21,38.35 ; 45.98,31.44 v5(46.21,31.44) ; v5(46.21,31.44) 46.21,31.21 ; v5(46.21,31.44) 46.44,31.44 ; v5(37.8,53.06) 37.8,53.37 ; v5(38.31,53.07) 38.31,53.38 ; C1937.2 33.32,37.94 ; C1937.2 33.55,37.71 ; C1937.2 33.1,37.71 ; 30.56,35.04 30.78,35.04 ; 30.09,34.75 C1816.2 30.09,34.3 ; 31.05,32.16 C1817.2 30.82,31.93 ; v5(12.91,53.38) 12.91,53.69 ; 14.84,37.77 v5(15.14,37.77) ; 26.21,32.78 C1826.2 26.44,33.01 ; 23.49,7.16 v5(23.49,8.08) ; v5(23.49,8.08) 23.89,8.08 ; v5(23.49,8.08) 23.1,8.08 ; 11.46,17.29 Y2501.4 ; Y2501.4 11.46,18.79 ; Y2501.4 12.31,18.04 ; Y2501.4 10.61,18.04 ; MCU1.B2 v5(14.22,21.95) ; 29.01,32.15 C1901.2 28.78,31.92 ; 29.62,32.96 C1712.2 ; 18.13,36.3 v5(18.43,36.3) ; C1727.2 32.08,32.03 ; v5(41.3,52.58) 41.3,53.51 ; 28.71,62.49 v5(29.02,62.49) 29.02,62.23 ; 32.62,31.05 C1927.2 ; v5(32.84,37.48) 32.84,37.54 32.64,37.74 ; v5(16.81,22.07) 17.12,22.07 ; U2606.8 33.63,53.61 ; 16.42,42.65 C2808.2 16.85,42.22
  BOTTOM w0.4: 20.94,60.29 U2607.4 21.29,60.83 ; 20.94,62.15 v5(20.94,61.61) 21.29,61.61 ; 44.71,42.51 v5(44.71,43.11)
  BOTTOM w0.6: 10.97,42.03 v5(11.7,42.03) 12.42,42.03 ; 9.79,34.1 v5(10.52,34.1) 11.25,34.1 ; U2802.5 13.7,34.1
  vias: v1(0.76,53.61) v1(0.76,47.26) v1(0.76,45.99) v1(0.76,44.72) v1(0.76,43.45) v1(0.76,42.18) v1(0.76,40.91) v1(0.76,39.64) v1(0.76,38.37) v1(0.76,37.1) v1(0.76,35.83) v1(0.76,34.56) v1(0.76,33.29) v1(0.76,32.02) v1(0.76,30.75) v1(0.76,29.48) v1(0.76,28.21) v1(0.76,26.94) v1(0.76,25.67) v1(0.76,24.4) v1(0.76,23.13) v1(0.76,21.86) v1(0.76,20.59) v1(0.76,19.32) v1(0.76,18.05) v1(0.76,16.78) v1(0.76,15.51) v1(0.76,14.24) v1(0.76,12.97) v1(0.76,11.7) v1(0.76,10.43) v1(1.37,48.73) v1(1.55,49.76) v1(1.58,39.7) v1(1.65,34.38) v1(1.68,52.27) v1(1.72,50.85) v1(1.67,41.74) v1(1.68,36.84) v1(1.68,31.79) v1(1.76,29.18) v1(1.83,8.85) v1(1.77,3.3) v1(2.52,48.89) v1(2.48,41.91) v1(2.73,60.59) v1(2.67,50.3) v1(2.97,51.45) v1(3.02,3.13) v1(3.25,63.33) v1(3.22,8.94) v1(3.44,29.2) v1(3.45,52.45) v1(3.54,34.32) v1(3.45,32.01) v1(3.5,26.43) v1(3.46,17.07) v1(3.5,16.1) v1(3.52,14.64) v1(3.46,11.38) v1(3.56,62.46) v1(3.56,49.53) v1(3.59,48.59) v1(3.62,47.27) v1(3.6,46.72) v1(3.65,45.42) v1(3.63,41.1) v1(3.56,36.85) v1(3.68,60.48) v1(3.65,44.31) v1(3.68,39.66) v1(3.82,59.69) v1(3.81,56.73) v1(4.22,48.95) v1(4.25,47.56) v1(4.25,46.33) v1(4.25,45.27) v1(4.43,57.74) v1(4.36,2.77) v1(4.54,56.58) v1(4.46,55.7) v1(4.53,10.86) v1(4.54,8.9) v1(4.56,62.15) v1(4.78,54.8) v1(4.75,53.59) v1(4.83,52.13) v1(4.84,50.25) v1(4.85,6.97) v1(4.94,51.23) v1(4.91,49.54) v1(5.1,62.18) v1(5.13,57.12) v1(5.1,8.04) v1(5.17,52.91) v1(5.21,48.81) v1(5.21,47.51) v1(5.23,46.41) v1(5.2,44.88) v1(5.25,43.88) v1(5.21,9.57) v1(5.3,59.95) v1(5.29,55.77) v1(5.39,54.72) v1(5.36,48.17) v1(5.42,1.69) v1(5.49,53.98) v1(5.5,51) v1(5.54,50.2) v1(5.54,41) v1(5.71,62.2) v1(5.95,56.21) v1(5.91,47.54) v1(5.91,46.77) v1(5.86,9.23) v1(5.99,58.37) v1(6.13,50.02) v1(6.16,63.48) v1(6.16,4.32) v1(6.28,52.09) v1(6.28,7.75) v1(6.42,50.98) v1(6.48,63.96) v1(6.52,48.79) v1(6.79,62.19) v1(6.83,9.04) v1(7.01,63.96) v1(6.96,50.24) v1(7.16,59.84) v1(7.15,44.66) v1(7.15,7.43) v1(7.27,49.59) v1(7.38,61.58) v1(7.38,54.76) v1(7.39,52.48) v1(7.43,41.28) v1(7.55,63.96) v1(7.51,63.51) v1(7.52,61.97) v1(7.51,44.18) v1(7.52,43.54) v1(7.53,42.84) v1(7.51,41.97) v1(7.55,56.35) v1(7.58,53.56) v1(7.62,50.78) v1(7.63,45.22) v1(7.66,46.02) v1(7.74,39.66) v1(7.81,62.09) v1(7.83,59.34) v1(7.76,58.1) v1(7.81,55.58) v1(7.75,51.48) v1(7.83,49.51) v1(7.75,40.81) v1(7.87,6.4) v1(7.89,5.14) v1(8.04,38.73) v1(8,4.51) v1(8.08,63.96) v1(8.1,61.47) v1(8.09,44.19) v1(8.1,43.55) v1(8.11,42.85) v1(8.09,41.98) v1(8.15,48.78) v1(8.25,44.62) v1(8.28,56.36) v1(8.39,55.13) v1(8.43,53.51) v1(8.4,52.27) v1(8.41,51.13) v1(8.37,46.02) v1(8.46,59.64) v1(8.47,58.45) v1(8.52,54.4) v1(8.46,50.41) v1(8.49,0.76) v1(8.6,44.19) v1(8.61,43.55) v1(8.62,42.85) v1(8.6,41.98) v1(8.68,41.34) v1(8.8,49.53) v1(8.81,44.56) v1(8.87,62.11) v1(9.01,61.1) v1(9.01,52.24) v1(8.97,48.77) v1(9.12,46.05) v1(9.05,38.35) v1(9.24,49.33) v1(9.32,63.18) v1(9.33,40.66) v1(9.35,39.12) v1(9.51,6.82) v1(9.56,59.6) v1(9.63,58.24) v1(9.75,57.21) v1(9.82,55.93) v1(9.77,52.93) v1(9.81,52.24) v1(9.87,50.95) v1(9.94,45.29) v1(10.01,62.11) v1(9.97,61.05) v1(10.13,38.35) v1(10.19,61.55) v1(10.35,48.94) v1(10.29,43.85) v1(10.26,4) v1(10.43,5.96) v1(10.5,1.89) v1(10.6,63.26) v1(10.6,53.75) v1(10.6,44.51) v1(10.69,49.54) v1(10.89,61.55) v1(10.92,59.62) v1(10.9,58.58) v1(10.95,50.82) v1(11.03,62.29) v1(11.02,52.87) v1(10.96,50.22) v1(11.12,54.4) v1(11.06,51.37) v1(11.17,6.65) v1(11.29,62.93) v1(11.35,5.96) v1(11.31,2.58) v1(11.4,52.23) v1(11.52,61.93) v1(11.51,60.27) v1(11.49,59.28) v1(11.63,58.43) v1(11.58,51.15) v1(11.55,48.95) v1(11.79,50.48) v1(11.88,63.96) v1(11.99,62.95) v1(11.96,38.19) v1(12.09,6.53) v1(12.2,62.26) v1(12.24,60.19) v1(12.17,52.24) v1(12.32,59.06) v1(12.27,54.41) v1(12.43,63.95) v1(12.56,7.88) v1(12.74,58.41) v1(12.72,9.23) v1(12.77,52.28) v1(12.77,51.19) v1(12.84,50.49) v1(12.76,6.3) v1(12.81,1.44) v1(12.96,63.95) v1(12.97,4.01) v1(12.96,2.31) v1(13.16,48.99) v1(13.35,63.17) v1(13.5,63.95) v1(13.53,38.68) v1(13.49,8.64) v1(13.57,0.76) v1(13.7,59.27) v1(13.73,54.46) v1(13.79,52.99) v1(13.77,9.65) v1(14.01,63.95) v1(14.02,48.47) v1(14.11,7.82) v1(14.09,1.86) v1(14.23,60.59) v1(14.29,49.64) v1(14.43,62.68) v1(14.42,38.17) v1(14.49,51.45) v1(14.56,63.94) v1(14.62,61.73) v1(14.63,57.26) v1(14.63,55.26) v1(14.65,59.08) v1(14.65,47.84) v1(14.76,52.19) v1(14.84,0.76) v1(14.88,60.12) v1(14.86,48.85) v1(14.88,47.28) v1(14.93,38.74) v1(14.9,9.59) v1(14.98,63.25) v1(15.04,54.19) v1(15.09,63.94) v1(15.2,50.84) v1(15.29,59.67) v1(15.37,63.58) v1(15.41,49.53) v1(15.45,48.15) v1(15.52,62.66) v1(15.49,47.57) v1(15.46,2.29) v1(15.57,8.77) v1(15.55,7.97) v1(15.7,58.72) v1(15.73,57.99) v1(15.71,57.18) v1(15.71,56.53) v1(15.71,55.86) v1(15.7,55.19) v1(15.7,54.52) v1(15.73,38.33) v1(15.75,63.18) v1(15.76,1.32) v1(15.95,60.29) v1(15.9,50.98) v1(15.89,49.54) v1(16.02,63.73) v1(16.03,61.92) v1(16.05,52.87) v1(15.96,9.67) v1(16.11,0.76) v1(16.17,63.94) v1(16.22,7.67) v1(16.27,60.09) v1(16.3,59.16) v1(16.45,63.7) v1(16.55,5.04) v1(16.55,63.12) v1(16.59,62.67) v1(16.59,37.81) v1(16.61,9.04) v1(16.72,63.93) v1(16.69,54.8) v1(16.77,53.81) v1(16.98,63.69) v1(17.01,56.87) v1(17.1,61.94) v1(17.14,5.73) v1(17.25,63.93) v1(17.25,63.13) v1(17.25,53.97) v1(17.16,38.69) v1(17.18,7.32) v1(17.29,59.06) v1(17.41,53.14) v1(17.46,63.69) v1(17.57,48.1) v1(17.57,9.81) v1(17.7,62.65) v1(17.73,6.67) v1(17.79,63.93) v1(17.84,39.83) v1(17.95,56.85) v1(17.93,54.7) v1(17.93,46.08) v1(17.9,44.89) v1(17.88,43.03) v1(17.87,41.97) v1(18.04,63.69) v1(17.99,63.12) v1(18.05,59.06) v1(17.98,56.17) v1(17.96,55.53) v1(18,52.59) v1(17.98,37.31) v1(18.08,60.48) v1(18.06,58.05) v1(18.14,57.48) v1(18.23,58.42) v1(18.33,63.93) v1(18.27,53.61) v1(18.41,51.14) v1(18.39,48.41) v1(18.38,47.53) v1(18.46,50.41) v1(18.57,63.7) v1(18.61,59.05) v1(18.64,56.41) v1(18.64,54.91) v1(18.7,52.26) v1(18.72,10.06) v1(18.66,7.25) v1(18.69,5.99) v1(18.65,0.76) v1(18.77,63.12) v1(18.84,62.67) v1(18.76,44.02) v1(18.88,63.92) v1(18.86,62.14) v1(18.93,47.75) v1(18.93,38.31) v1(19,52.77) v1(19.14,63.63) v1(19.13,47.02) v1(19.2,45.58) v1(19.3,57.58) v1(19.34,56.32) v1(19.34,55.24) v1(19.41,63.92) v1(19.43,54.46) v1(19.38,52.29) v1(19.44,50.34) v1(19.54,63.25) v1(19.51,61.99) v1(19.46,51.17) v1(19.48,48.43) v1(19.53,47.12) v1(19.5,46.3) v1(19.61,59) v1(19.59,6.65) v1(19.82,62.79) v1(19.83,60.52) v1(19.95,63.92) v1(19.87,62.25) v1(19.91,44.46) v1(19.91,9.64) v1(19.92,0.76) v1(19.95,57.17) v1(20.02,6) v1(20.09,53.68) v1(20.11,48.33) v1(20.14,7.39) v1(20.49,63.92) v1(20.55,63.33) v1(20.54,45.62) v1(20.64,60.68) v1(20.62,58.97) v1(20.68,59.82) v1(20.73,58.02) v1(20.84,51) v1(20.84,49.92) v1(20.79,47.83) v1(20.8,47.13) v1(20.84,6.88) v1(20.94,48.34) v1(20.88,14.62) v1(21.04,63.91) v1(21.19,63.4) v1(21.24,37.62) v1(21.19,0.76) v1(21.25,44.98) v1(21.51,47.52) v1(21.49,17) v1(21.51,15.25) v1(21.48,14.52) v1(21.49,12.76) v1(21.49,12.03) v1(21.5,11.02) v1(21.48,10.25) v1(21.5,9.48) v1(21.57,63.91) v1(21.6,17.82) v1(21.75,57.02) v1(21.7,50.76) v1(21.77,63.28) v1(21.82,59.11) v1(21.8,58.21) v1(21.86,51.65) v1(21.89,49.87) v1(22.05,36.84) v1(22.11,63.91) v1(22.07,45.41) v1(22.25,15.6) v1(22.24,12.02) v1(22.22,11.03) v1(22.2,9.53) v1(22.23,7.38) v1(22.16,6.01) v1(22.29,59.68) v1(22.34,48.29) v1(22.27,12.76) v1(22.27,10.23) v1(22.39,14.02) v1(22.53,56.31) v1(22.5,55.35) v1(22.52,17.5) v1(22.65,63.91) v1(22.67,49.37) v1(22.73,44.8) v1(22.68,18.36) v1(22.83,61.06) v1(22.77,59.16) v1(22.9,62.73) v1(23.14,66.22) v1(23.05,63.36) v1(23.09,40.02) v1(23.09,38.41) v1(23.09,37.27) v1(23.14,16.38) v1(23.09,15.62) v1(23.11,13.97) v1(23.13,12.72) v1(23.23,64.69) v1(23.26,58.73) v1(23.32,13.29) v1(23.34,12.08) v1(23.3,6.88) v1(23.41,10.98) v1(23.52,58.2) v1(23.54,57) v1(23.55,17.5) v1(23.54,8.69) v1(23.59,67.82) v1(23.66,46.87) v1(23.73,44.69) v1(23.66,9.46) v1(23.83,66.94) v1(23.84,37.56) v1(23.83,12.99) v1(23.87,59.95) v1(23.98,55.87) v1(23.98,54.57) v1(24.02,53.02) v1(24.07,60.97) v1(24.11,51.45) v1(24.11,49.77) v1(24.16,48.68) v1(24.27,65.48) v1(24.29,10.96) v1(24.64,66.89) v1(24.6,48.19) v1(24.59,47.41) v1(24.61,45.67) v1(24.57,12.74) v1(24.6,12.05) v1(24.73,16.75) v1(24.71,10.44) v1(24.66,7.86) v1(24.86,67.82) v1(24.86,57.2) v1(24.91,34.14) v1(24.9,33.62) v1(25.02,50.55) v1(24.97,39.28) v1(24.97,38.48) v1(24.97,32.48) v1(24.97,31.68) v1(24.97,30.88) v1(24.97,30.08) v1(24.97,29.28) v1(25.08,59.41) v1(25.12,58.26) v1(25.06,53.8) v1(25.14,44.7) v1(25.16,60.54) v1(25.18,55.38) v1(25.25,52.12) v1(25.34,10.91) v1(25.45,62.7) v1(25.38,49.3) v1(25.39,48.18) v1(25.44,47.33) v1(25.4,34.17) v1(25.42,8.73) v1(25.49,66.44) v1(25.54,14.51) v1(25.48,9.62) v1(25.57,65.57) v1(25.57,50.01) v1(25.61,13.84) v1(25.62,13.34) v1(25.59,12.07) v1(25.72,63.24) v1(25.68,33.35) v1(25.8,15.57) v1(25.95,16.82) v1(26,67.14) v1(26.13,67.82) v1(26.11,47.48) v1(26.14,45.7) v1(26.15,38.1) v1(26.14,12.73) v1(26.14,10.13) v1(26.24,58.42) v1(26.16,56.37) v1(26.22,51.75) v1(26.18,49.38) v1(26.17,44.76) v1(26.17,39.28) v1(26.16,10.96) v1(26.26,63.24) v1(26.27,62.21) v1(26.26,61.41) v1(26.26,60.65) v1(26.27,55.04) v1(26.25,53.72) v1(26.3,8.7) v1(26.38,64.75) v1(26.43,18.32) v1(26.43,17.46) v1(26.41,16.36) v1(26.62,57.66) v1(26.63,36) v1(26.55,35.75) v1(26.57,29.28) v1(26.62,25.46) v1(26.72,15.57) v1(26.7,13.84) v1(26.73,12.26) v1(26.9,63.31) v1(26.87,62.47) v1(26.86,61.59) v1(26.89,55.88) v1(26.9,54.73) v1(26.93,53.43) v1(26.95,51.78) v1(26.9,49.64) v1(26.91,47.52) v1(26.92,45.85) v1(26.86,13.36) v1(26.96,63.99) v1(26.97,58.19) v1(26.97,39.28) v1(27,35.32) v1(27,28.02) v1(26.98,9.38) v1(27.07,66.33) v1(27.07,64.45) v1(27.05,37.3) v1(27.05,17.97) v1(27.05,10.92) v1(27.11,10.06) v1(27.2,14.47) v1(27.31,50.67) v1(27.4,67.82) v1(27.43,51.25) v1(27.39,36.06) v1(27.38,32.48) v1(27.35,18.9) v1(27.37,12.9) v1(27.37,12.1) v1(27.37,7.86) v1(27.54,54.99) v1(27.54,54.08) v1(27.54,0.76) v1(27.57,53.26) v1(27.55,52.42) v1(27.55,8.83) v1(27.69,44.75) v1(27.82,48.1) v1(27.78,11.56) v1(27.87,65.91) v1(27.9,55.5) v1(27.92,50.19) v1(28.02,67.23) v1(28,63.91) v1(28,62.1) v1(27.96,58.87) v1(28.11,64.81) v1(28.12,50.91) v1(28.25,60.34) v1(28.2,59.91) v1(28.16,59.35) v1(28.18,35.32) v1(28.25,63.27) v1(28.32,19.09) v1(28.33,15.12) v1(28.27,12.02) v1(28.45,59.19) v1(28.45,55.55) v1(28.44,20.2) v1(28.42,18.57) v1(28.42,15.77) v1(28.41,14.18) v1(28.39,13.38) v1(28.46,47.4) v1(28.53,34.43) v1(28.58,61.05) v1(28.61,58.73) v1(28.61,49.28) v1(28.67,67.82) v1(28.67,49.75) v1(28.7,20.81) v1(28.7,15.52) v1(28.7,11.17) v1(28.72,10.5) v1(28.79,58.17) v1(28.76,50.16) v1(28.8,18.26) v1(28.83,9.77) v1(28.81,0.76) v1(28.92,61.43) v1(28.88,55.83) v1(28.95,45.46) v1(29.04,66.28) v1(29,51.38) v1(29.01,50.95) v1(29.02,48.94) v1(29.13,19.43) v1(29.13,14.03) v1(29.09,12.11) v1(29.25,64.74) v1(29.16,62.99) v1(29.16,22.2) v1(29.34,61.59) v1(29.35,60.73) v1(29.33,59.22) v1(29.32,46.55) v1(29.44,58.85) v1(29.43,55.54) v1(29.42,50.12) v1(29.36,15.02) v1(29.44,9.37) v1(29.48,23.79) v1(29.54,21.89) v1(29.46,13.37) v1(29.55,60.43) v1(29.62,59.99) v1(29.64,51.79) v1(29.56,48.82) v1(29.65,25.74) v1(29.57,25.14) v1(29.57,19.08) v1(29.72,58.2) v1(29.73,26.39) v1(29.72,15.52) v1(29.76,48.01) v1(29.82,24.55) v1(29.82,18.59) v1(29.94,67.82) v1(29.88,62.17) v1(29.9,61.59) v1(29.86,60.85) v1(29.9,60.44) v1(29.92,10.8) v1(30,67.33) v1(30,27.8) v1(29.96,9.91) v1(29.98,7.83) v1(30.1,63.52) v1(30.07,55.82) v1(30.12,26.96) v1(30.11,14.39) v1(30.07,11.65) v1(30.08,0.76) v1(30.24,62.72) v1(30.16,59.05) v1(30.24,57.45) v1(30.22,50.48) v1(30.19,47.56) v1(30.2,30.4) v1(30.2,26.58) v1(30.18,21.89) v1(30.31,51.4) v1(30.32,18.66) v1(30.39,58.76) v1(30.38,48.26) v1(30.43,25.55) v1(30.43,25) v1(30.48,26.06) v1(30.52,9.35) v1(30.55,61.83) v1(30.55,58.06) v1(30.59,55.55) v1(30.57,49.44) v1(30.56,22.23) v1(30.58,19.08) v1(30.57,11.14) v1(30.72,47.7) v1(30.74,46.96) v1(30.77,63.4) v1(30.84,25.74) v1(30.88,59.06) v1(30.9,57.22) v1(30.91,25.11) v1(30.91,24.57) v1(30.89,13.88) v1(30.93,10.3) v1(31.04,27.08) v1(31.11,48.73) v1(31.08,28.02) v1(31.14,23.8) v1(31.16,61.8) v1(31.17,55.86) v1(31.24,50.31) v1(31.19,18.9) v1(31.2,13.39) v1(31.27,58.76) v1(31.27,58.04) v1(31.33,11.54) v1(31.42,49.67) v1(31.37,39.28) v1(31.36,37.29) v1(31.45,30.9) v1(31.36,29.65) v1(31.39,22.12) v1(31.41,10.76) v1(31.35,0.76) v1(31.5,60.45) v1(31.5,48.13) v1(31.51,40.3) v1(31.54,10.29) v1(31.52,9.31) v1(31.58,64.44) v1(31.64,63.43) v1(31.65,55.54) v1(31.59,46.79) v1(31.58,27.05) v1(31.67,59.09) v1(31.7,57.74) v1(31.66,57.2) v1(31.74,25.84) v1(31.73,25.27) v1(31.76,24.47) v1(31.8,19.58) v1(31.83,19.28) v1(31.9,62.99) v1(31.9,62.33) v1(31.88,61.78) v1(31.91,5.65) v1(31.91,2.19) v1(32.04,60.11) v1(32.12,60.83) v1(32.22,57.76) v1(32.17,55.88) v1(32.17,55.53) v1(32.17,28.88) v1(32.16,18.85) v1(32.28,63.51) v1(32.28,59.37) v1(32.29,48.67) v1(32.33,46.74) v1(32.34,23.79) v1(32.33,22.02) v1(32.31,18.69) v1(32.32,1.54) v1(32.35,67.69) v1(32.35,26.02) v1(32.54,66.88) v1(32.52,28.02) v1(32.52,24.46) v1(32.47,15.25) v1(32.45,3.69) v1(32.6,62.64) v1(32.61,61.88) v1(32.58,61.15) v1(32.63,46.78) v1(32.57,39.68) v1(32.59,25.5) v1(32.59,25) v1(32.67,64.12) v1(32.7,58.82) v1(32.68,58.02) v1(32.68,7.8) v1(32.79,57.78) v1(32.85,55.99) v1(32.96,32.84) v1(33.01,27.45) v1(33.09,63.03) v1(33.12,59.6) v1(33.13,59.13) v1(33.2,60.39) v1(33.2,26.24) v1(33.19,24.32) v1(33.33,58.55) v1(33.33,2.11) v1(33.37,28.88) v1(33.47,63.49) v1(33.53,58.1) v1(33.51,55.25) v1(33.49,49.06) v1(33.52,22.14) v1(33.61,56.89) v1(33.74,48.14) v1(33.69,28.03) v1(33.8,58.93) v1(33.8,34.5) v1(33.87,64.41) v1(33.9,48.89) v1(34,59.59) v1(34.05,58.04) v1(33.95,56.01) v1(33.96,25.2) v1(34.07,60.31) v1(34.06,20.47) v1(34.18,48.13) v1(34.16,17.68) v1(34.16,17.11) v1(34.28,11.43) v1(34.41,58.62) v1(34.41,27.5) v1(34.39,21.03) v1(34.37,20.07) v1(34.45,13.43) v1(34.53,56.81) v1(34.45,5.38) v1(34.6,59.63) v1(34.63,47.5) v1(34.58,19.64) v1(34.58,16.09) v1(34.57,15.54) v1(34.62,13.72) v1(34.59,10.8) v1(34.58,4.41) v1(34.66,40.65) v1(34.74,7.83) v1(34.84,50.79) v1(34.83,50.28) v1(34.77,49.4) v1(34.93,40.88) v1(34.89,25.67) v1(34.87,10.2) v1(35.05,60.47) v1(34.97,59.12) v1(34.95,57.27) v1(34.99,14) v1(35.14,64.37) v1(35.11,5.49) v1(35.24,57.52) v1(35.24,54.95) v1(35.17,9.3) v1(35.26,28.02) v1(35.39,59.74) v1(35.37,59.22) v1(35.35,58.66) v1(35.41,40.42) v1(35.39,10.71) v1(35.48,57.08) v1(35.77,29.19) v1(36,28.63) v1(36.05,27.92) v1(36.2,41.58) v1(36.23,41.05) v1(36.19,40.56) v1(36.16,39.84) v1(36.2,24.23) v1(36.21,23.94) v1(36.22,4.54) v1(36.27,64) v1(36.33,50.37) v1(36.33,48.67) v1(36.3,47.73) v1(36.27,27.57) v1(36.26,27.02) v1(36.41,9.43) v1(36.43,0.76) v1(36.49,57.1) v1(36.49,50.18) v1(36.57,46.27) v1(36.58,26.66) v1(36.6,5.58) v1(36.73,59.83) v1(36.73,58.9) v1(36.66,55.3) v1(36.71,47.42) v1(36.73,41.55) v1(36.74,27.07) v1(36.67,26.29) v1(36.8,48.69) v1(36.8,24.7) v1(36.89,46) v1(36.91,24.19) v1(36.85,8.57) v1(37.05,56.8) v1(37,54.69) v1(37.04,48.08) v1(37.15,50.79) v1(37.23,23.94) v1(37.31,26.3) v1(37.28,25.16) v1(37.27,4.06) v1(37.48,65.22) v1(37.51,64.19) v1(37.53,50.62) v1(37.52,50.15) v1(37.46,35.91) v1(37.46,31.36) v1(37.46,30.06) v1(37.49,7.83) v1(37.6,48.7) v1(37.57,47.97) v1(37.56,47.39) v1(37.6,3.32) v1(37.73,51.75) v1(37.7,50.96) v1(37.8,54.15) v1(37.76,52.53) v1(37.76,46.02) v1(37.84,24.93) v1(37.8,21.39) v1(37.87,23.1) v1(38.03,58.3) v1(37.96,54.86) v1(38.08,57.41) v1(38.13,51.55) v1(38.05,50.44) v1(38.09,16.46) v1(38.25,59.66) v1(38.25,53.61) v1(38.23,27.07) v1(38.19,24.7) v1(38.18,22.91) v1(38.15,21.03) v1(38.3,52.59) v1(38.26,35.26) v1(38.26,33.31) v1(38.41,51.29) v1(38.39,16.16) v1(38.47,64.3) v1(38.45,9.55) v1(38.62,63.38) v1(38.62,56.34) v1(38.56,20.7) v1(38.59,4.81) v1(38.69,60.47) v1(38.66,27.3) v1(38.71,20.55) v1(38.84,57.99) v1(38.75,51.3) v1(38.92,59.66) v1(38.94,15.78) v1(38.95,3.31) v1(38.98,49.97) v1(38.95,49.07) v1(39.06,47.65) v1(39.06,37.21) v1(39.06,32.66) v1(39.17,24.23) v1(39.29,60.47) v1(39.29,55.23) v1(39.26,51.3) v1(39.31,47.07) v1(39.26,18.81) v1(39.42,47.69) v1(39.49,23.98) v1(39.49,2.72) v1(39.64,57.78) v1(39.65,50.02) v1(39.69,59.4) v1(39.7,58.86) v1(39.66,58.4) v1(39.74,53.7) v1(39.66,52.67) v1(39.66,52.33) v1(39.66,51.55) v1(39.76,54.05) v1(39.81,48.66) v1(39.81,14.85) v1(39.91,56.37) v1(39.94,53.35) v1(39.87,51.37) v1(39.86,33.31) v1(39.95,52.96) v1(40.05,52.24) v1(39.97,50.26) v1(40.02,7.71) v1(40.12,58.44) v1(40.08,57.16) v1(40.23,51.2) v1(40.16,48.12) v1(40.24,47.11) v1(40.19,24.23) v1(40.43,63.53) v1(40.45,56.54) v1(40.43,55.86) v1(40.41,54.95) v1(40.39,50.33) v1(40.48,63.29) v1(40.53,58.44) v1(40.51,54.26) v1(40.45,52.2) v1(40.48,48.17) v1(40.54,23.98) v1(40.46,8.82) v1(40.65,51.4) v1(40.59,18.52) v1(40.62,3.3) v1(40.67,53.47) v1(40.72,51.77) v1(40.66,31.36) v1(40.83,48.53) v1(40.83,5.41) v1(40.87,61) v1(40.97,61.7) v1(40.97,58.45) v1(40.99,57.17) v1(40.97,54.08) v1(41.05,10.31) v1(41.09,60) v1(41.12,11.15) v1(41.21,55.95) v1(41.19,24.9) v1(41.24,14) v1(41.42,54.12) v1(41.43,10.87) v1(41.35,10.01) v1(41.41,8.6) v1(41.55,60.75) v1(41.46,41.59) v1(41.53,23.51) v1(41.52,13.72) v1(41.57,59.42) v1(41.63,51.81) v1(41.67,57.22) v1(41.78,60.01) v1(41.8,54.39) v1(41.77,48.91) v1(41.81,9.4) v1(41.85,63.52) v1(41.85,56.72) v1(41.85,56.21) v1(41.86,49.19) v1(41.88,48.34) v1(41.88,45.82) v1(41.94,27.06) v1(42.02,57.74) v1(42.06,22.58) v1(42.23,59.54) v1(42.33,59.99) v1(42.28,24.36) v1(42.39,63.46) v1(42.36,57.25) v1(42.43,56.71) v1(42.42,22.15) v1(42.42,21.13) v1(42.46,51.86) v1(42.56,51.55) v1(42.55,7.68) v1(42.66,5.34) v1(42.79,51.02) v1(42.93,63.48) v1(42.93,56.41) v1(42.85,53.99) v1(42.97,62.96) v1(43.01,62.14) v1(43,61.17) v1(42.96,60.5) v1(43.05,58.6) v1(43.15,51.58) v1(43.2,49.26) v1(43.18,8.63) v1(43.34,55.95) v1(43.27,48.34) v1(43.32,16.46) v1(43.43,58.24) v1(43.42,57.81) v1(43.38,23.11) v1(43.41,22.71) v1(43.38,22.12) v1(43.38,21.69) v1(43.36,21.08) v1(43.38,20.7) v1(43.53,56.83) v1(43.59,20.2) v1(43.84,51.44) v1(43.92,53.38) v1(43.93,49.24) v1(43.86,35.26) v1(43.86,33.31) v1(44.02,57.98) v1(44.1,52.8) v1(44.11,51.94) v1(44.25,60.01) v1(44.16,51.05) v1(44.42,59.48) v1(44.41,55.92) v1(44.38,20.2) v1(44.52,18.98) v1(44.47,18.38) v1(44.65,63.69) v1(44.63,54.97) v1(44.6,31.33) v1(44.59,7.68) v1(44.69,63.26) v1(44.68,62.44) v1(44.72,61.81) v1(44.73,61) v1(44.73,60.38) v1(44.68,45.35) v1(44.71,44.68) v1(44.69,41.95) v1(44.79,8.64) v1(44.77,5.46) v1(44.91,54.15) v1(44.9,48.66) v1(44.87,16.42) v1(45.13,25.99) v1(45.21,42.3) v1(45.29,51.74) v1(45.32,42.97) v1(45.25,16.73) v1(45.26,14.8) v1(45.42,49.22) v1(45.58,63.39) v1(45.65,61.09) v1(45.62,24.6) v1(45.63,23.73) v1(45.56,20.32) v1(45.74,64.89) v1(45.79,16.9) v1(45.92,23.14) v1(45.92,22.12) v1(45.92,21.11) v1(45.93,14.31) v1(45.88,9.28) v1(46.1,51.77) v1(46.24,54.31) v1(46.28,22.71) v1(46.28,21.69) v1(46.28,20.68) v1(46.49,19.46) v1(46.47,10.06) v1(46.47,7.67) v1(46.63,52.62) v1(46.63,45) v1(46.58,42.45) v1(46.61,24.41) v1(46.73,60.65) v1(46.77,65.84) v1(46.77,63.71) v1(46.82,27.88) v1(46.84,25.42) v1(46.84,18.2) v1(46.91,19) v1(46.92,14.17) v1(46.87,11.54) v1(46.95,37.12) v1(46.99,35.12) v1(46.99,32.98) v1(46.97,30.09) v1(46.99,16.38) v1(47.04,13.79) v1(47.02,12.95) v1(47.02,12.14) v1(46.96,5.43) v1(47.15,22.82) v1(47.09,10.88) v1(47.12,8.35) v1(47.2,41.59) v1(47.23,19.25) v1(47.23,14.54) v1(47.29,15.69) v1(47.29,13.54) v1(47.29,12.67) v1(47.29,11.86) v1(47.53,64.97) v1(47.48,62.74) v1(47.47,20.29) v1(47.77,18.5) v1(47.78,17.64) v1(47.81,8.54) v1(48.02,23.73) v1(48.09,35.45) v1(48.13,28.7) v1(48.06,26.56) v1(48.11,22.08) v1(48.14,19.33) v1(48.25,60.82) v1(48.21,38.27) v1(48.16,33.26) v1(48.19,31) v1(48.18,25.05) v1(48.23,4.47) v1(48.3,44.21) v1(48.42,16.43) v1(48.4,13.44) v1(48.45,10.74) v1(48.35,8.95) v1(48.35,7.53) v1(48.49,45.37) v1(48.47,42.86) v1(48.63,40.03) v1(48.66,41.67) v1(48.96,51.77) v1(49.12,62.69) v1(49.09,48.19) v1(49.24,64.77) v1(49.16,49.98) v1(49.25,45.01) v1(49.23,36.56) v1(49.33,34.05) v1(49.37,46.13) v1(49.48,31.75) v1(50.8,62.62) v1(50.95,60.82) v1(50.98,64.91) v1(51.94,46.09) v1(52.58,48.05) v1(52.58,46.78) v2(0.76,53.61) v2(0.76,45.99) v2(0.76,44.72) v2(0.76,43.45) v2(0.76,42.18) v2(0.76,40.91) v2(0.76,39.64) v2(0.76,38.37) v2(0.76,37.1) v2(0.76,35.83) v2(0.76,34.56) v2(0.76,33.29) v2(0.76,32.02) v2(0.76,30.75) v2(0.76,29.48) v2(0.76,28.21) v2(0.76,26.94) v2(1.55,49.76) v2(1.58,39.7) v2(1.65,34.38) v2(1.68,52.27) v2(1.72,50.85) v2(1.67,41.74) v2(1.68,36.84) v2(1.68,31.79) v2(1.76,29.18) v2(1.83,8.85) v2(1.77,3.3) v2(2.48,41.91) v2(2.73,60.59) v2(2.67,50.3) v2(2.97,51.45) v2(3.05,43.69) v2(3.02,3.13) v2(3.25,63.33) v2(3.22,8.94) v2(3.44,29.2) v2(3.45,52.45) v2(3.54,34.32) v2(3.45,32.01) v2(3.5,26.43) v2(3.46,17.07) v2(3.5,16.1) v2(3.52,14.64) v2(3.46,11.38) v2(3.56,62.46) v2(3.56,49.53) v2(3.59,48.59) v2(3.62,47.27) v2(3.6,46.72) v2(3.65,45.42) v2(3.63,41.1) v2(3.56,36.85) v2(3.68,60.48) v2(3.65,44.31) v2(3.68,39.66) v2(3.82,59.69) v2(3.81,56.73) v2(4.22,48.95) v2(4.25,47.56) v2(4.25,46.33) v2(4.25,45.27) v2(4.32,61.47) v2(4.43,57.74) v2(4.36,2.77) v2(4.54,56.58) v2(4.46,55.7) v2(4.53,10.86) v2(4.54,8.9) v2(4.56,62.15) v2(4.78,54.8) v2(4.75,53.59) v2(4.83,52.13) v2(4.84,50.25) v2(4.85,6.97) v2(4.94,51.23) v2(4.91,49.54) v2(5.1,62.18) v2(5.13,57.12) v2(5.1,8.04) v2(5.17,52.91) v2(5.21,48.81) v2(5.21,47.51) v2(5.23,46.41) v2(5.2,44.88) v2(5.25,43.88) v2(5.21,9.57) v2(5.3,59.95) v2(5.29,55.77) v2(5.39,54.72) v2(5.36,48.17) v2(5.42,1.69) v2(5.49,53.98) v2(5.5,51) v2(5.54,50.2) v2(5.54,41) v2(5.59,61.47) v2(5.59,44.96) v2(5.59,43.69) v2(5.59,42.42) v2(5.71,62.2) v2(5.95,56.21) v2(5.91,47.54) v2(5.91,46.77) v2(5.99,58.37) v2(6.13,50.02) v2(6.16,63.48) v2(6.16,4.32) v2(6.28,52.09) v2(6.28,7.75) v2(6.42,50.98) v2(6.48,63.96) v2(6.52,48.79) v2(6.79,62.19) v2(6.83,9.04) v2(6.86,61.47) v2(6.86,42.42) v2(7.01,63.96) v2(6.96,50.24) v2(7.16,59.84) v2(7.15,44.66) v2(7.15,7.43) v2(7.27,49.59) v2(7.38,61.58) v2(7.39,52.48) v2(7.43,41.28) v2(7.55,63.96) v2(7.51,63.51) v2(7.52,61.97) v2(7.51,44.18) v2(7.52,43.54) v2(7.53,42.84) v2(7.51,41.97) v2(7.55,56.35) v2(7.58,53.56) v2(7.62,50.78) v2(7.63,45.22) v2(7.66,46.02) v2(7.74,39.66) v2(7.81,62.09) v2(7.83,59.34) v2(7.76,58.1) v2(7.81,55.58) v2(7.75,51.48) v2(7.83,49.51) v2(7.75,40.81) v2(8.04,38.73) v2(8,4.51) v2(8.08,63.96) v2(8.1,61.47) v2(8.09,44.19) v2(8.1,43.55) v2(8.11,42.85) v2(8.09,41.98) v2(8.15,48.78) v2(8.25,44.62) v2(8.28,56.36) v2(8.39,55.13) v2(8.43,53.51) v2(8.4,52.27) v2(8.41,51.13) v2(8.37,46.02) v2(8.46,59.64) v2(8.47,58.45) v2(8.46,50.41) v2(8.49,0.76) v2(8.6,44.19) v2(8.61,43.55) v2(8.62,42.85) v2(8.6,41.98) v2(8.68,41.34) v2(8.8,49.53) v2(8.81,44.56) v2(8.87,62.11) v2(9.01,52.24) v2(8.97,48.77) v2(9.12,46.05) v2(9.05,38.35) v2(9.24,49.33) v2(9.32,63.18) v2(9.33,40.66) v2(9.35,39.12) v2(9.4,62.74) v2(9.4,58.93) v2(9.4,57.66) v2(9.4,55.12) v2(9.4,53.85) v2(9.43,47.66) v2(9.4,4.32) v2(9.56,59.6) v2(9.63,58.24) v2(9.75,57.21) v2(9.82,55.93) v2(9.77,52.93) v2(9.81,52.24) v2(9.87,50.95) v2(9.94,45.29) v2(10.01,62.11) v2(10.13,38.35) v2(10.19,61.55) v2(10.35,48.94) v2(10.29,43.85) v2(10.26,4) v2(10.5,1.89) v2(10.6,63.26) v2(10.6,44.51) v2(10.69,49.54) v2(10.67,3.05) v2(10.89,61.55) v2(10.92,59.62) v2(10.9,58.58) v2(10.95,50.82) v2(11.03,62.29) v2(11.02,52.87) v2(10.96,50.22) v2(11.03,0.76) v2(11.12,54.4) v2(11.06,51.37) v2(11.29,62.93) v2(11.31,2.58) v2(11.4,52.23) v2(11.52,61.93) v2(11.51,60.27) v2(11.49,59.28) v2(11.63,58.43) v2(11.58,51.15) v2(11.55,48.95) v2(11.79,50.48) v2(11.88,63.96) v2(11.94,61.47) v2(11.94,52.58) v2(11.94,51.31) v2(11.94,3.05) v2(11.99,62.95) v2(11.96,38.19) v2(12.2,62.26) v2(12.24,60.19) v2(12.17,52.24) v2(12.32,59.06) v2(12.27,54.41) v2(12.3,0.76) v2(12.43,63.95) v2(12.74,58.41) v2(12.77,52.28) v2(12.77,51.19) v2(12.84,50.49) v2(12.76,6.3) v2(12.81,1.44) v2(12.96,63.95) v2(12.97,4.01) v2(12.96,2.31) v2(13.21,53.85) v2(13.16,48.99) v2(13.21,3.05) v2(13.35,63.17) v2(13.5,63.95) v2(13.53,38.68) v2(13.57,0.76) v2(13.7,59.27) v2(13.73,54.46) v2(14.01,63.95) v2(14.02,48.47) v2(14.09,1.86) v2(14.29,49.64) v2(14.43,62.68) v2(14.49,51.45) v2(14.48,3.05) v2(14.56,63.94) v2(14.62,61.73) v2(14.65,47.84) v2(14.76,52.19) v2(14.84,0.76) v2(14.88,60.12) v2(14.86,48.85) v2(14.88,47.28) v2(14.93,38.74) v2(14.98,63.25) v2(15.09,63.94) v2(15.2,50.84) v2(15.29,59.67) v2(15.37,63.58) v2(15.41,49.53) v2(15.45,48.15) v2(15.52,62.66) v2(15.46,2.29) v2(15.7,58.72) v2(15.73,57.99) v2(15.71,57.18) v2(15.71,56.53) v2(15.71,55.86) v2(15.7,55.19) v2(15.7,54.52) v2(15.73,38.33) v2(15.75,63.18) v2(15.76,1.32) v2(15.95,60.29) v2(15.9,50.98) v2(15.89,49.54) v2(16.02,63.73) v2(16.03,61.92) v2(15.96,9.67) v2(16.11,0.76) v2(16.17,63.94) v2(16.27,60.09) v2(16.3,59.16) v2(16.45,63.7) v2(16.55,5.04) v2(16.55,63.12) v2(16.59,62.67) v2(16.61,9.04) v2(16.72,63.93) v2(16.77,53.81) v2(16.98,63.69) v2(17.02,41.15) v2(17.02,39.88) v2(17.1,61.94) v2(17.25,63.93) v2(17.25,63.13) v2(17.25,53.97) v2(17.16,38.69) v2(17.29,59.06) v2(17.41,53.14) v2(17.46,63.69) v2(17.57,9.81) v2(17.7,62.65) v2(17.79,63.93) v2(17.84,39.83) v2(17.95,56.85) v2(17.93,54.7) v2(17.9,44.89) v2(17.87,41.97) v2(18.04,63.69) v2(17.99,63.12) v2(18.05,59.06) v2(17.98,56.17) v2(17.96,55.53) v2(18,52.59) v2(18.06,58.05) v2(18.14,57.48) v2(18.23,58.42) v2(18.33,63.93) v2(18.27,53.61) v2(18.29,41.15) v2(18.41,51.14) v2(18.39,48.41) v2(18.38,47.53) v2(18.46,50.41) v2(18.57,63.7) v2(18.61,59.05) v2(18.64,56.41) v2(18.64,54.91) v2(18.7,52.26) v2(18.72,10.06) v2(18.77,63.12) v2(18.84,62.67) v2(18.76,44.02) v2(18.88,63.92) v2(18.93,47.75) v2(19,52.77) v2(19.14,63.63) v2(19.13,47.02) v2(19.3,57.58) v2(19.34,56.32) v2(19.34,55.24) v2(19.41,63.92) v2(19.43,54.46) v2(19.38,52.29) v2(19.44,50.34) v2(19.54,63.25) v2(19.46,51.17) v2(19.48,48.43) v2(19.53,47.12) v2(19.5,46.3) v2(19.61,59) v2(19.56,19.56) v2(19.82,62.79) v2(19.95,63.92) v2(19.91,9.64) v2(19.95,57.17) v2(20.09,53.68) v2(20.49,63.92) v2(20.55,63.33) v2(20.64,60.68) v2(20.62,58.97) v2(20.68,59.82) v2(20.73,58.02) v2(20.84,51) v2(20.84,49.92) v2(20.79,47.83) v2(20.8,47.13) v2(20.84,6.88) v2(20.94,48.34) v2(20.88,14.62) v2(21.04,63.91) v2(20.97,56.33) v2(20.97,55.11) v2(21,53.86) v2(21.19,63.4) v2(21.24,37.62) v2(21.51,47.52) v2(21.51,15.25) v2(21.48,14.52) v2(21.49,12.76) v2(21.49,12.03) v2(21.5,11.02) v2(21.48,10.25) v2(21.5,9.48) v2(21.57,63.91) v2(21.75,57.02) v2(21.7,50.76) v2(21.77,63.28) v2(21.82,59.11) v2(21.8,58.21) v2(21.86,51.65) v2(21.89,49.87) v2(22.05,36.84) v2(22.11,63.91) v2(22.1,57.66) v2(22.07,45.41) v2(22.25,15.6) v2(22.24,12.02) v2(22.22,11.03) v2(22.2,9.53) v2(22.29,59.68) v2(22.34,48.29) v2(22.27,12.76) v2(22.27,10.23) v2(22.41,60.22) v2(22.39,14.02) v2(22.53,56.31) v2(22.5,55.35) v2(22.65,63.91) v2(22.67,49.37) v2(22.73,44.8) v2(22.77,59.16) v2(22.9,62.73) v2(22.97,60.18) v2(23.14,66.22) v2(23.05,63.36) v2(23.09,15.62) v2(23.11,13.97) v2(23.13,12.72) v2(23.23,64.69) v2(23.26,58.73) v2(23.32,13.29) v2(23.34,12.08) v2(23.37,52.58) v2(23.37,48.77) v2(23.41,10.98) v2(23.52,58.2) v2(23.54,57) v2(23.54,8.69) v2(23.59,67.82) v2(23.73,44.69) v2(23.66,9.46) v2(23.83,66.94) v2(23.84,37.56) v2(23.83,12.99) v2(23.98,55.87) v2(24.02,53.02) v2(24.11,51.45) v2(24.11,49.77) v2(24.16,48.68) v2(24.27,65.48) v2(24.29,10.96) v2(24.64,66.89) v2(24.64,62.74) v2(24.6,48.19) v2(24.59,47.41) v2(24.57,12.74) v2(24.6,12.05) v2(24.71,10.44) v2(24.86,67.82) v2(24.91,34.14) v2(24.9,33.62) v2(25.02,50.55) v2(24.97,29.28) v2(25,0.76) v2(25.08,59.41) v2(25.12,58.26) v2(25.14,44.7) v2(25.16,60.54) v2(25.34,10.91) v2(25.45,62.7) v2(25.38,49.3) v2(25.39,48.18) v2(25.44,47.33) v2(25.4,34.17) v2(25.42,8.73) v2(25.49,66.44) v2(25.54,14.51) v2(25.48,9.62) v2(25.57,65.57) v2(25.57,50.01) v2(25.61,13.84) v2(25.62,13.34) v2(25.59,12.07) v2(25.72,63.24) v2(25.68,33.35) v2(25.8,15.57) v2(25.91,60.2) v2(25.91,58.93) v2(25.95,16.82) v2(26,67.14) v2(26.13,67.82) v2(26.15,38.1) v2(26.14,12.73) v2(26.14,10.13) v2(26.24,58.42) v2(26.16,56.37) v2(26.22,51.75) v2(26.18,49.38) v2(26.17,44.76) v2(26.16,10.96) v2(26.26,63.24) v2(26.27,62.21) v2(26.26,61.41) v2(26.26,60.65) v2(26.27,55.04) v2(26.25,53.72) v2(26.3,8.7) v2(26.27,0.76) v2(26.38,64.75) v2(26.43,18.32) v2(26.43,17.46) v2(26.41,16.36) v2(26.63,36) v2(26.55,35.75) v2(26.57,29.28) v2(26.72,15.57) v2(26.7,13.84) v2(26.73,12.26) v2(26.9,63.31) v2(26.87,62.47) v2(26.86,61.59) v2(26.89,55.88) v2(26.9,54.73) v2(26.93,53.43) v2(26.95,51.78) v2(26.86,13.36) v2(26.96,63.99) v2(26.97,58.19) v2(27,35.32) v2(26.98,9.38) v2(27.07,66.33) v2(27.07,64.45) v2(27.05,37.3) v2(27.05,17.97) v2(27.05,10.92) v2(27.11,10.06) v2(27.18,61.47) v2(27.18,60.2) v2(27.18,58.93) v2(27.18,57.66) v2(27.18,17.02) v2(27.18,15.75) v2(27.2,14.47) v2(27.31,50.67) v2(27.4,67.82) v2(27.43,51.25) v2(27.39,36.06) v2(27.38,32.48) v2(27.35,18.9) v2(27.37,12.9) v2(27.37,12.1) v2(27.54,54.99) v2(27.54,54.08) v2(27.54,0.76) v2(27.57,53.26) v2(27.55,52.42) v2(27.64,16.35) v2(27.55,8.83) v2(27.82,48.1) v2(27.78,11.56) v2(27.87,65.91) v2(27.9,55.5) v2(27.92,50.19) v2(28.02,67.23) v2(28,63.91) v2(28,62.1) v2(27.96,58.87) v2(28.11,64.81) v2(28.12,50.91) v2(28.25,60.34) v2(28.2,59.91) v2(28.16,59.35) v2(28.25,63.27) v2(28.32,19.09) v2(28.33,15.12) v2(28.27,12.02) v2(28.45,64.01) v2(28.4,62.81) v2(28.45,61.47) v2(28.45,59.19) v2(28.45,57.66) v2(28.45,55.55) v2(28.45,50.04) v2(28.44,20.2) v2(28.42,18.57) v2(28.42,15.77) v2(28.41,14.18) v2(28.39,13.38) v2(28.46,47.4) v2(28.58,61.05) v2(28.61,58.73) v2(28.61,49.28) v2(28.67,67.82) v2(28.67,49.75) v2(28.7,20.81) v2(28.7,15.52) v2(28.7,11.17) v2(28.72,10.5) v2(28.79,58.17) v2(28.76,50.16) v2(28.8,18.26) v2(28.83,9.77) v2(28.81,0.76) v2(28.92,61.43) v2(28.88,55.83) v2(29.04,66.28) v2(29.01,50.95) v2(29.02,48.94) v2(29.13,19.43) v2(29.13,14.03) v2(29.09,12.11) v2(29.25,64.74) v2(29.16,62.99) v2(29.34,61.59) v2(29.35,60.73) v2(29.33,59.22) v2(29.32,46.55) v2(29.44,58.85) v2(29.43,55.54) v2(29.42,50.12) v2(29.36,15.02) v2(29.44,9.37) v2(29.48,23.79) v2(29.46,13.37) v2(29.55,60.43) v2(29.62,59.99) v2(29.56,48.82) v2(29.57,19.08) v2(29.72,58.2) v2(29.72,57.66) v2(29.72,56.39) v2(29.72,15.52) v2(29.76,48.01) v2(29.82,18.59) v2(29.94,67.82) v2(29.88,62.17) v2(29.9,61.59) v2(29.86,60.85) v2(29.9,60.44) v2(29.92,10.8) v2(30,67.33) v2(29.96,9.91) v2(30.1,63.52) v2(30.07,55.82) v2(30.11,14.39) v2(30.07,11.65) v2(30.08,0.76) v2(30.24,62.72) v2(30.16,59.05) v2(30.24,57.45) v2(30.19,47.56) v2(30.32,18.66) v2(30.39,58.76) v2(30.38,48.26) v2(30.52,9.35) v2(30.55,61.83) v2(30.55,58.06) v2(30.59,55.55) v2(30.58,19.08) v2(30.57,11.14) v2(30.72,47.7) v2(30.74,46.96) v2(30.77,63.4) v2(30.88,59.06) v2(30.9,57.22) v2(30.91,17.16) v2(30.89,13.88) v2(30.93,10.3) v2(30.99,62.74) v2(30.99,57.66) v2(30.99,56.39) v2(31.11,48.73) v2(31.14,23.8) v2(31.16,61.8) v2(31.17,55.86) v2(31.19,18.9) v2(31.2,13.39) v2(31.27,58.76) v2(31.27,58.04) v2(31.33,11.54) v2(31.42,49.67) v2(31.36,37.29) v2(31.36,29.65) v2(31.42,18.29) v2(31.41,10.76) v2(31.35,0.76) v2(31.5,60.45) v2(31.5,48.13) v2(31.54,10.29) v2(31.52,9.31) v2(31.64,63.43) v2(31.65,55.54) v2(31.59,46.79) v2(31.62,20.07) v2(31.67,59.09) v2(31.7,57.74) v2(31.8,19.58) v2(31.83,19.28) v2(31.9,62.99) v2(31.9,62.33) v2(31.88,61.78) v2(31.86,17.72) v2(31.91,2.19) v2(32.04,60.11) v2(32.01,17.16) v2(32.12,60.83) v2(32.22,57.76) v2(32.17,55.88) v2(32.17,55.53) v2(32.16,18.85) v2(32.26,65.28) v2(32.28,63.51) v2(32.26,62.74) v2(32.26,61.47) v2(32.28,59.37) v2(32.26,55.12) v2(32.26,53.85) v2(32.26,52.58) v2(32.26,51.31) v2(32.29,48.67) v2(32.33,46.74) v2(32.34,23.79) v2(32.31,18.69) v2(32.26,4.32) v2(32.26,3.05) v2(32.32,1.54) v2(32.35,67.69) v2(32.54,66.88) v2(32.47,15.25) v2(32.45,3.69) v2(32.6,62.64) v2(32.61,61.88) v2(32.58,61.15) v2(32.63,46.78) v2(32.7,58.82) v2(32.68,58.02) v2(32.79,57.78) v2(32.85,55.99) v2(32.96,32.84) v2(33.09,63.03) v2(33.12,59.6) v2(33.13,59.13) v2(33.13,17.14) v2(33.2,60.39) v2(33.19,24.32) v2(33.17,19.45) v2(33.33,58.55) v2(33.33,2.11) v2(33.4,18.52) v2(33.47,63.49) v2(33.53,61.47) v2(33.53,58.1) v2(33.49,49.06) v2(33.53,20.11) v2(33.53,6.86) v2(33.74,48.14) v2(33.8,58.93) v2(33.84,17.71) v2(33.9,48.89) v2(34,59.59) v2(33.96,25.2) v2(34.04,18.92) v2(34.07,60.31) v2(34.18,48.13) v2(34.16,17.11) v2(34.28,11.43) v2(34.41,58.62) v2(34.37,20.07) v2(34.6,59.63) v2(34.58,19.64) v2(34.59,10.8) v2(34.58,4.41) v2(34.66,40.65) v2(34.84,50.79) v2(34.83,50.28) v2(34.77,49.4) v2(34.81,22.79) v2(34.79,18.54) v2(34.8,6.86) v2(34.93,40.88) v2(34.87,10.97) v2(34.87,10.2) v2(35.05,60.47) v2(34.97,59.12) v2(34.95,57.27) v2(35.24,57.52) v2(35.19,19.32) v2(35.17,9.3) v2(35.39,59.74) v2(35.37,59.22) v2(35.35,58.66) v2(35.41,40.42) v2(35.39,10.71) v2(35.48,57.08) v2(35.52,23.57) v2(35.86,17.67) v2(35.96,17.14) v2(36.07,6.86) v2(36.2,41.58) v2(36.23,41.05) v2(36.19,40.56) v2(36.16,39.84) v2(36.2,24.23) v2(36.22,4.54) v2(36.33,50.37) v2(36.33,48.67) v2(36.3,47.73) v2(36.27,27.57) v2(36.26,27.02) v2(36.44,18.27) v2(36.41,9.43) v2(36.43,0.76) v2(36.49,57.1) v2(36.49,50.18) v2(36.5,22.5) v2(36.48,21.39) v2(36.45,20.19) v2(36.45,19.34) v2(36.57,46.27) v2(36.58,26.66) v2(36.59,17.83) v2(36.73,58.9) v2(36.66,55.3) v2(36.71,47.42) v2(36.73,41.55) v2(36.74,27.07) v2(36.67,26.29) v2(36.8,48.69) v2(36.8,24.7) v2(36.89,46) v2(36.91,24.19) v2(37,54.69) v2(37.04,48.08) v2(37.15,50.79) v2(37.23,23.94) v2(37.34,51.31) v2(37.31,26.3) v2(37.28,25.16) v2(37.34,6.86) v2(37.27,4.06) v2(37.53,50.62) v2(37.52,50.15) v2(37.6,48.7) v2(37.57,47.97) v2(37.56,47.39) v2(37.59,14.85) v2(37.6,3.32) v2(37.76,46.02) v2(37.85,14.45) v2(37.96,54.86) v2(38.09,16.46) v2(38.25,59.66) v2(38.23,27.07) v2(38.61,60.2) v2(38.56,20.7) v2(38.61,6.86) v2(38.69,60.47) v2(38.66,27.3) v2(38.71,20.55) v2(38.75,51.3) v2(38.76,12.86) v2(38.92,59.66) v2(38.94,15.78) v2(38.95,3.31) v2(38.95,49.07) v2(39.06,47.65) v2(39.14,11.35) v2(39.17,12.75) v2(39.29,60.47) v2(39.26,51.3) v2(39.31,47.07) v2(39.42,47.69) v2(39.49,23.98) v2(39.49,2.72) v2(39.64,57.78) v2(39.69,59.4) v2(39.7,58.86) v2(39.66,58.4) v2(39.74,53.7) v2(39.81,48.66) v2(39.88,61.47) v2(39.88,9.4) v2(39.88,6.86) v2(40.12,58.44) v2(40.16,48.12) v2(40.24,47.11) v2(40.19,24.23) v2(40.43,63.53) v2(40.45,56.54) v2(40.43,55.86) v2(40.41,54.95) v2(40.48,63.29) v2(40.53,58.44) v2(40.51,54.26) v2(40.45,52.2) v2(40.48,48.17) v2(40.54,23.98) v2(40.46,8.82) v2(40.65,51.4) v2(40.63,15.35) v2(40.62,3.3) v2(40.67,53.47) v2(40.83,48.53) v2(40.87,61) v2(40.97,61.7) v2(40.97,58.45) v2(40.97,54.08) v2(41.05,10.31) v2(41.09,60) v2(41.12,11.15) v2(41.15,10.67) v2(41.15,9.4) v2(41.15,6.86) v2(41.21,55.95) v2(41.24,14) v2(41.42,54.12) v2(41.43,10.87) v2(41.35,10.01) v2(41.41,8.6) v2(41.55,60.75) v2(41.52,13.72) v2(41.57,59.42) v2(41.63,51.81) v2(41.67,57.22) v2(41.78,60.01) v2(41.8,54.39) v2(41.77,48.91) v2(41.81,9.4) v2(41.85,63.52) v2(41.85,56.72) v2(41.85,56.21) v2(41.86,49.19) v2(41.88,48.34) v2(41.88,45.82) v2(42.02,57.74) v2(42.23,59.54) v2(42.33,59.99) v2(42.39,63.46) v2(42.36,57.25) v2(42.43,56.71) v2(42.42,44.96) v2(42.42,21.13) v2(42.42,10.67) v2(42.42,6.86) v2(42.46,51.86) v2(42.56,51.55) v2(42.79,51.02) v2(42.93,63.48) v2(42.93,56.41) v2(42.85,53.99) v2(42.97,62.96) v2(43.01,62.14) v2(43,61.17) v2(42.96,60.5) v2(43.05,58.6) v2(43.15,51.58) v2(43.2,49.26) v2(43.18,8.63) v2(43.27,48.34) v2(43.32,16.46) v2(43.43,58.24) v2(43.42,57.81) v2(43.38,23.11) v2(43.41,22.71) v2(43.38,22.12) v2(43.38,21.69) v2(43.36,21.08) v2(43.38,20.7) v2(43.59,20.2) v2(43.69,65.28) v2(43.69,10.67) v2(43.69,9.4) v2(43.69,6.86) v2(43.84,51.44) v2(43.92,53.38) v2(43.93,49.24) v2(44.1,52.8) v2(44.11,51.94) v2(44.25,60.01) v2(44.16,51.05) v2(44.42,59.48) v2(44.38,20.2) v2(44.52,18.98) v2(44.47,18.38) v2(44.65,63.69) v2(44.63,54.97) v2(44.6,31.33) v2(44.69,63.26) v2(44.68,62.44) v2(44.72,61.81) v2(44.73,61) v2(44.73,60.38) v2(44.68,45.35) v2(44.71,44.68) v2(44.79,8.64) v2(44.91,54.15) v2(44.9,48.66) v2(44.96,65.28) v2(44.96,64.01) v2(44.96,62.74) v2(44.96,61.47) v2(44.96,60.2) v2(44.96,24.64) v2(44.96,23.37) v2(44.96,22.1) v2(44.96,10.67) v2(44.96,9.4) v2(44.96,6.86) v2(45.29,51.74) v2(45.32,42.97) v2(45.26,14.8) v2(45.42,49.22) v2(45.62,24.6) v2(45.63,23.73) v2(45.56,20.32) v2(45.59,19.81) v2(45.92,23.14) v2(45.92,22.12) v2(45.92,21.11) v2(45.93,14.31) v2(45.88,9.28) v2(45.97,20.12) v2(46.1,51.77) v2(46.23,65.28) v2(46.23,62.74) v2(46.23,61.47) v2(46.23,60.2) v2(46.24,54.31) v2(46.23,23.37) v2(46.23,6.86) v2(46.28,22.71) v2(46.28,21.69) v2(46.28,20.68) v2(46.49,19.46) v2(46.47,10.06) v2(46.47,7.67) v2(46.61,24.41) v2(46.84,18.2) v2(46.91,19) v2(46.92,14.17) v2(46.87,11.54) v2(46.99,16.38) v2(47.04,13.79) v2(47.02,12.95) v2(47.02,12.14) v2(47.15,22.82) v2(47.09,10.88) v2(47.12,8.35) v2(47.23,19.25) v2(47.23,14.54) v2(47.29,15.69) v2(47.29,13.54) v2(47.29,12.67) v2(47.29,11.86) v2(47.5,61.47) v2(47.5,60.2) v2(47.5,58.93) v2(47.5,57.66) v2(47.5,47.5) v2(47.5,46.23) v2(47.5,44.96) v2(47.47,20.29) v2(47.5,17.02) v2(47.5,6.86) v2(47.77,18.5) v2(47.78,17.64) v2(47.81,8.54) v2(48.02,23.73) v2(48.11,22.08) v2(48.14,19.33) v2(48.18,25.05) v2(48.23,4.47) v2(48.3,44.21) v2(48.35,8.95) v2(48.35,7.53) v2(48.49,45.37) v2(48.77,47.5) v2(48.77,46.23) v2(50.04,46.23) v2(50.04,38.61) v2(50.04,36.07) v2(50.04,33.53) v2(50.04,30.99) v2(50.04,28.45) v2(50.04,25.91) v2(52.58,48.05) v2(52.58,46.78) v3(6.17,25.2) v3(6.17,24.25) v3(7.3,19.79) v3(7.8,43.87) v3(7.79,43.18) v3(7.79,42.39) v3(8.37,43.87) v3(8.36,43.18) v3(8.36,42.39) v3(9.49,51.64) v3(9.82,50.31) v3(11.39,49.62) v3(12.1,49.16) v3(12.36,60.66) v3(12.41,59.75) v3(12.82,49.31) v3(12.88,61.04) v3(13.08,59.56) v3(13.16,61.29) v3(13.54,60.84) v3(14.32,48.37) v3(14.63,61.38) v3(14.81,60.98) v3(14.82,50.34) v3(14.96,60.6) v3(15.95,60.69) v3(16.12,61.33) v3(17.09,17.14) v3(17.37,20.6) v3(17.79,22.63) v3(17.89,21.92) v3(18,20.62) v3(17.98,20.01) v3(18.29,16.49) v3(18.58,19.56) v3(18.61,16.98) v3(18.8,20.65) v3(19.25,24.69) v3(19.26,20.65) v3(19.46,61.73) v3(20.66,61.15) v3(20.95,61.84) v3(23.54,43.99) v3(23.79,48.16) v3(23.81,47.35) v3(24.85,44.22) v3(24.85,43.45) v3(24.97,63.47) v3(25.29,61.92) v3(25.27,61.2) v3(25.8,60.94) v3(25.98,55.7) v3(26,54.29) v3(25.98,44.3) v3(26.01,43.46) v3(26.06,48.67) v3(26.35,37.9) v3(26.8,37.45) v3(26.9,38) v3(26.98,61.88) v3(27.09,48.63) v3(27.14,44.27) v3(28.06,44.06) v3(28.41,57.05) v3(28.48,54.39) v3(28.72,53.2) v3(28.8,55.12) v3(29.04,50.4) v3(29.36,54.38) v3(29.4,52.48) v3(29.52,49.24) v3(29.51,48.4) v3(29.9,56.94) v3(30.23,52.05) v3(30.29,56.26) v3(30.41,49.25) v3(30.55,54.72) v3(30.92,33.75) v3(31.3,54.37) v3(31.82,54.89) v3(32.52,49) v3(32.54,47.99) v3(33.31,47.84) v3(34.22,54.91) v3(34.48,53.81) v3(34.45,53.22) v3(35.77,54.53) v3(35.98,48.97) v3(36.56,49.91) v3(36.61,49.03) v3(36.63,48.34) v3(36.73,56.26) v3(37.23,48.95) v3(37.65,57.98) v3(37.95,55.63) v3(38.37,53.17) v3(38.42,52.6) v3(39.01,57.59) v3(39.06,58.18) v3(39.42,53.76) v3(39.67,54.48) v3(39.7,50.13) v3(39.82,49.07) v3(39.83,47.61) v3(40.18,58.85) v3(40.81,49.36) v3(40.86,51.19) v3(40.97,54.38) v3(41.07,49.72) v3(41.3,55.62) v3(41.38,48.2) v3(41.55,49.66) v3(41.64,59.01) v3(41.76,52.44) v3(42.12,49.78) v3(42.16,55.22) v3(42.23,51.12) v3(42.34,52.82) v3(42.47,53.47) v3(43.03,52.78) v3(43.29,58.84) v3(43.29,56.12) v3(43.61,57.54) v3(43.8,54.62) v3(43.9,56.22) v3(43.91,53.78) v3(43.99,58.36) v4(0.65,47.23) v4(0.65,45.95) v4(0.65,43.39) v4(0.64,41) v4(0.62,39.34) v4(0.62,37.28) v4(0.63,34.03) v4(0.63,32.86) v4(0.63,31.41) v4(0.61,30.07) v4(0.7,44.48) v4(1.06,46.23) v4(1.1,45.16) v4(1.22,52.81) v4(1.17,47.68) v4(1.22,43.95) v4(1.73,59.61) v4(1.68,46.91) v4(1.66,6.75) v4(1.7,6.07) v4(1.79,51.72) v4(1.86,58.26) v4(2.04,47.62) v4(2.2,57.8) v4(2.52,52.33) v4(2.55,46.91) v4(2.9,58.97) v4(3.12,48.35) v4(3.1,47.47) v4(3.23,6.41) v4(3.5,52.62) v4(3.54,51.59) v4(3.52,46.98) v4(3.49,27.13) v4(3.54,4.23) v4(3.6,50.78) v4(3.59,49.22) v4(3.56,48.09) v4(3.65,56.44) v4(3.79,25.82) v4(3.8,4.76) v4(3.88,59.29) v4(3.98,25.11) v4(4.05,27.72) v4(4.32,62.74) v4(4.32,25.91) v4(4.32,10.67) v4(4.32,9.4) v4(4.53,28.5) v4(4.54,2.66) v4(5.33,36.01) v4(5.52,1.92) v4(5.59,34.8) v4(6.08,36.7) v4(6.36,35.54) v4(6.42,28.34) v4(6.86,34.8) v4(7.34,37.52) v4(7.38,36.9) v4(7.46,30.16) v4(8.14,62.24) v4(8.13,58.93) v4(8.54,32.83) v4(9.33,56.22) v4(9.31,11.88) v4(9.4,48.77) v4(9.61,40.78) v4(9.62,34.4) v4(9.64,32.74) v4(9.77,57.3) v4(10.39,41.81) v4(10.54,56.65) v4(10.48,39.88) v4(10.67,61.77) v4(10.73,40.99) v4(10.67,38.61) v4(10.81,58.64) v4(10.78,55.52) v4(11.03,62.26) v4(10.99,61.15) v4(11.11,1.44) v4(11.22,40.38) v4(11.36,60.34) v4(11.41,55.79) v4(11.39,34.1) v4(11.41,33.3) v4(11.48,21.79) v4(11.63,36.63) v4(11.68,37.62) v4(11.66,35.13) v4(11.73,0.8) v4(11.83,50.56) v4(11.77,50.05) v4(11.91,61.74) v4(11.98,61.05) v4(12.2,35.62) v4(12.15,34.49) v4(12.18,33.63) v4(12.59,60.91) v4(12.71,62.26) v4(12.79,50.57) v4(12.78,34.1) v4(13.18,61.77) v4(13.21,36.23) v4(13.21,17.02) v4(13.7,50.58) v4(13.85,36.45) v4(13.95,37.6) v4(14.04,2) v4(14.24,48.85) v4(14.49,45.88) v4(14.48,39.88) v4(14.48,38.61) v4(14.48,37.34) v4(14.62,58.27) v4(14.61,55.51) v4(14.62,48.24) v4(14.72,59.53) v4(14.74,49.07) v4(14.72,38.17) v4(14.94,45.53) v4(15.02,46.23) v4(15.14,49.69) v4(15.06,48.68) v4(15.51,51.72) v4(15.75,18.29) v4(15.76,46.71) v4(15.88,51.31) v4(15.91,44.38) v4(16.09,61.69) v4(16.16,52.97) v4(16.39,51.59) v4(16.39,43.6) v4(16.36,42.98) v4(16.5,45.19) v4(16.73,62.21) v4(16.66,50.83) v4(16.78,61.38) v4(16.78,52.67) v4(16.79,51.28) v4(16.97,53.1) v4(17.04,51.79) v4(17.02,50.19) v4(17.02,47.7) v4(17.02,44.96) v4(17.14,60.57) v4(17.09,46.73) v4(17.11,44.47) v4(17.17,43.85) v4(17.33,51.31) v4(17.61,61.49) v4(17.57,47.42) v4(17.83,51) v4(17.77,50.62) v4(17.81,50.18) v4(17.79,49.49) v4(18.01,51.67) v4(18.05,44.62) v4(18.14,62.23) v4(18.07,60.55) v4(18.13,49.74) v4(18.09,46.43) v4(18.29,19.56) v4(18.29,17.02) v4(18.41,59.1) v4(18.41,58.36) v4(18.4,53.09) v4(18.38,50.98) v4(18.36,50.17) v4(18.46,55.49) v4(18.63,51.68) v4(18.66,61.52) v4(18.93,60.55) v4(18.94,4.21) v4(19.05,62.18) v4(19.29,50.61) v4(19.3,3.02) v4(19.5,51.62) v4(19.61,47.74) v4(19.68,46.59) v4(19.66,15.47) v4(19.71,4.97) v4(19.79,52.59) v4(19.83,52) v4(19.82,44.78) v4(19.85,45.91) v4(19.93,2.48) v4(19.99,51.04) v4(20.25,47.12) v4(20.4,5.53) v4(20.5,50.53) v4(20.52,45.16) v4(20.59,52.36) v4(20.64,51.65) v4(20.63,6.01) v4(20.83,11.94) v4(20.89,47.72) v4(21.11,45.87) v4(21.1,4.91) v4(21.21,53.48) v4(21.16,50.91) v4(21.19,44.73) v4(21.3,47.42) v4(21.35,6.96) v4(21.39,5.88) v4(21.68,51.47) v4(21.81,46.92) v4(21.94,52.31) v4(21.87,49.98) v4(21.91,7.03) v4(21.95,3.04) v4(21.96,62.3) v4(21.96,61.02) v4(22.1,37.34) v4(22.22,59.1) v4(22.21,58.37) v4(22.22,55.42) v4(22.24,45.46) v4(22.26,47.57) v4(22.28,46.45) v4(22.43,53.48) v4(22.4,29.2) v4(22.43,24.39) v4(22.41,23.77) v4(22.39,21.86) v4(22.38,6.54) v4(22.53,25.93) v4(22.5,17.53) v4(22.64,61.69) v4(22.7,45.98) v4(22.69,20.2) v4(22.69,16.25) v4(22.79,53.85) v4(22.78,47.1) v4(22.83,43.49) v4(22.77,24.41) v4(22.87,18.48) v4(23,29.2) v4(23.04,24.02) v4(23.04,23.54) v4(23.01,23.04) v4(22.98,21.27) v4(23.08,52.38) v4(23.09,22.56) v4(23.23,62.29) v4(23.16,25.25) v4(23.23,24.71) v4(23.28,51.24) v4(23.31,46.54) v4(23.26,26.16) v4(23.43,50.54) v4(23.54,20.75) v4(23.56,43.41) v4(23.64,15.31) v4(23.73,23.77) v4(23.67,19.21) v4(23.84,16.63) v4(23.95,63.03) v4(23.88,44.41) v4(23.95,23.09) v4(24.14,48.22) v4(24.11,20.24) v4(24.08,14.52) v4(24.23,51.7) v4(24.16,47.42) v4(24.23,25.2) v4(24.16,24.55) v4(24.39,26.07) v4(24.39,17.57) v4(24.51,18.43) v4(24.64,56.39) v4(24.64,53.85) v4(24.59,53.47) v4(24.62,52.54) v4(24.6,51.06) v4(24.56,50.59) v4(24.56,45.22) v4(24.57,15.5) v4(24.57,14.97) v4(24.74,51.65) v4(24.68,44.56) v4(24.73,21.9) v4(24.75,22.25) v4(25.03,19.17) v4(25.25,28.68) v4(25.23,16.62) v4(25.29,30.19) v4(25.3,29.52) v4(25.38,47.6) v4(25.41,26.11) v4(25.43,14.67) v4(25.39,13.07) v4(25.46,59.91) v4(25.54,50.78) v4(25.47,50.51) v4(25.53,25.23) v4(25.46,22.59) v4(25.52,22.02) v4(25.61,53.74) v4(25.56,23.75) v4(25.6,17.57) v4(25.71,15.65) v4(25.82,44.76) v4(25.8,30.2) v4(25.91,56.39) v4(25.91,47.5) v4(25.91,37.34) v4(25.85,28.95) v4(25.91,24.66) v4(26.02,59.11) v4(26.03,58.36) v4(26.05,61.65) v4(26.15,51.19) v4(26.11,28.41) v4(26.16,60.6) v4(26.16,44.92) v4(26.18,32.99) v4(26.23,25.12) v4(26.2,18.39) v4(26.27,53.7) v4(26.29,35.19) v4(26.3,30.23) v4(26.27,23.77) v4(26.31,14.37) v4(26.42,59.97) v4(26.42,45.98) v4(26.39,26.06) v4(26.48,47.52) v4(26.52,19.27) v4(26.64,16.64) v4(26.63,13.09) v4(26.72,22.8) v4(26.66,17.61) v4(26.74,12.07) v4(26.79,15.66) v4(26.82,14.01) v4(27,44.74) v4(27,35.61) v4(27.13,51.45) v4(27.18,23.94) v4(27.19,23.22) v4(27.22,21.3) v4(27.27,66.29) v4(27.29,32.48) v4(27.3,25.86) v4(27.41,53.42) v4(27.42,52.71) v4(27.37,52.08) v4(27.4,37.15) v4(27.5,25.23) v4(27.9,61.48) v4(27.89,53.11) v4(27.91,48.27) v4(27.87,45.98) v4(27.89,44.94) v4(27.89,44.43) v4(27.97,62.09) v4(28.05,52.37) v4(28.05,36.7) v4(28.06,34.58) v4(28.23,53.64) v4(28.24,46.02) v4(28.23,44.94) v4(28.23,44.43) v4(28.21,37.96) v4(28.28,30.67) v4(28.44,31.97) v4(28.43,30.25) v4(28.4,29.98) v4(28.55,52.67) v4(28.61,66.26) v4(28.61,51.38) v4(28.65,32.7) v4(28.84,28.97) v4(28.94,53.82) v4(28.9,52.02) v4(28.96,46.51) v4(28.99,45.12) v4(28.97,44.48) v4(28.98,31.92) v4(29.1,48.26) v4(29.11,44.06) v4(29.15,30.05) v4(29.34,53.22) v4(29.29,32.94) v4(29.5,37.07) v4(29.55,65.63) v4(29.72,43.69) v4(29.72,30.71) v4(29.79,53.78) v4(29.8,51.85) v4(29.79,50.48) v4(29.81,45.25) v4(30.03,52.62) v4(30.02,44.51) v4(30.05,31.92) v4(29.97,31.41) v4(30.12,35.61) v4(30.05,30.93) v4(30.23,49.76) v4(30.21,35) v4(30.39,53.83) v4(30.4,53.27) v4(30.45,50.3) v4(30.42,36.18) v4(30.45,32.38) v4(30.52,64.66) v4(30.45,51.52) v4(30.6,31.92) v4(30.65,32.37) v4(30.8,33.49) v4(30.94,31.48) v4(30.97,53.82) v4(30.99,45.23) v4(30.99,43.69) v4(31.14,44.52) v4(31.2,31.79) v4(31.27,37.55) v4(31.47,32.4) v4(31.82,44.27) v4(32.02,43.46) v4(31.96,32.93) v4(32.04,31.72) v4(32.15,48.29) v4(32.07,32.23) v4(32.18,45.3) v4(32.21,34.05) v4(32.35,63.09) v4(32.64,67.9) v4(32.8,49.52) v4(32.8,44.2) v4(32.79,34.52) v4(32.86,49.1) v4(32.85,47.98) v4(32.99,10.73) v4(32.99,1.98) v4(33.14,63.23) v4(33.12,49.87) v4(33.25,53.81) v4(33.34,45.34) v4(33.78,54.72) v4(34.05,28.92) v4(34,10.73) v4(34.2,46.23) v4(34.25,5.12) v4(34.48,61.47) v4(34.6,44.99) v4(34.8,48.77) v4(34.91,53.85) v4(34.99,53.41) v4(35,53.02) v4(34.95,48.24) v4(34.99,29.16) v4(35.1,62.44) v4(35.08,28.4) v4(35.19,46.58) v4(35.4,10.73) v4(35.53,63.33) v4(35.58,61.67) v4(35.59,45.3) v4(35.91,29.41) v4(35.85,4.86) v4(36.19,46.68) v4(36.22,45.82) v4(36.24,28.81) v4(36.52,62.92) v4(36.54,61.72) v4(36.5,53.92) v4(36.62,10.71) v4(36.7,15.4) v4(36.75,29.44) v4(36.85,62.29) v4(36.86,59.87) v4(36.91,28.16) v4(36.85,27.52) v4(37.34,62.74) v4(37.34,53.85) v4(37.34,52.58) v4(37.34,45.44) v4(37.31,3.92) v4(37.38,47.88) v4(37.41,46.22) v4(37.47,59.11) v4(37.47,54.72) v4(37.61,10.75) v4(37.82,50.24) v4(37.94,61.73) v4(37.87,48.01) v4(37.88,46.05) v4(37.91,28.75) v4(37.91,4.92) v4(38.02,62.34) v4(38.04,43.37) v4(38.04,3.38) v4(38.2,49.98) v4(38.22,10.9) v4(38.29,55.26) v4(38.61,62.74) v4(38.61,43.69) v4(38.61,9.4) v4(38.69,63.34) v4(38.71,3.01) v4(38.77,55.73) v4(38.84,54.77) v4(38.76,26.59) v4(38.9,49.9) v4(38.93,49.09) v4(38.9,28.68) v4(39.02,44.23) v4(38.96,21.99) v4(39.11,23.98) v4(39.22,61.7) v4(39.3,55.21) v4(39.35,50.48) v4(39.41,49.68) v4(39.48,2.59) v4(39.6,49.3) v4(39.72,62.73) v4(39.69,44.95) v4(39.74,28.13) v4(39.67,3.73) v4(39.9,55.4) v4(39.92,53.37) v4(39.9,21.21) v4(40.02,50.65) v4(39.99,44.11) v4(40.13,54.67) v4(40.09,53.92) v4(40.09,51.19) v4(40.3,63.3) v4(40.27,51.52) v4(40.33,50.12) v4(40.27,25.87) v4(40.43,62.44) v4(40.36,61.63) v4(40.42,10.36) v4(40.55,50.95) v4(40.47,28.14) v4(40.55,11.03) v4(40.56,3.23) v4(40.67,55.23) v4(40.75,55.75) v4(40.8,21.73) v4(40.78,20.36) v4(40.89,51.55) v4(40.94,45.2) v4(40.91,24.59) v4(41.04,52.96) v4(41,52.55) v4(41.06,52.06) v4(41.09,47.95) v4(41.09,47.17) v4(41.15,19.39) v4(41.09,4.21) v4(41.24,61.5) v4(41.25,27.39) v4(41.23,9.94) v4(41.3,53.09) v4(41.4,61.03) v4(41.55,54.17) v4(41.58,52.9) v4(41.63,51.11) v4(41.56,18.06) v4(41.7,53.64) v4(41.69,25.46) v4(41.85,50.02) v4(41.84,4.24) v4(41.85,3.15) v4(41.91,54.73) v4(41.88,54.05) v4(41.87,50.93) v4(41.91,49.43) v4(41.92,48.46) v4(41.93,47.78) v4(41.86,28.03) v4(41.94,11.03) v4(41.96,48.25) v4(41.97,23.39) v4(41.97,22.18) v4(41.95,10.39) v4(42.15,19.4) v4(42.17,47.1) v4(42.3,27.33) v4(42.42,58.93) v4(42.4,54.42) v4(42.51,48.33) v4(42.65,54.98) v4(42.58,49.92) v4(42.62,18.57) v4(42.6,17.73) v4(42.74,53.93) v4(42.71,52.47) v4(42.7,25.91) v4(42.79,48.06) v4(42.83,4.29) v4(42.94,63.13) v4(42.87,50.95) v4(42.89,50.11) v4(42.91,49.32) v4(42.95,67.92) v4(42.97,54.49) v4(42.97,49.74) v4(43.04,48.58) v4(43.12,61.34) v4(43.07,24.36) v4(43.1,20.74) v4(43.17,67.11) v4(43.16,3.3) v4(43.26,65.45) v4(43.26,54.97) v4(43.42,62.23) v4(43.36,50.42) v4(43.39,17.86) v4(43.38,16.25) v4(43.46,54.05) v4(43.48,49.77) v4(43.46,48.74) v4(43.55,19.34) v4(43.52,4.18) v4(43.61,25.29) v4(43.81,63.16) v4(43.76,22.97) v4(43.87,53.46) v4(43.89,52.64) v4(43.95,55.05) v4(43.95,54.16) v4(43.99,18.22) v4(44.22,16.78) v4(44.17,3.55) v4(44.51,55.87) v4(44.52,29.3) v4(44.45,26.27) v4(44.63,54.65) v4(44.63,53.49) v4(44.63,19.43) v4(44.69,28.52) v4(44.74,23.76) v4(44.84,62.51) v4(44.84,4.13) v4(44.94,63.23) v4(44.87,54.95) v4(44.94,25.21) v4(44.96,61.97) v4(45.15,17.39) v4(45.34,18.5) v4(45.32,15.48) v4(45.38,22.73) v4(45.53,20.77) v4(45.66,3.15) v4(45.83,10.85) v4(46.02,27.72) v4(45.97,25.23) v4(45.98,7.54) v4(46.12,62.02) v4(46.22,23.66) v4(46.23,15.75) v4(46.16,9.89) v4(46.23,8.13) v4(46.23,5.59) v4(46.23,3.6) v4(46.26,19.91) v4(46.39,67.9) v4(46.48,26.83) v4(46.59,21.82) v4(46.7,16.5) v4(46.76,67.04) v4(46.78,63.97) v4(46.82,17.75) v4(46.76,8.41) v4(46.95,10.76) v4(46.93,3.15) v4(46.99,7.46) v4(47.12,65.03) v4(47.23,4.15) v4(47.3,13.18) v4(47.46,22.67) v4(47.5,15.75) v4(47.5,14.48) v4(47.5,11.94) v4(47.5,9.4) v4(47.65,20.29) v4(47.62,18.64) v4(47.8,67.89) v4(47.94,11.31) v4(47.9,8.96) v4(47.88,7.66) v4(48.05,5.38) v4(48.1,3.99) v4(48.32,3.2) v4(48.63,4.75) v4(48.68,61.98) v4(49.26,6.21) v4(50.12,6.29) v5(0.65,47.23) v5(0.65,45.95) v5(0.65,43.39) v5(0.64,41) v5(0.62,39.34) v5(0.62,37.28) v5(0.63,34.03) v5(0.63,32.86) v5(0.63,31.41) v5(0.61,30.07) v5(0.7,44.48) v5(1.06,46.23) v5(1.1,45.16) v5(1.22,52.81) v5(1.17,47.68) v5(1.22,43.95) v5(1.51,42.62) v5(1.73,59.61) v5(1.68,46.91) v5(1.66,6.75) v5(1.7,6.07) v5(1.79,51.72) v5(1.86,58.26) v5(2.04,47.62) v5(2.2,57.8) v5(2.52,52.33) v5(2.55,46.91) v5(2.5,43.67) v5(2.9,58.97) v5(3.12,48.35) v5(3.1,47.47) v5(3.23,6.41) v5(3.37,63.03) v5(3.5,52.62) v5(3.54,51.59) v5(3.52,46.98) v5(3.49,27.13) v5(3.54,4.23) v5(3.6,50.78) v5(3.59,49.22) v5(3.56,48.09) v5(3.65,56.44) v5(3.79,25.82) v5(3.8,4.76) v5(3.88,59.29) v5(3.98,25.11) v5(4.05,27.72) v5(4.32,62.74) v5(4.32,25.91) v5(4.32,13.21) v5(4.53,28.5) v5(4.54,2.66) v5(4.75,61.78) v5(5.33,36.01) v5(5.5,63.16) v5(5.52,1.92) v5(6.08,36.7) v5(6.36,35.54) v5(6.42,28.34) v5(6.5,16.55) v5(6.46,15.17) v5(6.59,63.87) v5(6.61,62.22) v5(6.77,62.99) v5(6.85,58.85) v5(6.76,17.73) v5(6.86,17.02) v5(7.21,57.72) v5(7.18,25.36) v5(7.18,24.82) v5(7.32,63.91) v5(7.34,59.4) v5(7.34,37.52) v5(7.38,36.9) v5(7.5,46.48) v5(7.46,45.07) v5(7.46,30.16) v5(7.72,53.05) v5(7.8,18.54) v5(7.82,16.41) v5(7.86,62.99) v5(8.02,57.71) v5(8.14,62.24) v5(8.12,18.11) v5(8.19,63.88) v5(8.32,48.25) v5(8.29,46.91) v5(8.38,51.74) v5(8.44,50.38) v5(8.39,49.28) v5(8.54,32.83) v5(8.64,52.7) v5(9.08,19.14) v5(9.16,57.72) v5(9.33,56.22) v5(9.29,46.73) v5(9.31,11.88) v5(9.43,63.91) v5(9.4,26.61) v5(9.61,40.78) v5(9.62,34.4) v5(9.64,32.74) v5(9.69,52.8) v5(9.77,57.3) v5(10.09,53.81) v5(10.18,59.55) v5(10.2,58.64) v5(10.25,57.66) v5(10.32,56.27) v5(10.37,63.92) v5(10.39,41.81) v5(10.54,56.65) v5(10.48,39.88) v5(10.56,60.02) v5(10.67,61.77) v5(10.72,52.78) v5(10.72,46.73) v5(10.73,40.99) v5(10.81,58.64) v5(10.78,55.52) v5(10.86,57.52) v5(10.9,27.11) v5(11.03,62.26) v5(10.99,61.15) v5(10.99,53.8) v5(11.11,1.44) v5(11.23,56.71) v5(11.22,40.38) v5(11.36,60.34) v5(11.4,59.81) v5(11.41,55.79) v5(11.39,34.1) v5(11.41,33.3) v5(11.63,36.63) v5(11.68,63.95) v5(11.68,37.62) v5(11.66,35.13) v5(11.73,0.8) v5(11.79,57.68) v5(11.83,50.56) v5(11.77,50.05) v5(11.85,46.78) v5(11.91,61.74) v5(11.94,19.56) v5(11.98,61.05) v5(12.05,59.95) v5(12.2,35.62) v5(12.15,34.49) v5(12.18,33.63) v5(12.4,56.27) v5(12.36,37.77) v5(12.4,22.11) v5(12.47,57.71) v5(12.63,63.93) v5(12.59,60.91) v5(12.71,62.26) v5(12.83,56.98) v5(12.79,50.57) v5(12.83,39.5) v5(12.78,34.1) v5(12.84,32.37) v5(12.9,27.11) v5(13.07,18.1) v5(13.22,62.13) v5(13.18,61.77) v5(13.22,61.2) v5(13.24,60.44) v5(13.21,50.04) v5(13.21,36.23) v5(13.29,57.7) v5(13.36,15.74) v5(13.67,63.96) v5(13.7,50.58) v5(13.85,57.7) v5(13.85,36.45) v5(13.89,62.27) v5(13.95,37.6) v5(13.89,32.41) v5(14.02,53.93) v5(14.04,2) v5(14.07,59.87) v5(14.1,56.31) v5(14.05,34.67) v5(14.24,48.85) v5(14.22,33.69) v5(14.23,18.09) v5(14.38,60.18) v5(14.4,26.61) v5(14.4,23.11) v5(14.49,45.88) v5(14.65,63.93) v5(14.56,62.28) v5(14.62,60.7) v5(14.62,58.27) v5(14.61,55.51) v5(14.62,48.24) v5(14.72,59.53) v5(14.67,53.82) v5(14.74,49.07) v5(14.72,38.17) v5(14.78,57.11) v5(14.94,45.53) v5(15.01,60.16) v5(15.02,46.23) v5(15.14,49.69) v5(15.06,48.68) v5(15.17,15.74) v5(15.32,62.27) v5(15.27,59.79) v5(15.34,56.05) v5(15.42,19.02) v5(15.5,53.84) v5(15.51,51.72) v5(15.46,21.54) v5(15.61,57.73) v5(15.56,18.07) v5(15.75,20.83) v5(15.83,63.92) v5(15.76,46.71) v5(15.91,56.29) v5(15.88,51.31) v5(15.91,44.38) v5(15.97,62.09) v5(16.02,61.23) v5(16,60.44) v5(16.09,61.69) v5(16.18,57.69) v5(16.16,53.72) v5(16.16,52.97) v5(16.23,42.16) v5(16.28,56.15) v5(16.27,19.33) v5(16.39,51.59) v5(16.39,43.6) v5(16.36,42.98) v5(16.5,45.19) v5(16.48,18.27) v5(16.64,53.44) v5(16.73,63.92) v5(16.73,62.21) v5(16.66,57.04) v5(16.66,50.83) v5(16.7,18.9) v5(16.73,15.75) v5(16.78,61.38) v5(16.76,60.2) v5(16.78,52.67) v5(16.79,51.28) v5(16.77,38.16) v5(16.97,53.1) v5(17.04,51.79) v5(17.02,50.19) v5(17.02,47.7) v5(17.02,18.29) v5(17.14,60.57) v5(17.06,57.7) v5(17.09,56.15) v5(17.09,46.73) v5(17.11,44.47) v5(17.09,33.91) v5(17.17,43.85) v5(17.23,20.04) v5(17.33,51.31) v5(17.4,59.98) v5(17.37,36.9) v5(17.38,16.92) v5(17.54,56.34) v5(17.61,63.92) v5(17.61,61.49) v5(17.57,47.42) v5(17.83,51) v5(17.77,50.62) v5(17.81,50.18) v5(17.79,49.49) v5(17.94,36.61) v5(17.89,19.32) v5(18.01,51.67) v5(18.05,44.62) v5(18.14,62.23) v5(18.07,60.55) v5(18.13,49.74) v5(18.09,46.43) v5(18.26,39.23) v5(18.36,63.97) v5(18.41,59.1) v5(18.41,58.36) v5(18.37,57.74) v5(18.36,56.44) v5(18.4,53.09) v5(18.38,50.98) v5(18.36,50.17) v5(18.46,55.49) v5(18.63,51.68) v5(18.65,49.23) v5(18.66,61.52) v5(18.67,57.15) v5(18.93,60.55) v5(18.93,49.84) v5(18.94,4.21) v5(19.05,62.18) v5(19.16,63.92) v5(19.23,59.98) v5(19.29,50.61) v5(19.3,48.33) v5(19.3,3.02) v5(19.4,56.12) v5(19.45,49.3) v5(19.53,61.45) v5(19.54,60.65) v5(19.5,51.62) v5(19.51,38.62) v5(19.55,62.22) v5(19.63,57.7) v5(19.61,47.74) v5(19.64,37.23) v5(19.68,46.59) v5(19.71,4.97) v5(19.81,59.98) v5(19.8,53.15) v5(19.79,52.59) v5(19.83,52) v5(19.81,50.06) v5(19.82,44.78) v5(19.85,45.91) v5(19.93,2.48) v5(19.98,63.94) v5(19.99,57.15) v5(19.99,51.04) v5(20,48.76) v5(20.06,53.45) v5(20.25,47.12) v5(20.24,43.97) v5(20.33,56.14) v5(20.34,36.4) v5(20.37,57.69) v5(20.37,49.45) v5(20.41,39.26) v5(20.4,5.53) v5(20.5,50.53) v5(20.52,45.16) v5(20.6,60.12) v5(20.59,52.36) v5(20.64,51.65) v5(20.64,48.1) v5(20.64,43.18) v5(20.63,6.01) v5(20.73,56.74) v5(20.69,53.74) v5(20.75,62.38) v5(20.89,47.72) v5(21.03,63.95) v5(21.01,48.85) v5(21.12,57.7) v5(21.08,49.96) v5(21.11,45.87) v5(21.09,40.1) v5(21.13,37.4) v5(21.1,4.91) v5(21.21,59.98) v5(21.21,53.48) v5(21.16,50.91) v5(21.19,44.73) v5(21.23,38.55) v5(21.28,56.12) v5(21.3,47.42) v5(21.32,25.83) v5(21.35,62.27) v5(21.42,61.34) v5(21.45,60.38) v5(21.43,53.83) v5(21.35,6.96) v5(21.39,5.88) v5(21.49,60.83) v5(21.63,57.19) v5(21.63,48.22) v5(21.64,43.62) v5(21.68,51.47) v5(21.69,49.32) v5(21.82,52.91) v5(21.81,46.92) v5(21.82,26.15) v5(21.9,63.97) v5(21.95,56.49) v5(21.94,52.31) v5(21.87,49.98) v5(21.94,24.91) v5(21.91,7.03) v5(21.95,3.04) v5(21.96,62.3) v5(21.96,61.02) v5(22.03,44.81) v5(22.15,57.74) v5(22.14,42.74) v5(22.1,39.88) v5(22.15,18.75) v5(22.22,59.1) v5(22.21,58.37) v5(22.22,55.42) v5(22.25,48.77) v5(22.24,45.46) v5(22.2,23.71) v5(22.26,47.57) v5(22.28,46.45) v5(22.34,21.93) v5(22.27,20.57) v5(22.43,53.48) v5(22.4,29.2) v5(22.38,6.54) v5(22.53,25.93) v5(22.5,17.53) v5(22.64,61.69) v5(22.61,38.73) v5(22.7,57.3) v5(22.7,45.98) v5(22.69,16.25) v5(22.8,60.5) v5(22.84,55.83) v5(22.79,53.85) v5(22.77,49.83) v5(22.78,47.1) v5(22.83,43.49) v5(22.87,59.42) v5(22.87,58.46) v5(22.88,48.12) v5(23,29.2) v5(23.09,67.88) v5(23.1,61.12) v5(23.08,52.38) v5(23.23,62.29) v5(23.21,48.73) v5(23.23,45.49) v5(23.16,44.3) v5(23.16,25.25) v5(23.16,6.87) v5(23.28,51.24) v5(23.31,46.54) v5(23.26,26.16) v5(23.45,59.98) v5(23.42,57.72) v5(23.4,53.05) v5(23.43,50.54) v5(23.37,41.15) v5(23.4,39.99) v5(23.49,47.52) v5(23.56,43.41) v5(23.64,15.31) v5(23.67,61.53) v5(23.72,23.3) v5(23.8,66.31) v5(23.78,57.3) v5(23.79,53.76) v5(23.75,44.98) v5(23.84,16.63) v5(23.95,63.03) v5(23.89,49.78) v5(23.9,45.96) v5(23.88,44.41) v5(23.95,43.76) v5(24.02,60.35) v5(24.07,53.49) v5(24.15,49.21) v5(24.14,48.22) v5(24.08,14.52) v5(24.16,62.4) v5(24.19,57.72) v5(24.24,56.01) v5(24.23,51.7) v5(24.16,47.42) v5(24.23,25.2) v5(24.3,42.74) v5(24.38,60.72) v5(24.39,26.07) v5(24.39,17.57) v5(24.48,67.88) v5(24.46,46.74) v5(24.57,67.06) v5(24.63,62.71) v5(24.64,61.89) v5(24.59,53.47) v5(24.62,52.54) v5(24.6,51.06) v5(24.56,50.59) v5(24.56,45.22) v5(24.65,43.8) v5(24.64,41.15) v5(24.64,39.88) v5(24.57,15.5) v5(24.57,14.97) v5(24.73,61.14) v5(24.74,51.65) v5(24.67,49.82) v5(24.68,44.56) v5(24.67,38.68) v5(24.73,21.9) v5(24.76,60.01) v5(25.01,63.15) v5(25.03,56.05) v5(25.04,46.11) v5(25.15,57.77) v5(25.15,43.76) v5(25.09,43.15) v5(25.21,60.48) v5(25.22,57.38) v5(25.25,28.68) v5(25.23,16.62) v5(25.29,30.19) v5(25.3,29.52) v5(25.39,49.83) v5(25.41,48.74) v5(25.39,48.15) v5(25.38,47.6) v5(25.41,26.11) v5(25.43,14.67) v5(25.39,13.07) v5(25.46,59.91) v5(25.54,50.78) v5(25.47,50.51) v5(25.46,46.93) v5(25.53,25.23) v5(25.64,60.93) v5(25.61,53.74) v5(25.58,45.5) v5(25.6,17.57) v5(25.72,22.8) v5(25.71,15.65) v5(25.78,67.88) v5(25.83,63.15) v5(25.79,51.63) v5(25.82,44.76) v5(25.82,43.84) v5(25.8,30.2) v5(25.85,50.13) v5(25.93,46.41) v5(25.91,41.15) v5(25.91,39.88) v5(25.91,37.34) v5(25.85,28.95) v5(26.02,59.11) v5(26.03,58.36) v5(26.05,61.65) v5(26.15,51.19) v5(26.11,28.41) v5(26.18,66.94) v5(26.16,60.6) v5(26.16,44.92) v5(26.16,42.66) v5(26.18,32.99) v5(26.23,13.74) v5(26.27,53.7) v5(26.33,43.74) v5(26.29,35.19) v5(26.3,30.23) v5(26.31,14.37) v5(26.36,61.1) v5(26.42,59.97) v5(26.38,56.49) v5(26.4,56.06) v5(26.45,48.92) v5(26.44,48.37) v5(26.45,46.74) v5(26.42,45.98) v5(26.39,26.06) v5(26.51,49.74) v5(26.48,47.52) v5(26.64,63.18) v5(26.64,16.64) v5(26.63,13.09) v5(26.67,57.9) v5(26.73,51.65) v5(26.72,22.8) v5(26.66,17.61) v5(26.74,12.07) v5(26.83,50.56) v5(26.79,15.66) v5(26.82,14.01) v5(26.87,60.49) v5(26.91,45.24) v5(27,67.86) v5(27,44.74) v5(27,43.84) v5(27.02,43.11) v5(27,35.61) v5(27.13,51.45) v5(27.14,49.15) v5(27.1,45.75) v5(27.18,41.15) v5(27.18,39.88) v5(27.22,21.3) v5(27.27,66.29) v5(27.3,61.1) v5(27.32,60.03) v5(27.29,32.48) v5(27.3,25.86) v5(27.39,62.94) v5(27.43,62.1) v5(27.41,53.42) v5(27.42,52.71) v5(27.37,52.08) v5(27.45,49.94) v5(27.4,37.15) v5(27.5,25.23) v5(27.64,67.12) v5(27.75,60.63) v5(27.78,43.49) v5(27.9,61.48) v5(27.89,53.11) v5(27.89,49.18) v5(27.91,48.27) v5(27.91,47.59) v5(27.88,46.93) v5(27.87,45.98) v5(27.89,44.94) v5(27.89,44.43) v5(27.91,42.69) v5(27.97,62.09) v5(28.13,56.8) v5(28.05,52.37) v5(28.09,50.52) v5(28.12,43.79) v5(28.05,36.7) v5(28.06,34.58) v5(28.23,53.64) v5(28.24,46.02) v5(28.23,44.94) v5(28.23,44.43) v5(28.25,39.77) v5(28.21,37.96) v5(28.3,60.08) v5(28.29,47.09) v5(28.28,30.67) v5(28.43,67.86) v5(28.45,41.15) v5(28.44,31.97) v5(28.43,30.25) v5(28.4,29.98) v5(28.55,52.67) v5(28.61,66.26) v5(28.61,51.38) v5(28.6,49.21) v5(28.65,32.7) v5(28.67,43.51) v5(28.72,24.3) v5(28.72,22.8) v5(28.84,28.97) v5(28.94,53.82) v5(28.9,52.02) v5(28.86,47.65) v5(28.97,59.95) v5(28.96,46.51) v5(28.97,45.82) v5(28.99,45.12) v5(28.97,44.48) v5(28.98,31.92) v5(29.1,48.26) v5(29.11,44.06) v5(29.09,43.02) v5(29.15,30.05) v5(29.2,66.89) v5(29.2,57.9) v5(29.24,56.78) v5(29.2,49.97) v5(29.2,17.35) v5(29.18,12.29) v5(29.34,53.22) v5(29.29,32.94) v5(29.54,47.23) v5(29.5,37.07) v5(29.55,65.63) v5(29.72,43.69) v5(29.72,41.15) v5(29.72,39.88) v5(29.72,30.71) v5(29.73,21.21) v5(29.79,53.78) v5(29.8,51.85) v5(29.79,50.48) v5(29.81,45.25) v5(29.78,19.93) v5(29.77,18.82) v5(29.78,13.24) v5(29.84,11.53) v5(29.9,67.88) v5(29.86,16.64) v5(30.03,52.62) v5(29.95,46.14) v5(30.02,44.51) v5(29.98,42.72) v5(30.05,31.92) v5(29.97,31.41) v5(30.03,29.69) v5(30.15,56.11) v5(30.11,47.83) v5(30.12,35.61) v5(30.05,30.93) v5(30.23,49.76) v5(30.21,35) v5(30.27,47.07) v5(30.34,13.39) v5(30.42,56.79) v5(30.39,53.83) v5(30.4,53.27) v5(30.45,50.3) v5(30.42,36.18) v5(30.45,32.38) v5(30.43,11.7) v5(30.52,64.66) v5(30.45,51.52) v5(30.6,31.92) v5(30.64,19.8) v5(30.73,48.43) v5(30.65,32.37) v5(30.73,29.91) v5(30.7,21.24) v5(30.8,33.49) v5(30.77,23.54) v5(30.84,18.44) v5(30.91,67.12) v5(30.92,42.44) v5(30.94,31.48) v5(30.91,17.51) v5(31.04,56.07) v5(30.97,53.82) v5(30.99,45.23) v5(30.99,43.69) v5(30.99,41.15) v5(31,16.64) v5(31.11,66.03) v5(31.11,53.16) v5(31.15,50.76) v5(31.14,44.52) v5(31.24,48.93) v5(31.24,47.74) v5(31.18,46.11) v5(31.2,31.79) v5(31.31,46.84) v5(31.27,37.55) v5(31.5,64.63) v5(31.46,56.79) v5(31.47,52.38) v5(31.46,42.92) v5(31.47,32.4) v5(31.59,53.63) v5(31.57,51.62) v5(31.64,39.77) v5(31.64,20.27) v5(31.75,18.8) v5(31.79,56.09) v5(31.75,49.46) v5(31.82,44.27) v5(31.77,21.08) v5(31.8,17.48) v5(31.99,50.95) v5(31.97,48.98) v5(32.02,43.46) v5(31.96,32.93) v5(32.04,31.72) v5(32.15,48.29) v5(32.07,32.23) v5(32.08,23.8) v5(32.12,16.68) v5(32.23,66.51) v5(32.21,56.77) v5(32.21,53.44) v5(32.18,45.3) v5(32.2,42.42) v5(32.21,34.05) v5(32.26,56.39) v5(32.26,52.83) v5(32.26,52.16) v5(32.32,50.07) v5(32.34,47.39) v5(32.26,41.15) v5(32.42,65.17) v5(32.35,63.09) v5(32.38,59.96) v5(32.38,46.18) v5(32.5,51.49) v5(32.64,67.9) v5(32.7,22) v5(32.8,49.52) v5(32.8,44.2) v5(32.79,34.52) v5(32.94,55.93) v5(32.93,50.67) v5(32.86,49.1) v5(32.85,47.98) v5(32.94,20.48) v5(33.05,21.39) v5(32.99,10.73) v5(32.99,1.98) v5(33.09,64.56) v5(33.14,63.23) v5(33.12,49.87) v5(33.12,43.16) v5(33.07,23.8) v5(33.25,53.81) v5(33.23,51.65) v5(33.21,51.22) v5(33.17,48.52) v5(33.19,46.84) v5(33.2,46.02) v5(33.34,45.34) v5(33.41,39.62) v5(33.51,60) v5(33.55,51.28) v5(33.53,41.15) v5(33.58,63.62) v5(33.64,22.92) v5(33.66,51.66) v5(33.67,43.98) v5(33.73,42.41) v5(33.78,54.72) v5(33.78,22.22) v5(33.94,47.36) v5(33.9,45.22) v5(33.95,35.15) v5(34.05,28.92) v5(34,10.73) v5(34.2,46.23) v5(34.25,5.12) v5(34.34,49.4) v5(34.3,48.7) v5(34.33,43.02) v5(34.28,21.43) v5(34.44,22.18) v5(34.48,61.47) v5(34.49,47.81) v5(34.64,59.99) v5(34.6,44.99) v5(34.65,44.12) v5(34.73,51.66) v5(34.69,19.93) v5(34.8,48.77) v5(34.8,41.15) v5(34.87,49.4) v5(34.99,53.41) v5(35,53.02) v5(34.95,48.24) v5(34.99,29.16) v5(35.15,64.56) v5(35.1,62.44) v5(35.08,28.4) v5(35.19,46.58) v5(35.19,38.31) v5(35.26,49.99) v5(35.31,41.91) v5(35.44,48.83) v5(35.39,32.72) v5(35.4,10.73) v5(35.53,63.33) v5(35.48,31.2) v5(35.58,61.67) v5(35.59,51.52) v5(35.61,50.99) v5(35.59,45.3) v5(35.62,37.09) v5(35.67,43.27) v5(35.71,35.23) v5(35.83,39.62) v5(35.9,49.25) v5(35.88,44.47) v5(35.91,29.41) v5(35.85,4.86) v5(35.99,50.03) v5(36.19,46.68) v5(36.22,45.82) v5(36.24,28.81) v5(36.26,64.02) v5(36.38,47.51) v5(36.52,62.92) v5(36.54,61.72) v5(36.52,39.03) v5(36.52,19.84) v5(36.62,10.71) v5(36.73,44.53) v5(36.73,41.84) v5(36.72,40.99) v5(36.7,15.4) v5(36.8,46.48) v5(36.75,29.44) v5(36.85,62.29) v5(36.86,59.87) v5(36.91,28.16) v5(36.85,27.52) v5(36.95,43.26) v5(37.16,60.87) v5(37.2,20.34) v5(37.28,64.69) v5(37.34,62.74) v5(37.34,56.39) v5(37.34,52.58) v5(37.34,45.44) v5(37.31,3.92) v5(37.38,48.51) v5(37.38,47.88) v5(37.41,46.22) v5(37.51,60) v5(37.47,59.11) v5(37.47,54.72) v5(37.65,40.03) v5(37.61,10.75) v5(37.73,44.71) v5(37.82,50.24) v5(37.94,61.73) v5(37.9,49.72) v5(37.87,48.01) v5(37.88,46.05) v5(37.91,37.38) v5(37.91,28.75) v5(37.91,4.92) v5(38.02,62.34) v5(38.04,43.37) v5(38.04,3.38) v5(38.1,56.05) v5(38.22,57.79) v5(38.25,51.01) v5(38.2,49.98) v5(38.18,27.97) v5(38.22,10.9) v5(38.32,41.83) v5(38.41,60.8) v5(38.42,45.28) v5(38.49,59.95) v5(38.49,53.86) v5(38.47,50.45) v5(38.45,48.63) v5(38.61,46.23) v5(38.69,63.34) v5(38.71,56.08) v5(38.74,47.33) v5(38.71,3.01) v5(38.76,26.59) v5(38.9,36.3) v5(38.9,28.68) v5(38.96,57.73) v5(39.02,44.23) v5(38.96,21.99) v5(39.11,23.98) v5(39.22,61.7) v5(39.22,59.96) v5(39.23,53.64) v5(39.3,57.23) v5(39.3,46.27) v5(39.34,39.66) v5(39.37,64.36) v5(39.41,61.01) v5(39.39,56.09) v5(39.41,49.68) v5(39.43,48.44) v5(39.48,2.59) v5(39.56,53) v5(39.6,49.3) v5(39.72,62.73) v5(39.69,44.95) v5(39.74,28.13) v5(39.67,3.73) v5(39.75,51.41) v5(39.79,40.82) v5(39.85,56.84) v5(39.92,53.37) v5(39.88,50.04) v5(39.88,48.77) v5(39.88,47.5) v5(39.88,43.69) v5(39.9,21.21) v5(39.95,59.95) v5(40.02,57.6) v5(40.02,50.65) v5(39.99,44.11) v5(40.09,51.19) v5(40.24,47.98) v5(40.3,63.3) v5(40.33,56.06) v5(40.27,51.52) v5(40.33,50.12) v5(40.33,36.19) v5(40.27,25.87) v5(40.43,62.44) v5(40.36,61.63) v5(40.42,10.36) v5(40.55,50.95) v5(40.47,28.14) v5(40.55,11.03) v5(40.65,54.01) v5(40.56,3.23) v5(40.7,60.7) v5(40.71,56.67) v5(40.68,49.62) v5(40.66,43.12) v5(40.79,48.88) v5(40.8,21.73) v5(40.78,20.36) v5(40.89,51.55) v5(40.94,48.34) v5(40.94,45.2) v5(40.91,24.59) v5(40.96,53.64) v5(41.07,57.6) v5(41.08,56.15) v5(41.09,47.95) v5(41.09,47.17) v5(41.15,19.39) v5(41.09,4.21) v5(41.24,61.5) v5(41.25,56.58) v5(41.25,27.39) v5(41.23,9.94) v5(41.3,53.09) v5(41.4,61.03) v5(41.39,60) v5(41.39,49.7) v5(41.55,64.36) v5(41.54,48.27) v5(41.55,39.45) v5(41.52,36.15) v5(41.63,51.11) v5(41.6,44.14) v5(41.56,37.94) v5(41.56,18.06) v5(41.71,57.29) v5(41.7,53.64) v5(41.67,41.84) v5(41.69,25.46) v5(41.76,40.94) v5(41.84,4.24) v5(41.85,3.15) v5(41.91,54.73) v5(41.88,54.05) v5(41.93,47.78) v5(41.86,28.03) v5(41.94,11.03) v5(41.95,57.92) v5(42.02,56.64) v5(41.96,48.25) v5(41.97,23.39) v5(41.97,22.18) v5(41.95,10.39) v5(42.15,19.4) v5(42.17,56.14) v5(42.17,47.1) v5(42.33,49.7) v5(42.31,43.6) v5(42.3,27.33) v5(42.41,59.95) v5(42.51,48.33) v5(42.56,57.72) v5(42.65,56.1) v5(42.6,45.05) v5(42.62,18.57) v5(42.6,17.73) v5(42.71,52.47) v5(42.7,25.91) v5(42.79,48.06) v5(42.83,4.29) v5(42.94,63.13) v5(42.91,57.56) v5(42.87,50.95) v5(42.89,50.11) v5(42.91,49.32) v5(42.95,67.92) v5(42.97,49.74) v5(43.04,48.58) v5(43.12,61.34) v5(43.11,51.67) v5(43.07,24.36) v5(43.1,20.74) v5(43.17,67.11) v5(43.21,59.94) v5(43.26,65.45) v5(43.26,64.33) v5(43.31,56.07) v5(43.42,62.23) v5(43.37,53.72) v5(43.36,50.42) v5(43.38,45.92) v5(43.39,17.86) v5(43.38,16.25) v5(43.55,57.29) v5(43.48,49.77) v5(43.46,48.74) v5(43.55,44.24) v5(43.47,43.55) v5(43.55,19.34) v5(43.52,4.18) v5(43.61,25.29) v5(43.66,50.96) v5(43.81,63.16) v5(43.82,51.78) v5(43.76,22.97) v5(43.87,53.46) v5(43.89,52.64) v5(44.03,62.17) v5(44.05,60.77) v5(44.01,59.96) v5(43.95,56.08) v5(44.02,53.81) v5(43.99,18.22) v5(44.06,50.37) v5(44.11,49.39) v5(44.22,16.78) v5(44.17,3.55) v5(44.32,48.79) v5(44.44,53.99) v5(44.41,52.43) v5(44.39,3.15) v5(44.51,41.8) v5(44.52,29.3) v5(44.45,26.27) v5(44.57,51.75) v5(44.56,51) v5(44.63,19.43) v5(44.74,49.93) v5(44.69,28.52) v5(44.74,23.76) v5(44.84,62.51) v5(44.84,4.13) v5(44.94,63.23) v5(44.87,54.95) v5(44.94,25.21) v5(44.96,61.97) v5(44.96,15.75) v5(45.1,52.57) v5(45.15,17.39) v5(45.24,50.54) v5(45.31,60.98) v5(45.26,56.89) v5(45.33,51.72) v5(45.34,18.5) v5(45.32,15.48) v5(45.38,22.73) v5(45.53,20.77) v5(45.6,53.08) v5(45.74,48.69) v5(45.66,3.15) v5(45.82,57.37) v5(45.77,56.39) v5(45.83,10.85) v5(45.94,54.63) v5(45.92,53.74) v5(45.89,52.29) v5(46.02,63.9) v5(45.96,55.42) v5(46.02,27.72) v5(45.97,25.23) v5(45.98,7.54) v5(46.12,62.02) v5(46.22,23.66) v5(46.23,15.75) v5(46.16,9.89) v5(46.23,9.4) v5(46.23,8.13) v5(46.23,3.6) v5(46.34,57.95) v5(46.28,50.15) v5(46.27,41.85) v5(46.26,19.91) v5(46.39,67.9) v5(46.4,56.78) v5(46.4,52.84) v5(46.39,47.98) v5(46.48,26.83) v5(46.65,54.94) v5(46.65,54) v5(46.65,52.03) v5(46.59,21.82) v5(46.74,59.15) v5(46.66,55.75) v5(46.7,16.5) v5(46.76,67.04) v5(46.78,63.97) v5(46.78,60.87) v5(46.83,45.27) v5(46.82,17.75) v5(46.76,8.41) v5(46.95,10.76) v5(46.93,3.15) v5(46.99,7.46) v5(47.12,65.03) v5(47.13,48.98) v5(47.23,4.15) v5(47.3,53.56) v5(47.3,13.18) v5(47.35,62.6) v5(47.46,22.67) v5(47.5,9.4) v5(47.6,56.93) v5(47.55,50.44) v5(47.61,41.71) v5(47.65,20.29) v5(47.62,18.64) v5(47.8,67.89) v5(47.78,58.48) v5(47.83,51.91) v5(47.86,55.05) v5(47.94,11.31) v5(47.9,8.96) v5(47.88,7.66) v5(48.05,61.19) v5(48.01,47.47) v5(48.05,5.38) v5(48.1,3.99) v5(48.18,59.76) v5(48.32,3.2) v5(48.58,56.35) v5(48.63,4.75) v5(48.68,61.98) v5(48.7,54.01) v5(48.7,48.72) v5(48.67,44.01) v5(48.82,49.91) v5(48.87,58.87) v5(48.88,51.62) v5(49.02,42.89) v5(49.23,57.02) v5(49.33,64.78) v5(49.3,63.03) v5(49.26,6.21) v5(49.46,47.45) v5(50.12,6.29) v5(50.19,58.87) v5(50.63,59.6) v5(50.73,56.69) v5(50.94,62.77) v5(50.94,61.12) v5(51.23,64.34) v5(51.28,66.77) v6(0.76,63.77) v6(0.76,62.5) v6(0.76,61.23) v6(0.76,59.96) v6(0.76,58.69) v6(0.76,57.42) v6(0.76,56.15) v6(0.76,52.34) v6(0.76,51.07) v6(0.76,49.8) v6(0.76,48.53) v6(1.58,63.82) v6(1.6,60.78) v6(1.63,57) v6(1.77,61.78) v6(1.82,20.77) v6(1.8,16.52) v6(1.84,13.91) v6(2.12,11.44) v6(2.31,63.83) v6(2.38,63.19) v6(2.4,62.29) v6(2.42,19.06) v6(2.92,57.02) v6(3.28,63.86) v6(3.64,57.93) v6(3.81,5.29) v6(3.92,2.23) v6(4.42,63.84) v6(4.72,5.37) v6(4.82,1.34) v6(5.16,63.85) v6(5.59,3.05) v6(5.7,63.85) v6(5.95,0.76) v6(9.79,2.62) v6(9.85,1.43) v6(9.76,0.76) v6(21.09,46.74) v6(22.09,0.77) v6(22.21,65.6) v6(22.22,64.64) v6(22.32,67.82) v6(22.29,66.69) v6(22.46,50.76) v6(22.84,1.4) v6(22.91,67.33) v6(23.45,2.17) v6(23.72,0.76) v6(24.15,64.61) v6(24.14,50.73) v6(24.34,63.3) v6(24.96,64.03) v6(25.05,64.56) v6(26.04,64.06) v6(26.64,3.1) v6(26.64,1.67) v6(27.08,56.27) v6(28.02,56.23) v6(29.2,1.7) v6(29.3,56.24) v6(29.85,3.56) v6(31.21,67.82) v6(31.7,4.36) v6(32.62,0.76) v6(33.53,3.05) v6(33.68,4.32) v6(33.89,0.76) v6(34.17,60.73) v6(34.8,66.55) v6(34.8,65.3) v6(35.02,67.82) v6(36.04,67.81) v6(35.95,66.47) v6(36.07,65.3) v6(36.87,66.25) v6(37.28,63.34) v6(37.56,67.82) v6(37.69,0.92) v6(37.97,2.48) v6(38.13,66.21) v6(38.61,65.3) v6(38.59,1.82) v6(38.92,67.82) v6(39.04,66.45) v6(39.55,24.92) v6(39.88,66.55) v6(39.88,65.3) v6(40.05,46.49) v6(40.1,67.82) v6(40.3,45.28) v6(41.05,45.94) v6(41.15,66.55) v6(41.14,65.31) v6(41.09,46.65) v6(41.37,67.82) v6(41.81,46.61) v6(42.66,9.39) v6(43.52,10.22) v6(43.91,67.82) v6(45.18,67.82) v6(45.53,10.09) v6(47.57,21.24) v6(48.09,65.5) v6(48.06,63.87) v6(48.77,66.55) v6(48.99,67.82) v6(49.24,4.41) v6(49.52,5.55) v6(49.51,3.3) v6(49.73,60.65) v6(49.77,61.91) v6(49.91,43.44) v6(49.98,51.06) v6(49.99,48.52) v6(50,40.88) v6(50.04,24.64) v6(50.05,13.83) v6(50.01,11.31) v6(50.13,16.42) v6(50.12,8.79) v6(50.17,65.53) v6(50.19,63.9) v6(50.2,21.55) v6(50.18,18.99) v6(50.26,67.82) v6(50.26,66.47) v6(50.78,3.3) v6(51.31,51.31) v6(51.31,24.64) v6(51.53,67.82) v6(51.52,43.45) v6(51.51,35.83) v6(51.53,30.84) v6(51.52,28.17) v6(51.49,21.53) v6(51.52,19.09) v6(51.52,13.93) v6(51.52,6.33) v6(51.62,60.75) v6(51.6,48.47) v6(51.59,40.98) v6(51.56,38.37) v6(51.58,33.27) v6(51.55,16.45) v6(51.55,11.47) v6(51.55,8.86) v6(51.8,61.92) v6(51.91,65.63) v6(51.93,63.85) v6(51.96,3.76) v6(52.58,67.1) v6(52.58,65.83) v6(52.58,64.56) v6(52.58,63.29) v6(52.58,62.02) v6(52.58,60.75) v6(52.58,59.48) v6(52.58,58.21) v6(52.58,56.94) v6(52.58,55.67) v6(52.58,54.4) v6(52.58,51.86) v6(52.58,50.59) v6(52.58,49.32) v6(52.58,45.51) v6(52.58,44.24) v6(52.58,42.97) v6(52.58,41.7) v6(52.58,40.43) v6(52.58,39.16) v6(52.58,37.89) v6(52.58,36.62) v6(52.58,35.35) v6(52.58,34.08) v6(52.58,32.81) v6(52.58,31.54) v6(52.58,30.27) v6(52.58,29) v6(52.58,27.73) v6(52.58,26.46) v6(52.58,25.19) v6(52.58,23.92) v6(52.58,22.65) v6(52.58,21.38) v6(52.58,20.11) v6(52.58,18.84) v6(52.58,17.57) v6(52.58,16.3) v6(52.58,15.03) v6(52.58,13.76) v6(52.58,12.49) v6(52.58,11.22) v6(52.58,9.95) v6(52.58,8.68) v6(52.58,7.41) v6(52.58,6.14) v6(52.58,4.87)
